VERSION 5.8 ;
BUSBITCHARS "[]" ;
DIVIDERCHAR "/" ;
UNITS
    DATABASE MICRONS 1000 ;
END UNITS

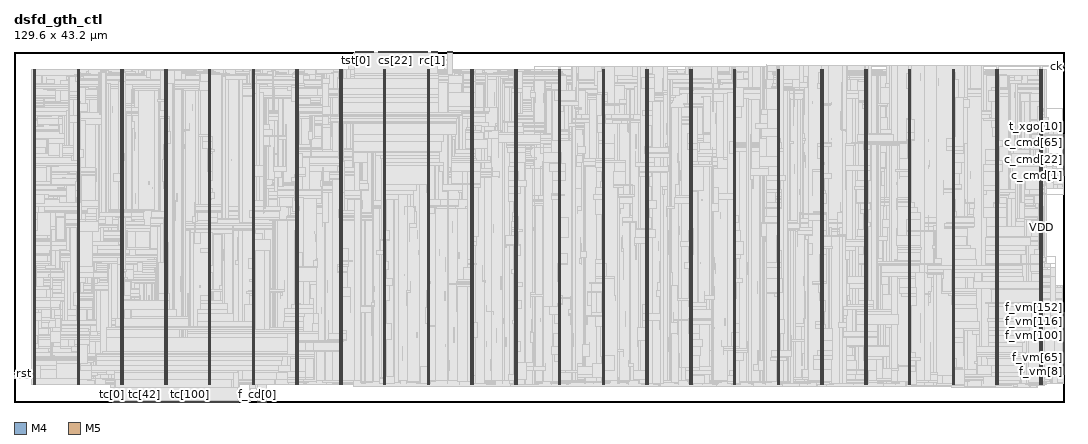
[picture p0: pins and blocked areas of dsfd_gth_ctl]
MACRO dsfd_gth_ctl
  FOREIGN dsfd_gth_ctl 0 0 ;
  CLASS BLOCK ;
  SIZE 129.6 BY 43.2 ;
  PIN c_cmd[0]
    DIRECTION INPUT ;
    USE SIGNAL ;
    PORT
      LAYER M4 ;
        RECT  129.516 27.936 129.6 27.96 ;
    END
  END c_cmd[0]
  PIN c_cmd[10]
    DIRECTION INPUT ;
    USE SIGNAL ;
    PORT
      LAYER M4 ;
        RECT  129.516 28.416 129.6 28.44 ;
    END
  END c_cmd[10]
  PIN c_cmd[11]
    DIRECTION INPUT ;
    USE SIGNAL ;
    PORT
      LAYER M4 ;
        RECT  129.516 28.464 129.6 28.488 ;
    END
  END c_cmd[11]
  PIN c_cmd[12]
    DIRECTION INPUT ;
    USE SIGNAL ;
    PORT
      LAYER M4 ;
        RECT  129.516 28.512 129.6 28.536 ;
    END
  END c_cmd[12]
  PIN c_cmd[13]
    DIRECTION INPUT ;
    USE SIGNAL ;
    PORT
      LAYER M4 ;
        RECT  129.516 28.56 129.6 28.584 ;
    END
  END c_cmd[13]
  PIN c_cmd[14]
    DIRECTION INPUT ;
    USE SIGNAL ;
    PORT
      LAYER M4 ;
        RECT  129.516 28.608 129.6 28.632 ;
    END
  END c_cmd[14]
  PIN c_cmd[15]
    DIRECTION INPUT ;
    USE SIGNAL ;
    PORT
      LAYER M4 ;
        RECT  129.516 28.656 129.6 28.68 ;
    END
  END c_cmd[15]
  PIN c_cmd[16]
    DIRECTION INPUT ;
    USE SIGNAL ;
    PORT
      LAYER M4 ;
        RECT  129.516 28.704 129.6 28.728 ;
    END
  END c_cmd[16]
  PIN c_cmd[17]
    DIRECTION INPUT ;
    USE SIGNAL ;
    PORT
      LAYER M4 ;
        RECT  129.516 28.752 129.6 28.776 ;
    END
  END c_cmd[17]
  PIN c_cmd[18]
    DIRECTION INPUT ;
    USE SIGNAL ;
    PORT
      LAYER M4 ;
        RECT  129.516 28.8 129.6 28.824 ;
    END
  END c_cmd[18]
  PIN c_cmd[19]
    DIRECTION INPUT ;
    USE SIGNAL ;
    PORT
      LAYER M4 ;
        RECT  129.516 28.848 129.6 28.872 ;
    END
  END c_cmd[19]
  PIN c_cmd[1]
    DIRECTION INPUT ;
    USE SIGNAL ;
    PORT
      LAYER M4 ;
        RECT  129.516 27.984 129.6 28.008 ;
    END
  END c_cmd[1]
  PIN c_cmd[20]
    DIRECTION INPUT ;
    USE SIGNAL ;
    PORT
      LAYER M4 ;
        RECT  129.516 28.896 129.6 28.92 ;
    END
  END c_cmd[20]
  PIN c_cmd[21]
    DIRECTION INPUT ;
    USE SIGNAL ;
    PORT
      LAYER M4 ;
        RECT  129.516 28.944 129.6 28.968 ;
    END
  END c_cmd[21]
  PIN c_cmd[22]
    DIRECTION INPUT ;
    USE SIGNAL ;
    PORT
      LAYER M4 ;
        RECT  129.516 28.992 129.6 29.016 ;
    END
  END c_cmd[22]
  PIN c_cmd[23]
    DIRECTION INPUT ;
    USE SIGNAL ;
    PORT
      LAYER M4 ;
        RECT  129.516 29.04 129.6 29.064 ;
    END
  END c_cmd[23]
  PIN c_cmd[24]
    DIRECTION INPUT ;
    USE SIGNAL ;
    PORT
      LAYER M4 ;
        RECT  129.516 29.088 129.6 29.112 ;
    END
  END c_cmd[24]
  PIN c_cmd[25]
    DIRECTION INPUT ;
    USE SIGNAL ;
    PORT
      LAYER M4 ;
        RECT  129.516 29.136 129.6 29.16 ;
    END
  END c_cmd[25]
  PIN c_cmd[26]
    DIRECTION INPUT ;
    USE SIGNAL ;
    PORT
      LAYER M4 ;
        RECT  129.516 29.184 129.6 29.208 ;
    END
  END c_cmd[26]
  PIN c_cmd[27]
    DIRECTION INPUT ;
    USE SIGNAL ;
    PORT
      LAYER M4 ;
        RECT  129.516 29.232 129.6 29.256 ;
    END
  END c_cmd[27]
  PIN c_cmd[28]
    DIRECTION INPUT ;
    USE SIGNAL ;
    PORT
      LAYER M4 ;
        RECT  129.516 29.28 129.6 29.304 ;
    END
  END c_cmd[28]
  PIN c_cmd[29]
    DIRECTION INPUT ;
    USE SIGNAL ;
    PORT
      LAYER M4 ;
        RECT  129.516 29.328 129.6 29.352 ;
    END
  END c_cmd[29]
  PIN c_cmd[2]
    DIRECTION INPUT ;
    USE SIGNAL ;
    PORT
      LAYER M4 ;
        RECT  129.516 28.032 129.6 28.056 ;
    END
  END c_cmd[2]
  PIN c_cmd[30]
    DIRECTION INPUT ;
    USE SIGNAL ;
    PORT
      LAYER M4 ;
        RECT  129.516 29.376 129.6 29.4 ;
    END
  END c_cmd[30]
  PIN c_cmd[31]
    DIRECTION INPUT ;
    USE SIGNAL ;
    PORT
      LAYER M4 ;
        RECT  129.516 29.424 129.6 29.448 ;
    END
  END c_cmd[31]
  PIN c_cmd[32]
    DIRECTION INPUT ;
    USE SIGNAL ;
    PORT
      LAYER M4 ;
        RECT  129.516 29.472 129.6 29.496 ;
    END
  END c_cmd[32]
  PIN c_cmd[33]
    DIRECTION INPUT ;
    USE SIGNAL ;
    PORT
      LAYER M4 ;
        RECT  129.516 29.52 129.6 29.544 ;
    END
  END c_cmd[33]
  PIN c_cmd[34]
    DIRECTION INPUT ;
    USE SIGNAL ;
    PORT
      LAYER M4 ;
        RECT  129.516 29.568 129.6 29.592 ;
    END
  END c_cmd[34]
  PIN c_cmd[35]
    DIRECTION INPUT ;
    USE SIGNAL ;
    PORT
      LAYER M4 ;
        RECT  129.516 29.616 129.6 29.64 ;
    END
  END c_cmd[35]
  PIN c_cmd[36]
    DIRECTION INPUT ;
    USE SIGNAL ;
    PORT
      LAYER M4 ;
        RECT  129.516 29.664 129.6 29.688 ;
    END
  END c_cmd[36]
  PIN c_cmd[37]
    DIRECTION INPUT ;
    USE SIGNAL ;
    PORT
      LAYER M4 ;
        RECT  129.516 29.712 129.6 29.736 ;
    END
  END c_cmd[37]
  PIN c_cmd[38]
    DIRECTION INPUT ;
    USE SIGNAL ;
    PORT
      LAYER M4 ;
        RECT  129.516 29.76 129.6 29.784 ;
    END
  END c_cmd[38]
  PIN c_cmd[39]
    DIRECTION INPUT ;
    USE SIGNAL ;
    PORT
      LAYER M4 ;
        RECT  129.516 29.808 129.6 29.832 ;
    END
  END c_cmd[39]
  PIN c_cmd[3]
    DIRECTION INPUT ;
    USE SIGNAL ;
    PORT
      LAYER M4 ;
        RECT  129.516 28.08 129.6 28.104 ;
    END
  END c_cmd[3]
  PIN c_cmd[40]
    DIRECTION INPUT ;
    USE SIGNAL ;
    PORT
      LAYER M4 ;
        RECT  129.516 29.856 129.6 29.88 ;
    END
  END c_cmd[40]
  PIN c_cmd[41]
    DIRECTION INPUT ;
    USE SIGNAL ;
    PORT
      LAYER M4 ;
        RECT  129.516 29.904 129.6 29.928 ;
    END
  END c_cmd[41]
  PIN c_cmd[42]
    DIRECTION INPUT ;
    USE SIGNAL ;
    PORT
      LAYER M4 ;
        RECT  129.516 29.952 129.6 29.976 ;
    END
  END c_cmd[42]
  PIN c_cmd[43]
    DIRECTION INPUT ;
    USE SIGNAL ;
    PORT
      LAYER M4 ;
        RECT  129.516 30 129.6 30.024 ;
    END
  END c_cmd[43]
  PIN c_cmd[44]
    DIRECTION INPUT ;
    USE SIGNAL ;
    PORT
      LAYER M4 ;
        RECT  129.516 30.048 129.6 30.072 ;
    END
  END c_cmd[44]
  PIN c_cmd[45]
    DIRECTION INPUT ;
    USE SIGNAL ;
    PORT
      LAYER M4 ;
        RECT  129.516 30.096 129.6 30.12 ;
    END
  END c_cmd[45]
  PIN c_cmd[46]
    DIRECTION INPUT ;
    USE SIGNAL ;
    PORT
      LAYER M4 ;
        RECT  129.516 30.144 129.6 30.168 ;
    END
  END c_cmd[46]
  PIN c_cmd[47]
    DIRECTION INPUT ;
    USE SIGNAL ;
    PORT
      LAYER M4 ;
        RECT  129.516 30.192 129.6 30.216 ;
    END
  END c_cmd[47]
  PIN c_cmd[48]
    DIRECTION INPUT ;
    USE SIGNAL ;
    PORT
      LAYER M4 ;
        RECT  129.516 30.24 129.6 30.264 ;
    END
  END c_cmd[48]
  PIN c_cmd[49]
    DIRECTION INPUT ;
    USE SIGNAL ;
    PORT
      LAYER M4 ;
        RECT  129.516 30.288 129.6 30.312 ;
    END
  END c_cmd[49]
  PIN c_cmd[4]
    DIRECTION INPUT ;
    USE SIGNAL ;
    PORT
      LAYER M4 ;
        RECT  129.516 28.128 129.6 28.152 ;
    END
  END c_cmd[4]
  PIN c_cmd[50]
    DIRECTION INPUT ;
    USE SIGNAL ;
    PORT
      LAYER M4 ;
        RECT  129.516 30.336 129.6 30.36 ;
    END
  END c_cmd[50]
  PIN c_cmd[51]
    DIRECTION INPUT ;
    USE SIGNAL ;
    PORT
      LAYER M4 ;
        RECT  129.516 30.384 129.6 30.408 ;
    END
  END c_cmd[51]
  PIN c_cmd[52]
    DIRECTION INPUT ;
    USE SIGNAL ;
    PORT
      LAYER M4 ;
        RECT  129.516 30.432 129.6 30.456 ;
    END
  END c_cmd[52]
  PIN c_cmd[53]
    DIRECTION INPUT ;
    USE SIGNAL ;
    PORT
      LAYER M4 ;
        RECT  129.516 30.48 129.6 30.504 ;
    END
  END c_cmd[53]
  PIN c_cmd[54]
    DIRECTION INPUT ;
    USE SIGNAL ;
    PORT
      LAYER M4 ;
        RECT  129.516 30.528 129.6 30.552 ;
    END
  END c_cmd[54]
  PIN c_cmd[55]
    DIRECTION INPUT ;
    USE SIGNAL ;
    PORT
      LAYER M4 ;
        RECT  129.516 30.576 129.6 30.6 ;
    END
  END c_cmd[55]
  PIN c_cmd[56]
    DIRECTION INPUT ;
    USE SIGNAL ;
    PORT
      LAYER M4 ;
        RECT  129.516 30.624 129.6 30.648 ;
    END
  END c_cmd[56]
  PIN c_cmd[57]
    DIRECTION INPUT ;
    USE SIGNAL ;
    PORT
      LAYER M4 ;
        RECT  129.516 30.672 129.6 30.696 ;
    END
  END c_cmd[57]
  PIN c_cmd[58]
    DIRECTION INPUT ;
    USE SIGNAL ;
    PORT
      LAYER M4 ;
        RECT  129.516 30.72 129.6 30.744 ;
    END
  END c_cmd[58]
  PIN c_cmd[59]
    DIRECTION INPUT ;
    USE SIGNAL ;
    PORT
      LAYER M4 ;
        RECT  129.516 30.768 129.6 30.792 ;
    END
  END c_cmd[59]
  PIN c_cmd[5]
    DIRECTION INPUT ;
    USE SIGNAL ;
    PORT
      LAYER M4 ;
        RECT  129.516 28.176 129.6 28.2 ;
    END
  END c_cmd[5]
  PIN c_cmd[60]
    DIRECTION INPUT ;
    USE SIGNAL ;
    PORT
      LAYER M4 ;
        RECT  129.516 30.816 129.6 30.84 ;
    END
  END c_cmd[60]
  PIN c_cmd[61]
    DIRECTION INPUT ;
    USE SIGNAL ;
    PORT
      LAYER M4 ;
        RECT  129.516 30.864 129.6 30.888 ;
    END
  END c_cmd[61]
  PIN c_cmd[62]
    DIRECTION INPUT ;
    USE SIGNAL ;
    PORT
      LAYER M4 ;
        RECT  129.516 30.912 129.6 30.936 ;
    END
  END c_cmd[62]
  PIN c_cmd[63]
    DIRECTION INPUT ;
    USE SIGNAL ;
    PORT
      LAYER M4 ;
        RECT  129.516 30.96 129.6 30.984 ;
    END
  END c_cmd[63]
  PIN c_cmd[64]
    DIRECTION INPUT ;
    USE SIGNAL ;
    PORT
      LAYER M4 ;
        RECT  129.516 31.008 129.6 31.032 ;
    END
  END c_cmd[64]
  PIN c_cmd[65]
    DIRECTION INPUT ;
    USE SIGNAL ;
    PORT
      LAYER M4 ;
        RECT  129.516 31.056 129.6 31.08 ;
    END
  END c_cmd[65]
  PIN c_cmd[66]
    DIRECTION INPUT ;
    USE SIGNAL ;
    PORT
      LAYER M4 ;
        RECT  129.516 31.104 129.6 31.128 ;
    END
  END c_cmd[66]
  PIN c_cmd[67]
    DIRECTION INPUT ;
    USE SIGNAL ;
    PORT
      LAYER M4 ;
        RECT  129.516 31.152 129.6 31.176 ;
    END
  END c_cmd[67]
  PIN c_cmd[68]
    DIRECTION INPUT ;
    USE SIGNAL ;
    PORT
      LAYER M4 ;
        RECT  129.516 31.2 129.6 31.224 ;
    END
  END c_cmd[68]
  PIN c_cmd[69]
    DIRECTION INPUT ;
    USE SIGNAL ;
    PORT
      LAYER M4 ;
        RECT  129.516 31.248 129.6 31.272 ;
    END
  END c_cmd[69]
  PIN c_cmd[6]
    DIRECTION INPUT ;
    USE SIGNAL ;
    PORT
      LAYER M4 ;
        RECT  129.516 28.224 129.6 28.248 ;
    END
  END c_cmd[6]
  PIN c_cmd[70]
    DIRECTION INPUT ;
    USE SIGNAL ;
    PORT
      LAYER M4 ;
        RECT  129.516 31.296 129.6 31.32 ;
    END
  END c_cmd[70]
  PIN c_cmd[71]
    DIRECTION INPUT ;
    USE SIGNAL ;
    PORT
      LAYER M4 ;
        RECT  129.516 31.344 129.6 31.368 ;
    END
  END c_cmd[71]
  PIN c_cmd[72]
    DIRECTION INPUT ;
    USE SIGNAL ;
    PORT
      LAYER M4 ;
        RECT  129.516 31.392 129.6 31.416 ;
    END
  END c_cmd[72]
  PIN c_cmd[73]
    DIRECTION INPUT ;
    USE SIGNAL ;
    PORT
      LAYER M4 ;
        RECT  129.516 31.44 129.6 31.464 ;
    END
  END c_cmd[73]
  PIN c_cmd[74]
    DIRECTION INPUT ;
    USE SIGNAL ;
    PORT
      LAYER M4 ;
        RECT  129.516 31.488 129.6 31.512 ;
    END
  END c_cmd[74]
  PIN c_cmd[75]
    DIRECTION INPUT ;
    USE SIGNAL ;
    PORT
      LAYER M4 ;
        RECT  129.516 31.536 129.6 31.56 ;
    END
  END c_cmd[75]
  PIN c_cmd[76]
    DIRECTION INPUT ;
    USE SIGNAL ;
    PORT
      LAYER M4 ;
        RECT  129.516 31.584 129.6 31.608 ;
    END
  END c_cmd[76]
  PIN c_cmd[77]
    DIRECTION INPUT ;
    USE SIGNAL ;
    PORT
      LAYER M4 ;
        RECT  129.516 31.632 129.6 31.656 ;
    END
  END c_cmd[77]
  PIN c_cmd[78]
    DIRECTION INPUT ;
    USE SIGNAL ;
    PORT
      LAYER M4 ;
        RECT  129.516 31.68 129.6 31.704 ;
    END
  END c_cmd[78]
  PIN c_cmd[79]
    DIRECTION INPUT ;
    USE SIGNAL ;
    PORT
      LAYER M4 ;
        RECT  129.516 31.728 129.6 31.752 ;
    END
  END c_cmd[79]
  PIN c_cmd[7]
    DIRECTION INPUT ;
    USE SIGNAL ;
    PORT
      LAYER M4 ;
        RECT  129.516 28.272 129.6 28.296 ;
    END
  END c_cmd[7]
  PIN c_cmd[80]
    DIRECTION INPUT ;
    USE SIGNAL ;
    PORT
      LAYER M4 ;
        RECT  129.516 31.776 129.6 31.8 ;
    END
  END c_cmd[80]
  PIN c_cmd[81]
    DIRECTION INPUT ;
    USE SIGNAL ;
    PORT
      LAYER M4 ;
        RECT  129.516 31.824 129.6 31.848 ;
    END
  END c_cmd[81]
  PIN c_cmd[82]
    DIRECTION INPUT ;
    USE SIGNAL ;
    PORT
      LAYER M4 ;
        RECT  129.516 31.872 129.6 31.896 ;
    END
  END c_cmd[82]
  PIN c_cmd[83]
    DIRECTION INPUT ;
    USE SIGNAL ;
    PORT
      LAYER M4 ;
        RECT  129.516 31.92 129.6 31.944 ;
    END
  END c_cmd[83]
  PIN c_cmd[84]
    DIRECTION INPUT ;
    USE SIGNAL ;
    PORT
      LAYER M4 ;
        RECT  129.516 31.968 129.6 31.992 ;
    END
  END c_cmd[84]
  PIN c_cmd[8]
    DIRECTION INPUT ;
    USE SIGNAL ;
    PORT
      LAYER M4 ;
        RECT  129.516 28.32 129.6 28.344 ;
    END
  END c_cmd[8]
  PIN c_cmd[9]
    DIRECTION INPUT ;
    USE SIGNAL ;
    PORT
      LAYER M4 ;
        RECT  129.516 28.368 129.6 28.392 ;
    END
  END c_cmd[9]
  PIN c_done[0]
    DIRECTION OUTPUT ;
    USE SIGNAL ;
    PORT
      LAYER M4 ;
        RECT  129.516 32.016 129.6 32.04 ;
    END
  END c_done[0]
  PIN c_done[1]
    DIRECTION OUTPUT ;
    USE SIGNAL ;
    PORT
      LAYER M4 ;
        RECT  129.516 32.064 129.6 32.088 ;
    END
  END c_done[1]
  PIN c_done[2]
    DIRECTION OUTPUT ;
    USE SIGNAL ;
    PORT
      LAYER M4 ;
        RECT  129.516 32.112 129.6 32.136 ;
    END
  END c_done[2]
  PIN c_done[3]
    DIRECTION OUTPUT ;
    USE SIGNAL ;
    PORT
      LAYER M4 ;
        RECT  129.516 32.16 129.6 32.184 ;
    END
  END c_done[3]
  PIN c_done[4]
    DIRECTION OUTPUT ;
    USE SIGNAL ;
    PORT
      LAYER M4 ;
        RECT  129.516 32.208 129.6 32.232 ;
    END
  END c_done[4]
  PIN c_done[5]
    DIRECTION OUTPUT ;
    USE SIGNAL ;
    PORT
      LAYER M4 ;
        RECT  129.516 32.256 129.6 32.28 ;
    END
  END c_done[5]
  PIN c_done[6]
    DIRECTION OUTPUT ;
    USE SIGNAL ;
    PORT
      LAYER M4 ;
        RECT  129.516 32.304 129.6 32.328 ;
    END
  END c_done[6]
  PIN c_done[7]
    DIRECTION OUTPUT ;
    USE SIGNAL ;
    PORT
      LAYER M4 ;
        RECT  129.516 32.352 129.6 32.376 ;
    END
  END c_done[7]
  PIN c_done[8]
    DIRECTION OUTPUT ;
    USE SIGNAL ;
    PORT
      LAYER M4 ;
        RECT  129.516 32.4 129.6 32.424 ;
    END
  END c_done[8]
  PIN c_st[0]
    DIRECTION OUTPUT ;
    USE SIGNAL ;
    PORT
      LAYER M4 ;
        RECT  129.516 32.448 129.6 32.472 ;
    END
  END c_st[0]
  PIN c_st[1]
    DIRECTION OUTPUT ;
    USE SIGNAL ;
    PORT
      LAYER M4 ;
        RECT  129.516 32.496 129.6 32.52 ;
    END
  END c_st[1]
  PIN ck
    DIRECTION INPUT ;
    USE SIGNAL ;
    PORT
      LAYER M4 ;
        RECT  129.516 41.376 129.6 41.4 ;
    END
  END ck
  PIN ckv
    DIRECTION INPUT ;
    USE SIGNAL ;
    PORT
      LAYER M4 ;
        RECT  129.516 41.568 129.6 41.592 ;
    END
  END ckv
  PIN cs[0]
    DIRECTION INPUT ;
    USE SIGNAL ;
    PORT
      LAYER M5 ;
        RECT  45.024 43.116 45.048 43.2 ;
    END
  END cs[0]
  PIN cs[10]
    DIRECTION INPUT ;
    USE SIGNAL ;
    PORT
      LAYER M5 ;
        RECT  45.984 43.116 46.008 43.2 ;
    END
  END cs[10]
  PIN cs[11]
    DIRECTION INPUT ;
    USE SIGNAL ;
    PORT
      LAYER M5 ;
        RECT  46.08 43.116 46.104 43.2 ;
    END
  END cs[11]
  PIN cs[12]
    DIRECTION INPUT ;
    USE SIGNAL ;
    PORT
      LAYER M5 ;
        RECT  46.176 43.116 46.2 43.2 ;
    END
  END cs[12]
  PIN cs[13]
    DIRECTION INPUT ;
    USE SIGNAL ;
    PORT
      LAYER M5 ;
        RECT  46.272 43.116 46.296 43.2 ;
    END
  END cs[13]
  PIN cs[14]
    DIRECTION INPUT ;
    USE SIGNAL ;
    PORT
      LAYER M5 ;
        RECT  46.368 43.116 46.392 43.2 ;
    END
  END cs[14]
  PIN cs[15]
    DIRECTION INPUT ;
    USE SIGNAL ;
    PORT
      LAYER M5 ;
        RECT  46.464 43.116 46.488 43.2 ;
    END
  END cs[15]
  PIN cs[16]
    DIRECTION INPUT ;
    USE SIGNAL ;
    PORT
      LAYER M5 ;
        RECT  46.56 43.116 46.584 43.2 ;
    END
  END cs[16]
  PIN cs[17]
    DIRECTION INPUT ;
    USE SIGNAL ;
    PORT
      LAYER M5 ;
        RECT  46.656 43.116 46.68 43.2 ;
    END
  END cs[17]
  PIN cs[18]
    DIRECTION INPUT ;
    USE SIGNAL ;
    PORT
      LAYER M5 ;
        RECT  46.752 43.116 46.776 43.2 ;
    END
  END cs[18]
  PIN cs[19]
    DIRECTION INPUT ;
    USE SIGNAL ;
    PORT
      LAYER M5 ;
        RECT  46.848 43.116 46.872 43.2 ;
    END
  END cs[19]
  PIN cs[1]
    DIRECTION INPUT ;
    USE SIGNAL ;
    PORT
      LAYER M5 ;
        RECT  45.12 43.116 45.144 43.2 ;
    END
  END cs[1]
  PIN cs[20]
    DIRECTION INPUT ;
    USE SIGNAL ;
    PORT
      LAYER M5 ;
        RECT  46.944 43.116 46.968 43.2 ;
    END
  END cs[20]
  PIN cs[21]
    DIRECTION INPUT ;
    USE SIGNAL ;
    PORT
      LAYER M5 ;
        RECT  47.04 43.116 47.064 43.2 ;
    END
  END cs[21]
  PIN cs[22]
    DIRECTION INPUT ;
    USE SIGNAL ;
    PORT
      LAYER M5 ;
        RECT  47.136 43.116 47.16 43.2 ;
    END
  END cs[22]
  PIN cs[23]
    DIRECTION INPUT ;
    USE SIGNAL ;
    PORT
      LAYER M5 ;
        RECT  47.232 43.116 47.256 43.2 ;
    END
  END cs[23]
  PIN cs[24]
    DIRECTION INPUT ;
    USE SIGNAL ;
    PORT
      LAYER M5 ;
        RECT  47.328 43.116 47.352 43.2 ;
    END
  END cs[24]
  PIN cs[25]
    DIRECTION INPUT ;
    USE SIGNAL ;
    PORT
      LAYER M5 ;
        RECT  47.424 43.116 47.448 43.2 ;
    END
  END cs[25]
  PIN cs[26]
    DIRECTION INPUT ;
    USE SIGNAL ;
    PORT
      LAYER M5 ;
        RECT  47.52 43.116 47.544 43.2 ;
    END
  END cs[26]
  PIN cs[27]
    DIRECTION INPUT ;
    USE SIGNAL ;
    PORT
      LAYER M5 ;
        RECT  47.616 43.116 47.64 43.2 ;
    END
  END cs[27]
  PIN cs[28]
    DIRECTION INPUT ;
    USE SIGNAL ;
    PORT
      LAYER M5 ;
        RECT  47.712 43.116 47.736 43.2 ;
    END
  END cs[28]
  PIN cs[29]
    DIRECTION INPUT ;
    USE SIGNAL ;
    PORT
      LAYER M5 ;
        RECT  47.808 43.116 47.832 43.2 ;
    END
  END cs[29]
  PIN cs[2]
    DIRECTION INPUT ;
    USE SIGNAL ;
    PORT
      LAYER M5 ;
        RECT  45.216 43.116 45.24 43.2 ;
    END
  END cs[2]
  PIN cs[30]
    DIRECTION INPUT ;
    USE SIGNAL ;
    PORT
      LAYER M5 ;
        RECT  47.904 43.116 47.928 43.2 ;
    END
  END cs[30]
  PIN cs[31]
    DIRECTION INPUT ;
    USE SIGNAL ;
    PORT
      LAYER M5 ;
        RECT  48 43.116 48.024 43.2 ;
    END
  END cs[31]
  PIN cs[32]
    DIRECTION INPUT ;
    USE SIGNAL ;
    PORT
      LAYER M5 ;
        RECT  48.096 43.116 48.12 43.2 ;
    END
  END cs[32]
  PIN cs[33]
    DIRECTION INPUT ;
    USE SIGNAL ;
    PORT
      LAYER M5 ;
        RECT  48.192 43.116 48.216 43.2 ;
    END
  END cs[33]
  PIN cs[34]
    DIRECTION INPUT ;
    USE SIGNAL ;
    PORT
      LAYER M5 ;
        RECT  48.288 43.116 48.312 43.2 ;
    END
  END cs[34]
  PIN cs[35]
    DIRECTION INPUT ;
    USE SIGNAL ;
    PORT
      LAYER M5 ;
        RECT  48.384 43.116 48.408 43.2 ;
    END
  END cs[35]
  PIN cs[36]
    DIRECTION INPUT ;
    USE SIGNAL ;
    PORT
      LAYER M5 ;
        RECT  48.48 43.116 48.504 43.2 ;
    END
  END cs[36]
  PIN cs[37]
    DIRECTION INPUT ;
    USE SIGNAL ;
    PORT
      LAYER M5 ;
        RECT  48.576 43.116 48.6 43.2 ;
    END
  END cs[37]
  PIN cs[38]
    DIRECTION INPUT ;
    USE SIGNAL ;
    PORT
      LAYER M5 ;
        RECT  48.672 43.116 48.696 43.2 ;
    END
  END cs[38]
  PIN cs[39]
    DIRECTION INPUT ;
    USE SIGNAL ;
    PORT
      LAYER M5 ;
        RECT  48.768 43.116 48.792 43.2 ;
    END
  END cs[39]
  PIN cs[3]
    DIRECTION INPUT ;
    USE SIGNAL ;
    PORT
      LAYER M5 ;
        RECT  45.312 43.116 45.336 43.2 ;
    END
  END cs[3]
  PIN cs[40]
    DIRECTION INPUT ;
    USE SIGNAL ;
    PORT
      LAYER M5 ;
        RECT  48.864 43.116 48.888 43.2 ;
    END
  END cs[40]
  PIN cs[41]
    DIRECTION INPUT ;
    USE SIGNAL ;
    PORT
      LAYER M5 ;
        RECT  48.96 43.116 48.984 43.2 ;
    END
  END cs[41]
  PIN cs[42]
    DIRECTION INPUT ;
    USE SIGNAL ;
    PORT
      LAYER M5 ;
        RECT  49.056 43.116 49.08 43.2 ;
    END
  END cs[42]
  PIN cs[43]
    DIRECTION INPUT ;
    USE SIGNAL ;
    PORT
      LAYER M5 ;
        RECT  49.152 43.116 49.176 43.2 ;
    END
  END cs[43]
  PIN cs[44]
    DIRECTION INPUT ;
    USE SIGNAL ;
    PORT
      LAYER M5 ;
        RECT  49.248 43.116 49.272 43.2 ;
    END
  END cs[44]
  PIN cs[45]
    DIRECTION INPUT ;
    USE SIGNAL ;
    PORT
      LAYER M5 ;
        RECT  49.344 43.116 49.368 43.2 ;
    END
  END cs[45]
  PIN cs[46]
    DIRECTION INPUT ;
    USE SIGNAL ;
    PORT
      LAYER M5 ;
        RECT  49.44 43.116 49.464 43.2 ;
    END
  END cs[46]
  PIN cs[47]
    DIRECTION INPUT ;
    USE SIGNAL ;
    PORT
      LAYER M5 ;
        RECT  49.536 43.116 49.56 43.2 ;
    END
  END cs[47]
  PIN cs[48]
    DIRECTION INPUT ;
    USE SIGNAL ;
    PORT
      LAYER M5 ;
        RECT  49.632 43.116 49.656 43.2 ;
    END
  END cs[48]
  PIN cs[49]
    DIRECTION INPUT ;
    USE SIGNAL ;
    PORT
      LAYER M5 ;
        RECT  49.728 43.116 49.752 43.2 ;
    END
  END cs[49]
  PIN cs[4]
    DIRECTION INPUT ;
    USE SIGNAL ;
    PORT
      LAYER M5 ;
        RECT  45.408 43.116 45.432 43.2 ;
    END
  END cs[4]
  PIN cs[50]
    DIRECTION INPUT ;
    USE SIGNAL ;
    PORT
      LAYER M5 ;
        RECT  49.824 43.116 49.848 43.2 ;
    END
  END cs[50]
  PIN cs[51]
    DIRECTION INPUT ;
    USE SIGNAL ;
    PORT
      LAYER M5 ;
        RECT  49.92 43.116 49.944 43.2 ;
    END
  END cs[51]
  PIN cs[52]
    DIRECTION INPUT ;
    USE SIGNAL ;
    PORT
      LAYER M5 ;
        RECT  50.016 43.116 50.04 43.2 ;
    END
  END cs[52]
  PIN cs[53]
    DIRECTION INPUT ;
    USE SIGNAL ;
    PORT
      LAYER M5 ;
        RECT  50.112 43.116 50.136 43.2 ;
    END
  END cs[53]
  PIN cs[54]
    DIRECTION INPUT ;
    USE SIGNAL ;
    PORT
      LAYER M5 ;
        RECT  50.208 43.116 50.232 43.2 ;
    END
  END cs[54]
  PIN cs[55]
    DIRECTION INPUT ;
    USE SIGNAL ;
    PORT
      LAYER M5 ;
        RECT  50.304 43.116 50.328 43.2 ;
    END
  END cs[55]
  PIN cs[56]
    DIRECTION INPUT ;
    USE SIGNAL ;
    PORT
      LAYER M5 ;
        RECT  50.4 43.116 50.424 43.2 ;
    END
  END cs[56]
  PIN cs[57]
    DIRECTION INPUT ;
    USE SIGNAL ;
    PORT
      LAYER M5 ;
        RECT  50.496 43.116 50.52 43.2 ;
    END
  END cs[57]
  PIN cs[58]
    DIRECTION INPUT ;
    USE SIGNAL ;
    PORT
      LAYER M5 ;
        RECT  50.592 43.116 50.616 43.2 ;
    END
  END cs[58]
  PIN cs[59]
    DIRECTION INPUT ;
    USE SIGNAL ;
    PORT
      LAYER M5 ;
        RECT  50.688 43.116 50.712 43.2 ;
    END
  END cs[59]
  PIN cs[5]
    DIRECTION INPUT ;
    USE SIGNAL ;
    PORT
      LAYER M5 ;
        RECT  45.504 43.116 45.528 43.2 ;
    END
  END cs[5]
  PIN cs[60]
    DIRECTION INPUT ;
    USE SIGNAL ;
    PORT
      LAYER M5 ;
        RECT  50.784 43.116 50.808 43.2 ;
    END
  END cs[60]
  PIN cs[61]
    DIRECTION INPUT ;
    USE SIGNAL ;
    PORT
      LAYER M5 ;
        RECT  50.88 43.116 50.904 43.2 ;
    END
  END cs[61]
  PIN cs[62]
    DIRECTION INPUT ;
    USE SIGNAL ;
    PORT
      LAYER M5 ;
        RECT  50.976 43.116 51 43.2 ;
    END
  END cs[62]
  PIN cs[63]
    DIRECTION INPUT ;
    USE SIGNAL ;
    PORT
      LAYER M5 ;
        RECT  51.072 43.116 51.096 43.2 ;
    END
  END cs[63]
  PIN cs[6]
    DIRECTION INPUT ;
    USE SIGNAL ;
    PORT
      LAYER M5 ;
        RECT  45.6 43.116 45.624 43.2 ;
    END
  END cs[6]
  PIN cs[7]
    DIRECTION INPUT ;
    USE SIGNAL ;
    PORT
      LAYER M5 ;
        RECT  45.696 43.116 45.72 43.2 ;
    END
  END cs[7]
  PIN cs[8]
    DIRECTION INPUT ;
    USE SIGNAL ;
    PORT
      LAYER M5 ;
        RECT  45.792 43.116 45.816 43.2 ;
    END
  END cs[8]
  PIN cs[9]
    DIRECTION INPUT ;
    USE SIGNAL ;
    PORT
      LAYER M5 ;
        RECT  45.888 43.116 45.912 43.2 ;
    END
  END cs[9]
  PIN f_cd[0]
    DIRECTION INPUT ;
    USE SIGNAL ;
    PORT
      LAYER M5 ;
        RECT  30.048 0 30.072 0.084 ;
    END
  END f_cd[0]
  PIN f_cd[10]
    DIRECTION INPUT ;
    USE SIGNAL ;
    PORT
      LAYER M5 ;
        RECT  31.008 0 31.032 0.084 ;
    END
  END f_cd[10]
  PIN f_cd[11]
    DIRECTION INPUT ;
    USE SIGNAL ;
    PORT
      LAYER M5 ;
        RECT  31.104 0 31.128 0.084 ;
    END
  END f_cd[11]
  PIN f_cd[1]
    DIRECTION INPUT ;
    USE SIGNAL ;
    PORT
      LAYER M5 ;
        RECT  30.144 0 30.168 0.084 ;
    END
  END f_cd[1]
  PIN f_cd[2]
    DIRECTION INPUT ;
    USE SIGNAL ;
    PORT
      LAYER M5 ;
        RECT  30.24 0 30.264 0.084 ;
    END
  END f_cd[2]
  PIN f_cd[3]
    DIRECTION INPUT ;
    USE SIGNAL ;
    PORT
      LAYER M5 ;
        RECT  30.336 0 30.36 0.084 ;
    END
  END f_cd[3]
  PIN f_cd[4]
    DIRECTION INPUT ;
    USE SIGNAL ;
    PORT
      LAYER M5 ;
        RECT  30.432 0 30.456 0.084 ;
    END
  END f_cd[4]
  PIN f_cd[5]
    DIRECTION INPUT ;
    USE SIGNAL ;
    PORT
      LAYER M5 ;
        RECT  30.528 0 30.552 0.084 ;
    END
  END f_cd[5]
  PIN f_cd[6]
    DIRECTION INPUT ;
    USE SIGNAL ;
    PORT
      LAYER M5 ;
        RECT  30.624 0 30.648 0.084 ;
    END
  END f_cd[6]
  PIN f_cd[7]
    DIRECTION INPUT ;
    USE SIGNAL ;
    PORT
      LAYER M5 ;
        RECT  30.72 0 30.744 0.084 ;
    END
  END f_cd[7]
  PIN f_cd[8]
    DIRECTION INPUT ;
    USE SIGNAL ;
    PORT
      LAYER M5 ;
        RECT  30.816 0 30.84 0.084 ;
    END
  END f_cd[8]
  PIN f_cd[9]
    DIRECTION INPUT ;
    USE SIGNAL ;
    PORT
      LAYER M5 ;
        RECT  30.912 0 30.936 0.084 ;
    END
  END f_cd[9]
  PIN f_vm[0]
    DIRECTION INPUT ;
    USE SIGNAL ;
    PORT
      LAYER M4 ;
        RECT  129.516 3.36 129.6 3.384 ;
    END
  END f_vm[0]
  PIN f_vm[100]
    DIRECTION INPUT ;
    USE SIGNAL ;
    PORT
      LAYER M4 ;
        RECT  129.516 8.16 129.6 8.184 ;
    END
  END f_vm[100]
  PIN f_vm[101]
    DIRECTION INPUT ;
    USE SIGNAL ;
    PORT
      LAYER M4 ;
        RECT  129.516 8.208 129.6 8.232 ;
    END
  END f_vm[101]
  PIN f_vm[102]
    DIRECTION INPUT ;
    USE SIGNAL ;
    PORT
      LAYER M4 ;
        RECT  129.516 8.256 129.6 8.28 ;
    END
  END f_vm[102]
  PIN f_vm[103]
    DIRECTION INPUT ;
    USE SIGNAL ;
    PORT
      LAYER M4 ;
        RECT  129.516 8.304 129.6 8.328 ;
    END
  END f_vm[103]
  PIN f_vm[104]
    DIRECTION INPUT ;
    USE SIGNAL ;
    PORT
      LAYER M4 ;
        RECT  129.516 8.352 129.6 8.376 ;
    END
  END f_vm[104]
  PIN f_vm[105]
    DIRECTION INPUT ;
    USE SIGNAL ;
    PORT
      LAYER M4 ;
        RECT  129.516 8.4 129.6 8.424 ;
    END
  END f_vm[105]
  PIN f_vm[106]
    DIRECTION INPUT ;
    USE SIGNAL ;
    PORT
      LAYER M4 ;
        RECT  129.516 8.448 129.6 8.472 ;
    END
  END f_vm[106]
  PIN f_vm[107]
    DIRECTION INPUT ;
    USE SIGNAL ;
    PORT
      LAYER M4 ;
        RECT  129.516 8.496 129.6 8.52 ;
    END
  END f_vm[107]
  PIN f_vm[108]
    DIRECTION INPUT ;
    USE SIGNAL ;
    PORT
      LAYER M4 ;
        RECT  129.516 8.544 129.6 8.568 ;
    END
  END f_vm[108]
  PIN f_vm[109]
    DIRECTION INPUT ;
    USE SIGNAL ;
    PORT
      LAYER M4 ;
        RECT  129.516 8.592 129.6 8.616 ;
    END
  END f_vm[109]
  PIN f_vm[10]
    DIRECTION INPUT ;
    USE SIGNAL ;
    PORT
      LAYER M4 ;
        RECT  129.516 3.84 129.6 3.864 ;
    END
  END f_vm[10]
  PIN f_vm[110]
    DIRECTION INPUT ;
    USE SIGNAL ;
    PORT
      LAYER M4 ;
        RECT  129.516 8.64 129.6 8.664 ;
    END
  END f_vm[110]
  PIN f_vm[111]
    DIRECTION INPUT ;
    USE SIGNAL ;
    PORT
      LAYER M4 ;
        RECT  129.516 8.688 129.6 8.712 ;
    END
  END f_vm[111]
  PIN f_vm[112]
    DIRECTION INPUT ;
    USE SIGNAL ;
    PORT
      LAYER M4 ;
        RECT  129.516 8.736 129.6 8.76 ;
    END
  END f_vm[112]
  PIN f_vm[113]
    DIRECTION INPUT ;
    USE SIGNAL ;
    PORT
      LAYER M4 ;
        RECT  129.516 8.784 129.6 8.808 ;
    END
  END f_vm[113]
  PIN f_vm[114]
    DIRECTION INPUT ;
    USE SIGNAL ;
    PORT
      LAYER M4 ;
        RECT  129.516 8.832 129.6 8.856 ;
    END
  END f_vm[114]
  PIN f_vm[115]
    DIRECTION INPUT ;
    USE SIGNAL ;
    PORT
      LAYER M4 ;
        RECT  129.516 8.88 129.6 8.904 ;
    END
  END f_vm[115]
  PIN f_vm[116]
    DIRECTION INPUT ;
    USE SIGNAL ;
    PORT
      LAYER M4 ;
        RECT  129.516 8.928 129.6 8.952 ;
    END
  END f_vm[116]
  PIN f_vm[117]
    DIRECTION INPUT ;
    USE SIGNAL ;
    PORT
      LAYER M4 ;
        RECT  129.516 8.976 129.6 9 ;
    END
  END f_vm[117]
  PIN f_vm[118]
    DIRECTION INPUT ;
    USE SIGNAL ;
    PORT
      LAYER M4 ;
        RECT  129.516 9.024 129.6 9.048 ;
    END
  END f_vm[118]
  PIN f_vm[119]
    DIRECTION INPUT ;
    USE SIGNAL ;
    PORT
      LAYER M4 ;
        RECT  129.516 9.072 129.6 9.096 ;
    END
  END f_vm[119]
  PIN f_vm[11]
    DIRECTION INPUT ;
    USE SIGNAL ;
    PORT
      LAYER M4 ;
        RECT  129.516 3.888 129.6 3.912 ;
    END
  END f_vm[11]
  PIN f_vm[120]
    DIRECTION INPUT ;
    USE SIGNAL ;
    PORT
      LAYER M4 ;
        RECT  129.516 9.12 129.6 9.144 ;
    END
  END f_vm[120]
  PIN f_vm[121]
    DIRECTION INPUT ;
    USE SIGNAL ;
    PORT
      LAYER M4 ;
        RECT  129.516 9.168 129.6 9.192 ;
    END
  END f_vm[121]
  PIN f_vm[122]
    DIRECTION INPUT ;
    USE SIGNAL ;
    PORT
      LAYER M4 ;
        RECT  129.516 9.216 129.6 9.24 ;
    END
  END f_vm[122]
  PIN f_vm[123]
    DIRECTION INPUT ;
    USE SIGNAL ;
    PORT
      LAYER M4 ;
        RECT  129.516 9.264 129.6 9.288 ;
    END
  END f_vm[123]
  PIN f_vm[124]
    DIRECTION INPUT ;
    USE SIGNAL ;
    PORT
      LAYER M4 ;
        RECT  129.516 9.312 129.6 9.336 ;
    END
  END f_vm[124]
  PIN f_vm[125]
    DIRECTION INPUT ;
    USE SIGNAL ;
    PORT
      LAYER M4 ;
        RECT  129.516 9.36 129.6 9.384 ;
    END
  END f_vm[125]
  PIN f_vm[126]
    DIRECTION INPUT ;
    USE SIGNAL ;
    PORT
      LAYER M4 ;
        RECT  129.516 9.408 129.6 9.432 ;
    END
  END f_vm[126]
  PIN f_vm[127]
    DIRECTION INPUT ;
    USE SIGNAL ;
    PORT
      LAYER M4 ;
        RECT  129.516 9.456 129.6 9.48 ;
    END
  END f_vm[127]
  PIN f_vm[128]
    DIRECTION INPUT ;
    USE SIGNAL ;
    PORT
      LAYER M4 ;
        RECT  129.516 9.504 129.6 9.528 ;
    END
  END f_vm[128]
  PIN f_vm[129]
    DIRECTION INPUT ;
    USE SIGNAL ;
    PORT
      LAYER M4 ;
        RECT  129.516 9.552 129.6 9.576 ;
    END
  END f_vm[129]
  PIN f_vm[12]
    DIRECTION INPUT ;
    USE SIGNAL ;
    PORT
      LAYER M4 ;
        RECT  129.516 3.936 129.6 3.96 ;
    END
  END f_vm[12]
  PIN f_vm[130]
    DIRECTION INPUT ;
    USE SIGNAL ;
    PORT
      LAYER M4 ;
        RECT  129.516 9.6 129.6 9.624 ;
    END
  END f_vm[130]
  PIN f_vm[131]
    DIRECTION INPUT ;
    USE SIGNAL ;
    PORT
      LAYER M4 ;
        RECT  129.516 9.648 129.6 9.672 ;
    END
  END f_vm[131]
  PIN f_vm[132]
    DIRECTION INPUT ;
    USE SIGNAL ;
    PORT
      LAYER M4 ;
        RECT  129.516 9.696 129.6 9.72 ;
    END
  END f_vm[132]
  PIN f_vm[133]
    DIRECTION INPUT ;
    USE SIGNAL ;
    PORT
      LAYER M4 ;
        RECT  129.516 9.744 129.6 9.768 ;
    END
  END f_vm[133]
  PIN f_vm[134]
    DIRECTION INPUT ;
    USE SIGNAL ;
    PORT
      LAYER M4 ;
        RECT  129.516 9.792 129.6 9.816 ;
    END
  END f_vm[134]
  PIN f_vm[135]
    DIRECTION INPUT ;
    USE SIGNAL ;
    PORT
      LAYER M4 ;
        RECT  129.516 9.84 129.6 9.864 ;
    END
  END f_vm[135]
  PIN f_vm[136]
    DIRECTION INPUT ;
    USE SIGNAL ;
    PORT
      LAYER M4 ;
        RECT  129.516 9.888 129.6 9.912 ;
    END
  END f_vm[136]
  PIN f_vm[137]
    DIRECTION INPUT ;
    USE SIGNAL ;
    PORT
      LAYER M4 ;
        RECT  129.516 9.936 129.6 9.96 ;
    END
  END f_vm[137]
  PIN f_vm[138]
    DIRECTION INPUT ;
    USE SIGNAL ;
    PORT
      LAYER M4 ;
        RECT  129.516 9.984 129.6 10.008 ;
    END
  END f_vm[138]
  PIN f_vm[139]
    DIRECTION INPUT ;
    USE SIGNAL ;
    PORT
      LAYER M4 ;
        RECT  129.516 10.032 129.6 10.056 ;
    END
  END f_vm[139]
  PIN f_vm[13]
    DIRECTION INPUT ;
    USE SIGNAL ;
    PORT
      LAYER M4 ;
        RECT  129.516 3.984 129.6 4.008 ;
    END
  END f_vm[13]
  PIN f_vm[140]
    DIRECTION INPUT ;
    USE SIGNAL ;
    PORT
      LAYER M4 ;
        RECT  129.516 10.08 129.6 10.104 ;
    END
  END f_vm[140]
  PIN f_vm[141]
    DIRECTION INPUT ;
    USE SIGNAL ;
    PORT
      LAYER M4 ;
        RECT  129.516 10.128 129.6 10.152 ;
    END
  END f_vm[141]
  PIN f_vm[142]
    DIRECTION INPUT ;
    USE SIGNAL ;
    PORT
      LAYER M4 ;
        RECT  129.516 10.176 129.6 10.2 ;
    END
  END f_vm[142]
  PIN f_vm[143]
    DIRECTION INPUT ;
    USE SIGNAL ;
    PORT
      LAYER M4 ;
        RECT  129.516 10.224 129.6 10.248 ;
    END
  END f_vm[143]
  PIN f_vm[144]
    DIRECTION INPUT ;
    USE SIGNAL ;
    PORT
      LAYER M4 ;
        RECT  129.516 10.272 129.6 10.296 ;
    END
  END f_vm[144]
  PIN f_vm[145]
    DIRECTION INPUT ;
    USE SIGNAL ;
    PORT
      LAYER M4 ;
        RECT  129.516 10.32 129.6 10.344 ;
    END
  END f_vm[145]
  PIN f_vm[146]
    DIRECTION INPUT ;
    USE SIGNAL ;
    PORT
      LAYER M4 ;
        RECT  129.516 10.368 129.6 10.392 ;
    END
  END f_vm[146]
  PIN f_vm[147]
    DIRECTION INPUT ;
    USE SIGNAL ;
    PORT
      LAYER M4 ;
        RECT  129.516 10.416 129.6 10.44 ;
    END
  END f_vm[147]
  PIN f_vm[148]
    DIRECTION INPUT ;
    USE SIGNAL ;
    PORT
      LAYER M4 ;
        RECT  129.516 10.464 129.6 10.488 ;
    END
  END f_vm[148]
  PIN f_vm[149]
    DIRECTION INPUT ;
    USE SIGNAL ;
    PORT
      LAYER M4 ;
        RECT  129.516 10.512 129.6 10.536 ;
    END
  END f_vm[149]
  PIN f_vm[14]
    DIRECTION INPUT ;
    USE SIGNAL ;
    PORT
      LAYER M4 ;
        RECT  129.516 4.032 129.6 4.056 ;
    END
  END f_vm[14]
  PIN f_vm[150]
    DIRECTION INPUT ;
    USE SIGNAL ;
    PORT
      LAYER M4 ;
        RECT  129.516 10.56 129.6 10.584 ;
    END
  END f_vm[150]
  PIN f_vm[151]
    DIRECTION INPUT ;
    USE SIGNAL ;
    PORT
      LAYER M4 ;
        RECT  129.516 10.608 129.6 10.632 ;
    END
  END f_vm[151]
  PIN f_vm[152]
    DIRECTION INPUT ;
    USE SIGNAL ;
    PORT
      LAYER M4 ;
        RECT  129.516 10.656 129.6 10.68 ;
    END
  END f_vm[152]
  PIN f_vm[153]
    DIRECTION INPUT ;
    USE SIGNAL ;
    PORT
      LAYER M4 ;
        RECT  129.516 10.704 129.6 10.728 ;
    END
  END f_vm[153]
  PIN f_vm[154]
    DIRECTION INPUT ;
    USE SIGNAL ;
    PORT
      LAYER M4 ;
        RECT  129.516 10.752 129.6 10.776 ;
    END
  END f_vm[154]
  PIN f_vm[155]
    DIRECTION INPUT ;
    USE SIGNAL ;
    PORT
      LAYER M4 ;
        RECT  129.516 10.8 129.6 10.824 ;
    END
  END f_vm[155]
  PIN f_vm[156]
    DIRECTION INPUT ;
    USE SIGNAL ;
    PORT
      LAYER M4 ;
        RECT  129.516 10.848 129.6 10.872 ;
    END
  END f_vm[156]
  PIN f_vm[157]
    DIRECTION INPUT ;
    USE SIGNAL ;
    PORT
      LAYER M4 ;
        RECT  129.516 10.896 129.6 10.92 ;
    END
  END f_vm[157]
  PIN f_vm[158]
    DIRECTION INPUT ;
    USE SIGNAL ;
    PORT
      LAYER M4 ;
        RECT  129.516 10.944 129.6 10.968 ;
    END
  END f_vm[158]
  PIN f_vm[159]
    DIRECTION INPUT ;
    USE SIGNAL ;
    PORT
      LAYER M4 ;
        RECT  129.516 10.992 129.6 11.016 ;
    END
  END f_vm[159]
  PIN f_vm[15]
    DIRECTION INPUT ;
    USE SIGNAL ;
    PORT
      LAYER M4 ;
        RECT  129.516 4.08 129.6 4.104 ;
    END
  END f_vm[15]
  PIN f_vm[16]
    DIRECTION INPUT ;
    USE SIGNAL ;
    PORT
      LAYER M4 ;
        RECT  129.516 4.128 129.6 4.152 ;
    END
  END f_vm[16]
  PIN f_vm[17]
    DIRECTION INPUT ;
    USE SIGNAL ;
    PORT
      LAYER M4 ;
        RECT  129.516 4.176 129.6 4.2 ;
    END
  END f_vm[17]
  PIN f_vm[18]
    DIRECTION INPUT ;
    USE SIGNAL ;
    PORT
      LAYER M4 ;
        RECT  129.516 4.224 129.6 4.248 ;
    END
  END f_vm[18]
  PIN f_vm[19]
    DIRECTION INPUT ;
    USE SIGNAL ;
    PORT
      LAYER M4 ;
        RECT  129.516 4.272 129.6 4.296 ;
    END
  END f_vm[19]
  PIN f_vm[1]
    DIRECTION INPUT ;
    USE SIGNAL ;
    PORT
      LAYER M4 ;
        RECT  129.516 3.408 129.6 3.432 ;
    END
  END f_vm[1]
  PIN f_vm[20]
    DIRECTION INPUT ;
    USE SIGNAL ;
    PORT
      LAYER M4 ;
        RECT  129.516 4.32 129.6 4.344 ;
    END
  END f_vm[20]
  PIN f_vm[21]
    DIRECTION INPUT ;
    USE SIGNAL ;
    PORT
      LAYER M4 ;
        RECT  129.516 4.368 129.6 4.392 ;
    END
  END f_vm[21]
  PIN f_vm[22]
    DIRECTION INPUT ;
    USE SIGNAL ;
    PORT
      LAYER M4 ;
        RECT  129.516 4.416 129.6 4.44 ;
    END
  END f_vm[22]
  PIN f_vm[23]
    DIRECTION INPUT ;
    USE SIGNAL ;
    PORT
      LAYER M4 ;
        RECT  129.516 4.464 129.6 4.488 ;
    END
  END f_vm[23]
  PIN f_vm[24]
    DIRECTION INPUT ;
    USE SIGNAL ;
    PORT
      LAYER M4 ;
        RECT  129.516 4.512 129.6 4.536 ;
    END
  END f_vm[24]
  PIN f_vm[25]
    DIRECTION INPUT ;
    USE SIGNAL ;
    PORT
      LAYER M4 ;
        RECT  129.516 4.56 129.6 4.584 ;
    END
  END f_vm[25]
  PIN f_vm[26]
    DIRECTION INPUT ;
    USE SIGNAL ;
    PORT
      LAYER M4 ;
        RECT  129.516 4.608 129.6 4.632 ;
    END
  END f_vm[26]
  PIN f_vm[27]
    DIRECTION INPUT ;
    USE SIGNAL ;
    PORT
      LAYER M4 ;
        RECT  129.516 4.656 129.6 4.68 ;
    END
  END f_vm[27]
  PIN f_vm[28]
    DIRECTION INPUT ;
    USE SIGNAL ;
    PORT
      LAYER M4 ;
        RECT  129.516 4.704 129.6 4.728 ;
    END
  END f_vm[28]
  PIN f_vm[29]
    DIRECTION INPUT ;
    USE SIGNAL ;
    PORT
      LAYER M4 ;
        RECT  129.516 4.752 129.6 4.776 ;
    END
  END f_vm[29]
  PIN f_vm[2]
    DIRECTION INPUT ;
    USE SIGNAL ;
    PORT
      LAYER M4 ;
        RECT  129.516 3.456 129.6 3.48 ;
    END
  END f_vm[2]
  PIN f_vm[30]
    DIRECTION INPUT ;
    USE SIGNAL ;
    PORT
      LAYER M4 ;
        RECT  129.516 4.8 129.6 4.824 ;
    END
  END f_vm[30]
  PIN f_vm[31]
    DIRECTION INPUT ;
    USE SIGNAL ;
    PORT
      LAYER M4 ;
        RECT  129.516 4.848 129.6 4.872 ;
    END
  END f_vm[31]
  PIN f_vm[32]
    DIRECTION INPUT ;
    USE SIGNAL ;
    PORT
      LAYER M4 ;
        RECT  129.516 4.896 129.6 4.92 ;
    END
  END f_vm[32]
  PIN f_vm[33]
    DIRECTION INPUT ;
    USE SIGNAL ;
    PORT
      LAYER M4 ;
        RECT  129.516 4.944 129.6 4.968 ;
    END
  END f_vm[33]
  PIN f_vm[34]
    DIRECTION INPUT ;
    USE SIGNAL ;
    PORT
      LAYER M4 ;
        RECT  129.516 4.992 129.6 5.016 ;
    END
  END f_vm[34]
  PIN f_vm[35]
    DIRECTION INPUT ;
    USE SIGNAL ;
    PORT
      LAYER M4 ;
        RECT  129.516 5.04 129.6 5.064 ;
    END
  END f_vm[35]
  PIN f_vm[36]
    DIRECTION INPUT ;
    USE SIGNAL ;
    PORT
      LAYER M4 ;
        RECT  129.516 5.088 129.6 5.112 ;
    END
  END f_vm[36]
  PIN f_vm[37]
    DIRECTION INPUT ;
    USE SIGNAL ;
    PORT
      LAYER M4 ;
        RECT  129.516 5.136 129.6 5.16 ;
    END
  END f_vm[37]
  PIN f_vm[38]
    DIRECTION INPUT ;
    USE SIGNAL ;
    PORT
      LAYER M4 ;
        RECT  129.516 5.184 129.6 5.208 ;
    END
  END f_vm[38]
  PIN f_vm[39]
    DIRECTION INPUT ;
    USE SIGNAL ;
    PORT
      LAYER M4 ;
        RECT  129.516 5.232 129.6 5.256 ;
    END
  END f_vm[39]
  PIN f_vm[3]
    DIRECTION INPUT ;
    USE SIGNAL ;
    PORT
      LAYER M4 ;
        RECT  129.516 3.504 129.6 3.528 ;
    END
  END f_vm[3]
  PIN f_vm[40]
    DIRECTION INPUT ;
    USE SIGNAL ;
    PORT
      LAYER M4 ;
        RECT  129.516 5.28 129.6 5.304 ;
    END
  END f_vm[40]
  PIN f_vm[41]
    DIRECTION INPUT ;
    USE SIGNAL ;
    PORT
      LAYER M4 ;
        RECT  129.516 5.328 129.6 5.352 ;
    END
  END f_vm[41]
  PIN f_vm[42]
    DIRECTION INPUT ;
    USE SIGNAL ;
    PORT
      LAYER M4 ;
        RECT  129.516 5.376 129.6 5.4 ;
    END
  END f_vm[42]
  PIN f_vm[43]
    DIRECTION INPUT ;
    USE SIGNAL ;
    PORT
      LAYER M4 ;
        RECT  129.516 5.424 129.6 5.448 ;
    END
  END f_vm[43]
  PIN f_vm[44]
    DIRECTION INPUT ;
    USE SIGNAL ;
    PORT
      LAYER M4 ;
        RECT  129.516 5.472 129.6 5.496 ;
    END
  END f_vm[44]
  PIN f_vm[45]
    DIRECTION INPUT ;
    USE SIGNAL ;
    PORT
      LAYER M4 ;
        RECT  129.516 5.52 129.6 5.544 ;
    END
  END f_vm[45]
  PIN f_vm[46]
    DIRECTION INPUT ;
    USE SIGNAL ;
    PORT
      LAYER M4 ;
        RECT  129.516 5.568 129.6 5.592 ;
    END
  END f_vm[46]
  PIN f_vm[47]
    DIRECTION INPUT ;
    USE SIGNAL ;
    PORT
      LAYER M4 ;
        RECT  129.516 5.616 129.6 5.64 ;
    END
  END f_vm[47]
  PIN f_vm[48]
    DIRECTION INPUT ;
    USE SIGNAL ;
    PORT
      LAYER M4 ;
        RECT  129.516 5.664 129.6 5.688 ;
    END
  END f_vm[48]
  PIN f_vm[49]
    DIRECTION INPUT ;
    USE SIGNAL ;
    PORT
      LAYER M4 ;
        RECT  129.516 5.712 129.6 5.736 ;
    END
  END f_vm[49]
  PIN f_vm[4]
    DIRECTION INPUT ;
    USE SIGNAL ;
    PORT
      LAYER M4 ;
        RECT  129.516 3.552 129.6 3.576 ;
    END
  END f_vm[4]
  PIN f_vm[50]
    DIRECTION INPUT ;
    USE SIGNAL ;
    PORT
      LAYER M4 ;
        RECT  129.516 5.76 129.6 5.784 ;
    END
  END f_vm[50]
  PIN f_vm[51]
    DIRECTION INPUT ;
    USE SIGNAL ;
    PORT
      LAYER M4 ;
        RECT  129.516 5.808 129.6 5.832 ;
    END
  END f_vm[51]
  PIN f_vm[52]
    DIRECTION INPUT ;
    USE SIGNAL ;
    PORT
      LAYER M4 ;
        RECT  129.516 5.856 129.6 5.88 ;
    END
  END f_vm[52]
  PIN f_vm[53]
    DIRECTION INPUT ;
    USE SIGNAL ;
    PORT
      LAYER M4 ;
        RECT  129.516 5.904 129.6 5.928 ;
    END
  END f_vm[53]
  PIN f_vm[54]
    DIRECTION INPUT ;
    USE SIGNAL ;
    PORT
      LAYER M4 ;
        RECT  129.516 5.952 129.6 5.976 ;
    END
  END f_vm[54]
  PIN f_vm[55]
    DIRECTION INPUT ;
    USE SIGNAL ;
    PORT
      LAYER M4 ;
        RECT  129.516 6 129.6 6.024 ;
    END
  END f_vm[55]
  PIN f_vm[56]
    DIRECTION INPUT ;
    USE SIGNAL ;
    PORT
      LAYER M4 ;
        RECT  129.516 6.048 129.6 6.072 ;
    END
  END f_vm[56]
  PIN f_vm[57]
    DIRECTION INPUT ;
    USE SIGNAL ;
    PORT
      LAYER M4 ;
        RECT  129.516 6.096 129.6 6.12 ;
    END
  END f_vm[57]
  PIN f_vm[58]
    DIRECTION INPUT ;
    USE SIGNAL ;
    PORT
      LAYER M4 ;
        RECT  129.516 6.144 129.6 6.168 ;
    END
  END f_vm[58]
  PIN f_vm[59]
    DIRECTION INPUT ;
    USE SIGNAL ;
    PORT
      LAYER M4 ;
        RECT  129.516 6.192 129.6 6.216 ;
    END
  END f_vm[59]
  PIN f_vm[5]
    DIRECTION INPUT ;
    USE SIGNAL ;
    PORT
      LAYER M4 ;
        RECT  129.516 3.6 129.6 3.624 ;
    END
  END f_vm[5]
  PIN f_vm[60]
    DIRECTION INPUT ;
    USE SIGNAL ;
    PORT
      LAYER M4 ;
        RECT  129.516 6.24 129.6 6.264 ;
    END
  END f_vm[60]
  PIN f_vm[61]
    DIRECTION INPUT ;
    USE SIGNAL ;
    PORT
      LAYER M4 ;
        RECT  129.516 6.288 129.6 6.312 ;
    END
  END f_vm[61]
  PIN f_vm[62]
    DIRECTION INPUT ;
    USE SIGNAL ;
    PORT
      LAYER M4 ;
        RECT  129.516 6.336 129.6 6.36 ;
    END
  END f_vm[62]
  PIN f_vm[63]
    DIRECTION INPUT ;
    USE SIGNAL ;
    PORT
      LAYER M4 ;
        RECT  129.516 6.384 129.6 6.408 ;
    END
  END f_vm[63]
  PIN f_vm[64]
    DIRECTION INPUT ;
    USE SIGNAL ;
    PORT
      LAYER M4 ;
        RECT  129.516 6.432 129.6 6.456 ;
    END
  END f_vm[64]
  PIN f_vm[65]
    DIRECTION INPUT ;
    USE SIGNAL ;
    PORT
      LAYER M4 ;
        RECT  129.516 6.48 129.6 6.504 ;
    END
  END f_vm[65]
  PIN f_vm[66]
    DIRECTION INPUT ;
    USE SIGNAL ;
    PORT
      LAYER M4 ;
        RECT  129.516 6.528 129.6 6.552 ;
    END
  END f_vm[66]
  PIN f_vm[67]
    DIRECTION INPUT ;
    USE SIGNAL ;
    PORT
      LAYER M4 ;
        RECT  129.516 6.576 129.6 6.6 ;
    END
  END f_vm[67]
  PIN f_vm[68]
    DIRECTION INPUT ;
    USE SIGNAL ;
    PORT
      LAYER M4 ;
        RECT  129.516 6.624 129.6 6.648 ;
    END
  END f_vm[68]
  PIN f_vm[69]
    DIRECTION INPUT ;
    USE SIGNAL ;
    PORT
      LAYER M4 ;
        RECT  129.516 6.672 129.6 6.696 ;
    END
  END f_vm[69]
  PIN f_vm[6]
    DIRECTION INPUT ;
    USE SIGNAL ;
    PORT
      LAYER M4 ;
        RECT  129.516 3.648 129.6 3.672 ;
    END
  END f_vm[6]
  PIN f_vm[70]
    DIRECTION INPUT ;
    USE SIGNAL ;
    PORT
      LAYER M4 ;
        RECT  129.516 6.72 129.6 6.744 ;
    END
  END f_vm[70]
  PIN f_vm[71]
    DIRECTION INPUT ;
    USE SIGNAL ;
    PORT
      LAYER M4 ;
        RECT  129.516 6.768 129.6 6.792 ;
    END
  END f_vm[71]
  PIN f_vm[72]
    DIRECTION INPUT ;
    USE SIGNAL ;
    PORT
      LAYER M4 ;
        RECT  129.516 6.816 129.6 6.84 ;
    END
  END f_vm[72]
  PIN f_vm[73]
    DIRECTION INPUT ;
    USE SIGNAL ;
    PORT
      LAYER M4 ;
        RECT  129.516 6.864 129.6 6.888 ;
    END
  END f_vm[73]
  PIN f_vm[74]
    DIRECTION INPUT ;
    USE SIGNAL ;
    PORT
      LAYER M4 ;
        RECT  129.516 6.912 129.6 6.936 ;
    END
  END f_vm[74]
  PIN f_vm[75]
    DIRECTION INPUT ;
    USE SIGNAL ;
    PORT
      LAYER M4 ;
        RECT  129.516 6.96 129.6 6.984 ;
    END
  END f_vm[75]
  PIN f_vm[76]
    DIRECTION INPUT ;
    USE SIGNAL ;
    PORT
      LAYER M4 ;
        RECT  129.516 7.008 129.6 7.032 ;
    END
  END f_vm[76]
  PIN f_vm[77]
    DIRECTION INPUT ;
    USE SIGNAL ;
    PORT
      LAYER M4 ;
        RECT  129.516 7.056 129.6 7.08 ;
    END
  END f_vm[77]
  PIN f_vm[78]
    DIRECTION INPUT ;
    USE SIGNAL ;
    PORT
      LAYER M4 ;
        RECT  129.516 7.104 129.6 7.128 ;
    END
  END f_vm[78]
  PIN f_vm[79]
    DIRECTION INPUT ;
    USE SIGNAL ;
    PORT
      LAYER M4 ;
        RECT  129.516 7.152 129.6 7.176 ;
    END
  END f_vm[79]
  PIN f_vm[7]
    DIRECTION INPUT ;
    USE SIGNAL ;
    PORT
      LAYER M4 ;
        RECT  129.516 3.696 129.6 3.72 ;
    END
  END f_vm[7]
  PIN f_vm[80]
    DIRECTION INPUT ;
    USE SIGNAL ;
    PORT
      LAYER M4 ;
        RECT  129.516 7.2 129.6 7.224 ;
    END
  END f_vm[80]
  PIN f_vm[81]
    DIRECTION INPUT ;
    USE SIGNAL ;
    PORT
      LAYER M4 ;
        RECT  129.516 7.248 129.6 7.272 ;
    END
  END f_vm[81]
  PIN f_vm[82]
    DIRECTION INPUT ;
    USE SIGNAL ;
    PORT
      LAYER M4 ;
        RECT  129.516 7.296 129.6 7.32 ;
    END
  END f_vm[82]
  PIN f_vm[83]
    DIRECTION INPUT ;
    USE SIGNAL ;
    PORT
      LAYER M4 ;
        RECT  129.516 7.344 129.6 7.368 ;
    END
  END f_vm[83]
  PIN f_vm[84]
    DIRECTION INPUT ;
    USE SIGNAL ;
    PORT
      LAYER M4 ;
        RECT  129.516 7.392 129.6 7.416 ;
    END
  END f_vm[84]
  PIN f_vm[85]
    DIRECTION INPUT ;
    USE SIGNAL ;
    PORT
      LAYER M4 ;
        RECT  129.516 7.44 129.6 7.464 ;
    END
  END f_vm[85]
  PIN f_vm[86]
    DIRECTION INPUT ;
    USE SIGNAL ;
    PORT
      LAYER M4 ;
        RECT  129.516 7.488 129.6 7.512 ;
    END
  END f_vm[86]
  PIN f_vm[87]
    DIRECTION INPUT ;
    USE SIGNAL ;
    PORT
      LAYER M4 ;
        RECT  129.516 7.536 129.6 7.56 ;
    END
  END f_vm[87]
  PIN f_vm[88]
    DIRECTION INPUT ;
    USE SIGNAL ;
    PORT
      LAYER M4 ;
        RECT  129.516 7.584 129.6 7.608 ;
    END
  END f_vm[88]
  PIN f_vm[89]
    DIRECTION INPUT ;
    USE SIGNAL ;
    PORT
      LAYER M4 ;
        RECT  129.516 7.632 129.6 7.656 ;
    END
  END f_vm[89]
  PIN f_vm[8]
    DIRECTION INPUT ;
    USE SIGNAL ;
    PORT
      LAYER M4 ;
        RECT  129.516 3.744 129.6 3.768 ;
    END
  END f_vm[8]
  PIN f_vm[90]
    DIRECTION INPUT ;
    USE SIGNAL ;
    PORT
      LAYER M4 ;
        RECT  129.516 7.68 129.6 7.704 ;
    END
  END f_vm[90]
  PIN f_vm[91]
    DIRECTION INPUT ;
    USE SIGNAL ;
    PORT
      LAYER M4 ;
        RECT  129.516 7.728 129.6 7.752 ;
    END
  END f_vm[91]
  PIN f_vm[92]
    DIRECTION INPUT ;
    USE SIGNAL ;
    PORT
      LAYER M4 ;
        RECT  129.516 7.776 129.6 7.8 ;
    END
  END f_vm[92]
  PIN f_vm[93]
    DIRECTION INPUT ;
    USE SIGNAL ;
    PORT
      LAYER M4 ;
        RECT  129.516 7.824 129.6 7.848 ;
    END
  END f_vm[93]
  PIN f_vm[94]
    DIRECTION INPUT ;
    USE SIGNAL ;
    PORT
      LAYER M4 ;
        RECT  129.516 7.872 129.6 7.896 ;
    END
  END f_vm[94]
  PIN f_vm[95]
    DIRECTION INPUT ;
    USE SIGNAL ;
    PORT
      LAYER M4 ;
        RECT  129.516 7.92 129.6 7.944 ;
    END
  END f_vm[95]
  PIN f_vm[96]
    DIRECTION INPUT ;
    USE SIGNAL ;
    PORT
      LAYER M4 ;
        RECT  129.516 7.968 129.6 7.992 ;
    END
  END f_vm[96]
  PIN f_vm[97]
    DIRECTION INPUT ;
    USE SIGNAL ;
    PORT
      LAYER M4 ;
        RECT  129.516 8.016 129.6 8.04 ;
    END
  END f_vm[97]
  PIN f_vm[98]
    DIRECTION INPUT ;
    USE SIGNAL ;
    PORT
      LAYER M4 ;
        RECT  129.516 8.064 129.6 8.088 ;
    END
  END f_vm[98]
  PIN f_vm[99]
    DIRECTION INPUT ;
    USE SIGNAL ;
    PORT
      LAYER M4 ;
        RECT  129.516 8.112 129.6 8.136 ;
    END
  END f_vm[99]
  PIN f_vm[9]
    DIRECTION INPUT ;
    USE SIGNAL ;
    PORT
      LAYER M4 ;
        RECT  129.516 3.792 129.6 3.816 ;
    END
  END f_vm[9]
  PIN rc[0]
    DIRECTION OUTPUT ;
    USE SIGNAL ;
    PORT
      LAYER M5 ;
        RECT  51.552 43.116 51.576 43.2 ;
    END
  END rc[0]
  PIN rc[1]
    DIRECTION OUTPUT ;
    USE SIGNAL ;
    PORT
      LAYER M5 ;
        RECT  51.648 43.116 51.672 43.2 ;
    END
  END rc[1]
  PIN rc[2]
    DIRECTION OUTPUT ;
    USE SIGNAL ;
    PORT
      LAYER M5 ;
        RECT  51.744 43.116 51.768 43.2 ;
    END
  END rc[2]
  PIN rc[3]
    DIRECTION OUTPUT ;
    USE SIGNAL ;
    PORT
      LAYER M5 ;
        RECT  51.84 43.116 51.864 43.2 ;
    END
  END rc[3]
  PIN rc[4]
    DIRECTION OUTPUT ;
    USE SIGNAL ;
    PORT
      LAYER M5 ;
        RECT  51.936 43.116 51.96 43.2 ;
    END
  END rc[4]
  PIN rc[5]
    DIRECTION OUTPUT ;
    USE SIGNAL ;
    PORT
      LAYER M5 ;
        RECT  52.032 43.116 52.056 43.2 ;
    END
  END rc[5]
  PIN rc[6]
    DIRECTION OUTPUT ;
    USE SIGNAL ;
    PORT
      LAYER M5 ;
        RECT  52.128 43.116 52.152 43.2 ;
    END
  END rc[6]
  PIN rc[7]
    DIRECTION OUTPUT ;
    USE SIGNAL ;
    PORT
      LAYER M5 ;
        RECT  52.224 43.116 52.248 43.2 ;
    END
  END rc[7]
  PIN roots_ready[0]
    DIRECTION INPUT ;
    USE SIGNAL ;
    PORT
      LAYER M5 ;
        RECT  53.472 43.116 53.496 43.2 ;
    END
  END roots_ready[0]
  PIN roots_ready[1]
    DIRECTION INPUT ;
    USE SIGNAL ;
    PORT
      LAYER M5 ;
        RECT  53.568 43.116 53.592 43.2 ;
    END
  END roots_ready[1]
  PIN roots_ready[2]
    DIRECTION INPUT ;
    USE SIGNAL ;
    PORT
      LAYER M5 ;
        RECT  53.664 43.116 53.688 43.2 ;
    END
  END roots_ready[2]
  PIN roots_ready[3]
    DIRECTION INPUT ;
    USE SIGNAL ;
    PORT
      LAYER M5 ;
        RECT  53.76 43.116 53.784 43.2 ;
    END
  END roots_ready[3]
  PIN roots_ready[4]
    DIRECTION INPUT ;
    USE SIGNAL ;
    PORT
      LAYER M5 ;
        RECT  53.856 43.116 53.88 43.2 ;
    END
  END roots_ready[4]
  PIN roots_ready[5]
    DIRECTION INPUT ;
    USE SIGNAL ;
    PORT
      LAYER M5 ;
        RECT  53.952 43.116 53.976 43.2 ;
    END
  END roots_ready[5]
  PIN roots_ready[6]
    DIRECTION INPUT ;
    USE SIGNAL ;
    PORT
      LAYER M5 ;
        RECT  54.048 43.116 54.072 43.2 ;
    END
  END roots_ready[6]
  PIN roots_ready[7]
    DIRECTION INPUT ;
    USE SIGNAL ;
    PORT
      LAYER M5 ;
        RECT  54.144 43.116 54.168 43.2 ;
    END
  END roots_ready[7]
  PIN rst
    DIRECTION INPUT ;
    USE SIGNAL ;
    PORT
      LAYER M4 ;
        RECT  0 3.456 0.084 3.48 ;
    END
  END rst
  PIN rsv
    DIRECTION INPUT ;
    USE SIGNAL ;
    PORT
      LAYER M4 ;
        RECT  0 3.648 0.084 3.672 ;
    END
  END rsv
  PIN t_xgo[0]
    DIRECTION OUTPUT ;
    USE SIGNAL ;
    PORT
      LAYER M4 ;
        RECT  129.516 32.544 129.6 32.568 ;
    END
  END t_xgo[0]
  PIN t_xgo[10]
    DIRECTION OUTPUT ;
    USE SIGNAL ;
    PORT
      LAYER M4 ;
        RECT  129.516 33.024 129.6 33.048 ;
    END
  END t_xgo[10]
  PIN t_xgo[1]
    DIRECTION OUTPUT ;
    USE SIGNAL ;
    PORT
      LAYER M4 ;
        RECT  129.516 32.592 129.6 32.616 ;
    END
  END t_xgo[1]
  PIN t_xgo[2]
    DIRECTION OUTPUT ;
    USE SIGNAL ;
    PORT
      LAYER M4 ;
        RECT  129.516 32.64 129.6 32.664 ;
    END
  END t_xgo[2]
  PIN t_xgo[3]
    DIRECTION OUTPUT ;
    USE SIGNAL ;
    PORT
      LAYER M4 ;
        RECT  129.516 32.688 129.6 32.712 ;
    END
  END t_xgo[3]
  PIN t_xgo[4]
    DIRECTION OUTPUT ;
    USE SIGNAL ;
    PORT
      LAYER M4 ;
        RECT  129.516 32.736 129.6 32.76 ;
    END
  END t_xgo[4]
  PIN t_xgo[5]
    DIRECTION OUTPUT ;
    USE SIGNAL ;
    PORT
      LAYER M4 ;
        RECT  129.516 32.784 129.6 32.808 ;
    END
  END t_xgo[5]
  PIN t_xgo[6]
    DIRECTION OUTPUT ;
    USE SIGNAL ;
    PORT
      LAYER M4 ;
        RECT  129.516 32.832 129.6 32.856 ;
    END
  END t_xgo[6]
  PIN t_xgo[7]
    DIRECTION OUTPUT ;
    USE SIGNAL ;
    PORT
      LAYER M4 ;
        RECT  129.516 32.88 129.6 32.904 ;
    END
  END t_xgo[7]
  PIN t_xgo[8]
    DIRECTION OUTPUT ;
    USE SIGNAL ;
    PORT
      LAYER M4 ;
        RECT  129.516 32.928 129.6 32.952 ;
    END
  END t_xgo[8]
  PIN t_xgo[9]
    DIRECTION OUTPUT ;
    USE SIGNAL ;
    PORT
      LAYER M4 ;
        RECT  129.516 32.976 129.6 33 ;
    END
  END t_xgo[9]
  PIN tc[0]
    DIRECTION OUTPUT ;
    USE SIGNAL ;
    PORT
      LAYER M5 ;
        RECT  12.096 0 12.12 0.084 ;
    END
  END tc[0]
  PIN tc[100]
    DIRECTION OUTPUT ;
    USE SIGNAL ;
    PORT
      LAYER M5 ;
        RECT  21.696 0 21.72 0.084 ;
    END
  END tc[100]
  PIN tc[101]
    DIRECTION OUTPUT ;
    USE SIGNAL ;
    PORT
      LAYER M5 ;
        RECT  21.792 0 21.816 0.084 ;
    END
  END tc[101]
  PIN tc[102]
    DIRECTION OUTPUT ;
    USE SIGNAL ;
    PORT
      LAYER M5 ;
        RECT  21.888 0 21.912 0.084 ;
    END
  END tc[102]
  PIN tc[103]
    DIRECTION OUTPUT ;
    USE SIGNAL ;
    PORT
      LAYER M5 ;
        RECT  21.984 0 22.008 0.084 ;
    END
  END tc[103]
  PIN tc[104]
    DIRECTION OUTPUT ;
    USE SIGNAL ;
    PORT
      LAYER M5 ;
        RECT  22.08 0 22.104 0.084 ;
    END
  END tc[104]
  PIN tc[105]
    DIRECTION OUTPUT ;
    USE SIGNAL ;
    PORT
      LAYER M5 ;
        RECT  22.176 0 22.2 0.084 ;
    END
  END tc[105]
  PIN tc[106]
    DIRECTION OUTPUT ;
    USE SIGNAL ;
    PORT
      LAYER M5 ;
        RECT  22.272 0 22.296 0.084 ;
    END
  END tc[106]
  PIN tc[107]
    DIRECTION OUTPUT ;
    USE SIGNAL ;
    PORT
      LAYER M5 ;
        RECT  22.368 0 22.392 0.084 ;
    END
  END tc[107]
  PIN tc[108]
    DIRECTION OUTPUT ;
    USE SIGNAL ;
    PORT
      LAYER M5 ;
        RECT  22.464 0 22.488 0.084 ;
    END
  END tc[108]
  PIN tc[109]
    DIRECTION OUTPUT ;
    USE SIGNAL ;
    PORT
      LAYER M5 ;
        RECT  22.56 0 22.584 0.084 ;
    END
  END tc[109]
  PIN tc[10]
    DIRECTION OUTPUT ;
    USE SIGNAL ;
    PORT
      LAYER M5 ;
        RECT  13.056 0 13.08 0.084 ;
    END
  END tc[10]
  PIN tc[110]
    DIRECTION OUTPUT ;
    USE SIGNAL ;
    PORT
      LAYER M5 ;
        RECT  22.656 0 22.68 0.084 ;
    END
  END tc[110]
  PIN tc[111]
    DIRECTION OUTPUT ;
    USE SIGNAL ;
    PORT
      LAYER M5 ;
        RECT  22.752 0 22.776 0.084 ;
    END
  END tc[111]
  PIN tc[112]
    DIRECTION OUTPUT ;
    USE SIGNAL ;
    PORT
      LAYER M5 ;
        RECT  22.848 0 22.872 0.084 ;
    END
  END tc[112]
  PIN tc[113]
    DIRECTION OUTPUT ;
    USE SIGNAL ;
    PORT
      LAYER M5 ;
        RECT  22.944 0 22.968 0.084 ;
    END
  END tc[113]
  PIN tc[114]
    DIRECTION OUTPUT ;
    USE SIGNAL ;
    PORT
      LAYER M5 ;
        RECT  23.04 0 23.064 0.084 ;
    END
  END tc[114]
  PIN tc[115]
    DIRECTION OUTPUT ;
    USE SIGNAL ;
    PORT
      LAYER M5 ;
        RECT  23.136 0 23.16 0.084 ;
    END
  END tc[115]
  PIN tc[116]
    DIRECTION OUTPUT ;
    USE SIGNAL ;
    PORT
      LAYER M5 ;
        RECT  23.232 0 23.256 0.084 ;
    END
  END tc[116]
  PIN tc[117]
    DIRECTION OUTPUT ;
    USE SIGNAL ;
    PORT
      LAYER M5 ;
        RECT  23.328 0 23.352 0.084 ;
    END
  END tc[117]
  PIN tc[118]
    DIRECTION OUTPUT ;
    USE SIGNAL ;
    PORT
      LAYER M5 ;
        RECT  23.424 0 23.448 0.084 ;
    END
  END tc[118]
  PIN tc[119]
    DIRECTION OUTPUT ;
    USE SIGNAL ;
    PORT
      LAYER M5 ;
        RECT  23.52 0 23.544 0.084 ;
    END
  END tc[119]
  PIN tc[11]
    DIRECTION OUTPUT ;
    USE SIGNAL ;
    PORT
      LAYER M5 ;
        RECT  13.152 0 13.176 0.084 ;
    END
  END tc[11]
  PIN tc[120]
    DIRECTION OUTPUT ;
    USE SIGNAL ;
    PORT
      LAYER M5 ;
        RECT  23.616 0 23.64 0.084 ;
    END
  END tc[120]
  PIN tc[121]
    DIRECTION OUTPUT ;
    USE SIGNAL ;
    PORT
      LAYER M5 ;
        RECT  23.712 0 23.736 0.084 ;
    END
  END tc[121]
  PIN tc[122]
    DIRECTION OUTPUT ;
    USE SIGNAL ;
    PORT
      LAYER M5 ;
        RECT  23.808 0 23.832 0.084 ;
    END
  END tc[122]
  PIN tc[123]
    DIRECTION OUTPUT ;
    USE SIGNAL ;
    PORT
      LAYER M5 ;
        RECT  23.904 0 23.928 0.084 ;
    END
  END tc[123]
  PIN tc[124]
    DIRECTION OUTPUT ;
    USE SIGNAL ;
    PORT
      LAYER M5 ;
        RECT  24 0 24.024 0.084 ;
    END
  END tc[124]
  PIN tc[125]
    DIRECTION OUTPUT ;
    USE SIGNAL ;
    PORT
      LAYER M5 ;
        RECT  24.096 0 24.12 0.084 ;
    END
  END tc[125]
  PIN tc[126]
    DIRECTION OUTPUT ;
    USE SIGNAL ;
    PORT
      LAYER M5 ;
        RECT  24.192 0 24.216 0.084 ;
    END
  END tc[126]
  PIN tc[127]
    DIRECTION OUTPUT ;
    USE SIGNAL ;
    PORT
      LAYER M5 ;
        RECT  24.288 0 24.312 0.084 ;
    END
  END tc[127]
  PIN tc[128]
    DIRECTION OUTPUT ;
    USE SIGNAL ;
    PORT
      LAYER M5 ;
        RECT  24.384 0 24.408 0.084 ;
    END
  END tc[128]
  PIN tc[129]
    DIRECTION OUTPUT ;
    USE SIGNAL ;
    PORT
      LAYER M5 ;
        RECT  24.48 0 24.504 0.084 ;
    END
  END tc[129]
  PIN tc[12]
    DIRECTION OUTPUT ;
    USE SIGNAL ;
    PORT
      LAYER M5 ;
        RECT  13.248 0 13.272 0.084 ;
    END
  END tc[12]
  PIN tc[130]
    DIRECTION OUTPUT ;
    USE SIGNAL ;
    PORT
      LAYER M5 ;
        RECT  24.576 0 24.6 0.084 ;
    END
  END tc[130]
  PIN tc[131]
    DIRECTION OUTPUT ;
    USE SIGNAL ;
    PORT
      LAYER M5 ;
        RECT  24.672 0 24.696 0.084 ;
    END
  END tc[131]
  PIN tc[132]
    DIRECTION OUTPUT ;
    USE SIGNAL ;
    PORT
      LAYER M5 ;
        RECT  24.768 0 24.792 0.084 ;
    END
  END tc[132]
  PIN tc[133]
    DIRECTION OUTPUT ;
    USE SIGNAL ;
    PORT
      LAYER M5 ;
        RECT  24.864 0 24.888 0.084 ;
    END
  END tc[133]
  PIN tc[134]
    DIRECTION OUTPUT ;
    USE SIGNAL ;
    PORT
      LAYER M5 ;
        RECT  24.96 0 24.984 0.084 ;
    END
  END tc[134]
  PIN tc[135]
    DIRECTION OUTPUT ;
    USE SIGNAL ;
    PORT
      LAYER M5 ;
        RECT  25.056 0 25.08 0.084 ;
    END
  END tc[135]
  PIN tc[136]
    DIRECTION OUTPUT ;
    USE SIGNAL ;
    PORT
      LAYER M5 ;
        RECT  25.152 0 25.176 0.084 ;
    END
  END tc[136]
  PIN tc[137]
    DIRECTION OUTPUT ;
    USE SIGNAL ;
    PORT
      LAYER M5 ;
        RECT  25.248 0 25.272 0.084 ;
    END
  END tc[137]
  PIN tc[138]
    DIRECTION OUTPUT ;
    USE SIGNAL ;
    PORT
      LAYER M5 ;
        RECT  25.344 0 25.368 0.084 ;
    END
  END tc[138]
  PIN tc[139]
    DIRECTION OUTPUT ;
    USE SIGNAL ;
    PORT
      LAYER M5 ;
        RECT  25.44 0 25.464 0.084 ;
    END
  END tc[139]
  PIN tc[13]
    DIRECTION OUTPUT ;
    USE SIGNAL ;
    PORT
      LAYER M5 ;
        RECT  13.344 0 13.368 0.084 ;
    END
  END tc[13]
  PIN tc[140]
    DIRECTION OUTPUT ;
    USE SIGNAL ;
    PORT
      LAYER M5 ;
        RECT  25.536 0 25.56 0.084 ;
    END
  END tc[140]
  PIN tc[141]
    DIRECTION OUTPUT ;
    USE SIGNAL ;
    PORT
      LAYER M5 ;
        RECT  25.632 0 25.656 0.084 ;
    END
  END tc[141]
  PIN tc[142]
    DIRECTION OUTPUT ;
    USE SIGNAL ;
    PORT
      LAYER M5 ;
        RECT  25.728 0 25.752 0.084 ;
    END
  END tc[142]
  PIN tc[143]
    DIRECTION OUTPUT ;
    USE SIGNAL ;
    PORT
      LAYER M5 ;
        RECT  25.824 0 25.848 0.084 ;
    END
  END tc[143]
  PIN tc[144]
    DIRECTION OUTPUT ;
    USE SIGNAL ;
    PORT
      LAYER M5 ;
        RECT  25.92 0 25.944 0.084 ;
    END
  END tc[144]
  PIN tc[145]
    DIRECTION OUTPUT ;
    USE SIGNAL ;
    PORT
      LAYER M5 ;
        RECT  26.016 0 26.04 0.084 ;
    END
  END tc[145]
  PIN tc[146]
    DIRECTION OUTPUT ;
    USE SIGNAL ;
    PORT
      LAYER M5 ;
        RECT  26.112 0 26.136 0.084 ;
    END
  END tc[146]
  PIN tc[147]
    DIRECTION OUTPUT ;
    USE SIGNAL ;
    PORT
      LAYER M5 ;
        RECT  26.208 0 26.232 0.084 ;
    END
  END tc[147]
  PIN tc[148]
    DIRECTION OUTPUT ;
    USE SIGNAL ;
    PORT
      LAYER M5 ;
        RECT  26.304 0 26.328 0.084 ;
    END
  END tc[148]
  PIN tc[149]
    DIRECTION OUTPUT ;
    USE SIGNAL ;
    PORT
      LAYER M5 ;
        RECT  26.4 0 26.424 0.084 ;
    END
  END tc[149]
  PIN tc[14]
    DIRECTION OUTPUT ;
    USE SIGNAL ;
    PORT
      LAYER M5 ;
        RECT  13.44 0 13.464 0.084 ;
    END
  END tc[14]
  PIN tc[150]
    DIRECTION OUTPUT ;
    USE SIGNAL ;
    PORT
      LAYER M5 ;
        RECT  26.496 0 26.52 0.084 ;
    END
  END tc[150]
  PIN tc[151]
    DIRECTION OUTPUT ;
    USE SIGNAL ;
    PORT
      LAYER M5 ;
        RECT  26.592 0 26.616 0.084 ;
    END
  END tc[151]
  PIN tc[152]
    DIRECTION OUTPUT ;
    USE SIGNAL ;
    PORT
      LAYER M5 ;
        RECT  26.688 0 26.712 0.084 ;
    END
  END tc[152]
  PIN tc[153]
    DIRECTION OUTPUT ;
    USE SIGNAL ;
    PORT
      LAYER M5 ;
        RECT  26.784 0 26.808 0.084 ;
    END
  END tc[153]
  PIN tc[154]
    DIRECTION OUTPUT ;
    USE SIGNAL ;
    PORT
      LAYER M5 ;
        RECT  26.88 0 26.904 0.084 ;
    END
  END tc[154]
  PIN tc[155]
    DIRECTION OUTPUT ;
    USE SIGNAL ;
    PORT
      LAYER M5 ;
        RECT  26.976 0 27 0.084 ;
    END
  END tc[155]
  PIN tc[156]
    DIRECTION OUTPUT ;
    USE SIGNAL ;
    PORT
      LAYER M5 ;
        RECT  27.072 0 27.096 0.084 ;
    END
  END tc[156]
  PIN tc[157]
    DIRECTION OUTPUT ;
    USE SIGNAL ;
    PORT
      LAYER M5 ;
        RECT  27.168 0 27.192 0.084 ;
    END
  END tc[157]
  PIN tc[158]
    DIRECTION OUTPUT ;
    USE SIGNAL ;
    PORT
      LAYER M5 ;
        RECT  27.264 0 27.288 0.084 ;
    END
  END tc[158]
  PIN tc[159]
    DIRECTION OUTPUT ;
    USE SIGNAL ;
    PORT
      LAYER M5 ;
        RECT  27.36 0 27.384 0.084 ;
    END
  END tc[159]
  PIN tc[15]
    DIRECTION OUTPUT ;
    USE SIGNAL ;
    PORT
      LAYER M5 ;
        RECT  13.536 0 13.56 0.084 ;
    END
  END tc[15]
  PIN tc[160]
    DIRECTION OUTPUT ;
    USE SIGNAL ;
    PORT
      LAYER M5 ;
        RECT  27.456 0 27.48 0.084 ;
    END
  END tc[160]
  PIN tc[161]
    DIRECTION OUTPUT ;
    USE SIGNAL ;
    PORT
      LAYER M5 ;
        RECT  27.552 0 27.576 0.084 ;
    END
  END tc[161]
  PIN tc[162]
    DIRECTION OUTPUT ;
    USE SIGNAL ;
    PORT
      LAYER M5 ;
        RECT  27.648 0 27.672 0.084 ;
    END
  END tc[162]
  PIN tc[16]
    DIRECTION OUTPUT ;
    USE SIGNAL ;
    PORT
      LAYER M5 ;
        RECT  13.632 0 13.656 0.084 ;
    END
  END tc[16]
  PIN tc[17]
    DIRECTION OUTPUT ;
    USE SIGNAL ;
    PORT
      LAYER M5 ;
        RECT  13.728 0 13.752 0.084 ;
    END
  END tc[17]
  PIN tc[18]
    DIRECTION OUTPUT ;
    USE SIGNAL ;
    PORT
      LAYER M5 ;
        RECT  13.824 0 13.848 0.084 ;
    END
  END tc[18]
  PIN tc[19]
    DIRECTION OUTPUT ;
    USE SIGNAL ;
    PORT
      LAYER M5 ;
        RECT  13.92 0 13.944 0.084 ;
    END
  END tc[19]
  PIN tc[1]
    DIRECTION OUTPUT ;
    USE SIGNAL ;
    PORT
      LAYER M5 ;
        RECT  12.192 0 12.216 0.084 ;
    END
  END tc[1]
  PIN tc[20]
    DIRECTION OUTPUT ;
    USE SIGNAL ;
    PORT
      LAYER M5 ;
        RECT  14.016 0 14.04 0.084 ;
    END
  END tc[20]
  PIN tc[21]
    DIRECTION OUTPUT ;
    USE SIGNAL ;
    PORT
      LAYER M5 ;
        RECT  14.112 0 14.136 0.084 ;
    END
  END tc[21]
  PIN tc[22]
    DIRECTION OUTPUT ;
    USE SIGNAL ;
    PORT
      LAYER M5 ;
        RECT  14.208 0 14.232 0.084 ;
    END
  END tc[22]
  PIN tc[23]
    DIRECTION OUTPUT ;
    USE SIGNAL ;
    PORT
      LAYER M5 ;
        RECT  14.304 0 14.328 0.084 ;
    END
  END tc[23]
  PIN tc[24]
    DIRECTION OUTPUT ;
    USE SIGNAL ;
    PORT
      LAYER M5 ;
        RECT  14.4 0 14.424 0.084 ;
    END
  END tc[24]
  PIN tc[25]
    DIRECTION OUTPUT ;
    USE SIGNAL ;
    PORT
      LAYER M5 ;
        RECT  14.496 0 14.52 0.084 ;
    END
  END tc[25]
  PIN tc[26]
    DIRECTION OUTPUT ;
    USE SIGNAL ;
    PORT
      LAYER M5 ;
        RECT  14.592 0 14.616 0.084 ;
    END
  END tc[26]
  PIN tc[27]
    DIRECTION OUTPUT ;
    USE SIGNAL ;
    PORT
      LAYER M5 ;
        RECT  14.688 0 14.712 0.084 ;
    END
  END tc[27]
  PIN tc[28]
    DIRECTION OUTPUT ;
    USE SIGNAL ;
    PORT
      LAYER M5 ;
        RECT  14.784 0 14.808 0.084 ;
    END
  END tc[28]
  PIN tc[29]
    DIRECTION OUTPUT ;
    USE SIGNAL ;
    PORT
      LAYER M5 ;
        RECT  14.88 0 14.904 0.084 ;
    END
  END tc[29]
  PIN tc[2]
    DIRECTION OUTPUT ;
    USE SIGNAL ;
    PORT
      LAYER M5 ;
        RECT  12.288 0 12.312 0.084 ;
    END
  END tc[2]
  PIN tc[30]
    DIRECTION OUTPUT ;
    USE SIGNAL ;
    PORT
      LAYER M5 ;
        RECT  14.976 0 15 0.084 ;
    END
  END tc[30]
  PIN tc[31]
    DIRECTION OUTPUT ;
    USE SIGNAL ;
    PORT
      LAYER M5 ;
        RECT  15.072 0 15.096 0.084 ;
    END
  END tc[31]
  PIN tc[32]
    DIRECTION OUTPUT ;
    USE SIGNAL ;
    PORT
      LAYER M5 ;
        RECT  15.168 0 15.192 0.084 ;
    END
  END tc[32]
  PIN tc[33]
    DIRECTION OUTPUT ;
    USE SIGNAL ;
    PORT
      LAYER M5 ;
        RECT  15.264 0 15.288 0.084 ;
    END
  END tc[33]
  PIN tc[34]
    DIRECTION OUTPUT ;
    USE SIGNAL ;
    PORT
      LAYER M5 ;
        RECT  15.36 0 15.384 0.084 ;
    END
  END tc[34]
  PIN tc[35]
    DIRECTION OUTPUT ;
    USE SIGNAL ;
    PORT
      LAYER M5 ;
        RECT  15.456 0 15.48 0.084 ;
    END
  END tc[35]
  PIN tc[36]
    DIRECTION OUTPUT ;
    USE SIGNAL ;
    PORT
      LAYER M5 ;
        RECT  15.552 0 15.576 0.084 ;
    END
  END tc[36]
  PIN tc[37]
    DIRECTION OUTPUT ;
    USE SIGNAL ;
    PORT
      LAYER M5 ;
        RECT  15.648 0 15.672 0.084 ;
    END
  END tc[37]
  PIN tc[38]
    DIRECTION OUTPUT ;
    USE SIGNAL ;
    PORT
      LAYER M5 ;
        RECT  15.744 0 15.768 0.084 ;
    END
  END tc[38]
  PIN tc[39]
    DIRECTION OUTPUT ;
    USE SIGNAL ;
    PORT
      LAYER M5 ;
        RECT  15.84 0 15.864 0.084 ;
    END
  END tc[39]
  PIN tc[3]
    DIRECTION OUTPUT ;
    USE SIGNAL ;
    PORT
      LAYER M5 ;
        RECT  12.384 0 12.408 0.084 ;
    END
  END tc[3]
  PIN tc[40]
    DIRECTION OUTPUT ;
    USE SIGNAL ;
    PORT
      LAYER M5 ;
        RECT  15.936 0 15.96 0.084 ;
    END
  END tc[40]
  PIN tc[41]
    DIRECTION OUTPUT ;
    USE SIGNAL ;
    PORT
      LAYER M5 ;
        RECT  16.032 0 16.056 0.084 ;
    END
  END tc[41]
  PIN tc[42]
    DIRECTION OUTPUT ;
    USE SIGNAL ;
    PORT
      LAYER M5 ;
        RECT  16.128 0 16.152 0.084 ;
    END
  END tc[42]
  PIN tc[43]
    DIRECTION OUTPUT ;
    USE SIGNAL ;
    PORT
      LAYER M5 ;
        RECT  16.224 0 16.248 0.084 ;
    END
  END tc[43]
  PIN tc[44]
    DIRECTION OUTPUT ;
    USE SIGNAL ;
    PORT
      LAYER M5 ;
        RECT  16.32 0 16.344 0.084 ;
    END
  END tc[44]
  PIN tc[45]
    DIRECTION OUTPUT ;
    USE SIGNAL ;
    PORT
      LAYER M5 ;
        RECT  16.416 0 16.44 0.084 ;
    END
  END tc[45]
  PIN tc[46]
    DIRECTION OUTPUT ;
    USE SIGNAL ;
    PORT
      LAYER M5 ;
        RECT  16.512 0 16.536 0.084 ;
    END
  END tc[46]
  PIN tc[47]
    DIRECTION OUTPUT ;
    USE SIGNAL ;
    PORT
      LAYER M5 ;
        RECT  16.608 0 16.632 0.084 ;
    END
  END tc[47]
  PIN tc[48]
    DIRECTION OUTPUT ;
    USE SIGNAL ;
    PORT
      LAYER M5 ;
        RECT  16.704 0 16.728 0.084 ;
    END
  END tc[48]
  PIN tc[49]
    DIRECTION OUTPUT ;
    USE SIGNAL ;
    PORT
      LAYER M5 ;
        RECT  16.8 0 16.824 0.084 ;
    END
  END tc[49]
  PIN tc[4]
    DIRECTION OUTPUT ;
    USE SIGNAL ;
    PORT
      LAYER M5 ;
        RECT  12.48 0 12.504 0.084 ;
    END
  END tc[4]
  PIN tc[50]
    DIRECTION OUTPUT ;
    USE SIGNAL ;
    PORT
      LAYER M5 ;
        RECT  16.896 0 16.92 0.084 ;
    END
  END tc[50]
  PIN tc[51]
    DIRECTION OUTPUT ;
    USE SIGNAL ;
    PORT
      LAYER M5 ;
        RECT  16.992 0 17.016 0.084 ;
    END
  END tc[51]
  PIN tc[52]
    DIRECTION OUTPUT ;
    USE SIGNAL ;
    PORT
      LAYER M5 ;
        RECT  17.088 0 17.112 0.084 ;
    END
  END tc[52]
  PIN tc[53]
    DIRECTION OUTPUT ;
    USE SIGNAL ;
    PORT
      LAYER M5 ;
        RECT  17.184 0 17.208 0.084 ;
    END
  END tc[53]
  PIN tc[54]
    DIRECTION OUTPUT ;
    USE SIGNAL ;
    PORT
      LAYER M5 ;
        RECT  17.28 0 17.304 0.084 ;
    END
  END tc[54]
  PIN tc[55]
    DIRECTION OUTPUT ;
    USE SIGNAL ;
    PORT
      LAYER M5 ;
        RECT  17.376 0 17.4 0.084 ;
    END
  END tc[55]
  PIN tc[56]
    DIRECTION OUTPUT ;
    USE SIGNAL ;
    PORT
      LAYER M5 ;
        RECT  17.472 0 17.496 0.084 ;
    END
  END tc[56]
  PIN tc[57]
    DIRECTION OUTPUT ;
    USE SIGNAL ;
    PORT
      LAYER M5 ;
        RECT  17.568 0 17.592 0.084 ;
    END
  END tc[57]
  PIN tc[58]
    DIRECTION OUTPUT ;
    USE SIGNAL ;
    PORT
      LAYER M5 ;
        RECT  17.664 0 17.688 0.084 ;
    END
  END tc[58]
  PIN tc[59]
    DIRECTION OUTPUT ;
    USE SIGNAL ;
    PORT
      LAYER M5 ;
        RECT  17.76 0 17.784 0.084 ;
    END
  END tc[59]
  PIN tc[5]
    DIRECTION OUTPUT ;
    USE SIGNAL ;
    PORT
      LAYER M5 ;
        RECT  12.576 0 12.6 0.084 ;
    END
  END tc[5]
  PIN tc[60]
    DIRECTION OUTPUT ;
    USE SIGNAL ;
    PORT
      LAYER M5 ;
        RECT  17.856 0 17.88 0.084 ;
    END
  END tc[60]
  PIN tc[61]
    DIRECTION OUTPUT ;
    USE SIGNAL ;
    PORT
      LAYER M5 ;
        RECT  17.952 0 17.976 0.084 ;
    END
  END tc[61]
  PIN tc[62]
    DIRECTION OUTPUT ;
    USE SIGNAL ;
    PORT
      LAYER M5 ;
        RECT  18.048 0 18.072 0.084 ;
    END
  END tc[62]
  PIN tc[63]
    DIRECTION OUTPUT ;
    USE SIGNAL ;
    PORT
      LAYER M5 ;
        RECT  18.144 0 18.168 0.084 ;
    END
  END tc[63]
  PIN tc[64]
    DIRECTION OUTPUT ;
    USE SIGNAL ;
    PORT
      LAYER M5 ;
        RECT  18.24 0 18.264 0.084 ;
    END
  END tc[64]
  PIN tc[65]
    DIRECTION OUTPUT ;
    USE SIGNAL ;
    PORT
      LAYER M5 ;
        RECT  18.336 0 18.36 0.084 ;
    END
  END tc[65]
  PIN tc[66]
    DIRECTION OUTPUT ;
    USE SIGNAL ;
    PORT
      LAYER M5 ;
        RECT  18.432 0 18.456 0.084 ;
    END
  END tc[66]
  PIN tc[67]
    DIRECTION OUTPUT ;
    USE SIGNAL ;
    PORT
      LAYER M5 ;
        RECT  18.528 0 18.552 0.084 ;
    END
  END tc[67]
  PIN tc[68]
    DIRECTION OUTPUT ;
    USE SIGNAL ;
    PORT
      LAYER M5 ;
        RECT  18.624 0 18.648 0.084 ;
    END
  END tc[68]
  PIN tc[69]
    DIRECTION OUTPUT ;
    USE SIGNAL ;
    PORT
      LAYER M5 ;
        RECT  18.72 0 18.744 0.084 ;
    END
  END tc[69]
  PIN tc[6]
    DIRECTION OUTPUT ;
    USE SIGNAL ;
    PORT
      LAYER M5 ;
        RECT  12.672 0 12.696 0.084 ;
    END
  END tc[6]
  PIN tc[70]
    DIRECTION OUTPUT ;
    USE SIGNAL ;
    PORT
      LAYER M5 ;
        RECT  18.816 0 18.84 0.084 ;
    END
  END tc[70]
  PIN tc[71]
    DIRECTION OUTPUT ;
    USE SIGNAL ;
    PORT
      LAYER M5 ;
        RECT  18.912 0 18.936 0.084 ;
    END
  END tc[71]
  PIN tc[72]
    DIRECTION OUTPUT ;
    USE SIGNAL ;
    PORT
      LAYER M5 ;
        RECT  19.008 0 19.032 0.084 ;
    END
  END tc[72]
  PIN tc[73]
    DIRECTION OUTPUT ;
    USE SIGNAL ;
    PORT
      LAYER M5 ;
        RECT  19.104 0 19.128 0.084 ;
    END
  END tc[73]
  PIN tc[74]
    DIRECTION OUTPUT ;
    USE SIGNAL ;
    PORT
      LAYER M5 ;
        RECT  19.2 0 19.224 0.084 ;
    END
  END tc[74]
  PIN tc[75]
    DIRECTION OUTPUT ;
    USE SIGNAL ;
    PORT
      LAYER M5 ;
        RECT  19.296 0 19.32 0.084 ;
    END
  END tc[75]
  PIN tc[76]
    DIRECTION OUTPUT ;
    USE SIGNAL ;
    PORT
      LAYER M5 ;
        RECT  19.392 0 19.416 0.084 ;
    END
  END tc[76]
  PIN tc[77]
    DIRECTION OUTPUT ;
    USE SIGNAL ;
    PORT
      LAYER M5 ;
        RECT  19.488 0 19.512 0.084 ;
    END
  END tc[77]
  PIN tc[78]
    DIRECTION OUTPUT ;
    USE SIGNAL ;
    PORT
      LAYER M5 ;
        RECT  19.584 0 19.608 0.084 ;
    END
  END tc[78]
  PIN tc[79]
    DIRECTION OUTPUT ;
    USE SIGNAL ;
    PORT
      LAYER M5 ;
        RECT  19.68 0 19.704 0.084 ;
    END
  END tc[79]
  PIN tc[7]
    DIRECTION OUTPUT ;
    USE SIGNAL ;
    PORT
      LAYER M5 ;
        RECT  12.768 0 12.792 0.084 ;
    END
  END tc[7]
  PIN tc[80]
    DIRECTION OUTPUT ;
    USE SIGNAL ;
    PORT
      LAYER M5 ;
        RECT  19.776 0 19.8 0.084 ;
    END
  END tc[80]
  PIN tc[81]
    DIRECTION OUTPUT ;
    USE SIGNAL ;
    PORT
      LAYER M5 ;
        RECT  19.872 0 19.896 0.084 ;
    END
  END tc[81]
  PIN tc[82]
    DIRECTION OUTPUT ;
    USE SIGNAL ;
    PORT
      LAYER M5 ;
        RECT  19.968 0 19.992 0.084 ;
    END
  END tc[82]
  PIN tc[83]
    DIRECTION OUTPUT ;
    USE SIGNAL ;
    PORT
      LAYER M5 ;
        RECT  20.064 0 20.088 0.084 ;
    END
  END tc[83]
  PIN tc[84]
    DIRECTION OUTPUT ;
    USE SIGNAL ;
    PORT
      LAYER M5 ;
        RECT  20.16 0 20.184 0.084 ;
    END
  END tc[84]
  PIN tc[85]
    DIRECTION OUTPUT ;
    USE SIGNAL ;
    PORT
      LAYER M5 ;
        RECT  20.256 0 20.28 0.084 ;
    END
  END tc[85]
  PIN tc[86]
    DIRECTION OUTPUT ;
    USE SIGNAL ;
    PORT
      LAYER M5 ;
        RECT  20.352 0 20.376 0.084 ;
    END
  END tc[86]
  PIN tc[87]
    DIRECTION OUTPUT ;
    USE SIGNAL ;
    PORT
      LAYER M5 ;
        RECT  20.448 0 20.472 0.084 ;
    END
  END tc[87]
  PIN tc[88]
    DIRECTION OUTPUT ;
    USE SIGNAL ;
    PORT
      LAYER M5 ;
        RECT  20.544 0 20.568 0.084 ;
    END
  END tc[88]
  PIN tc[89]
    DIRECTION OUTPUT ;
    USE SIGNAL ;
    PORT
      LAYER M5 ;
        RECT  20.64 0 20.664 0.084 ;
    END
  END tc[89]
  PIN tc[8]
    DIRECTION OUTPUT ;
    USE SIGNAL ;
    PORT
      LAYER M5 ;
        RECT  12.864 0 12.888 0.084 ;
    END
  END tc[8]
  PIN tc[90]
    DIRECTION OUTPUT ;
    USE SIGNAL ;
    PORT
      LAYER M5 ;
        RECT  20.736 0 20.76 0.084 ;
    END
  END tc[90]
  PIN tc[91]
    DIRECTION OUTPUT ;
    USE SIGNAL ;
    PORT
      LAYER M5 ;
        RECT  20.832 0 20.856 0.084 ;
    END
  END tc[91]
  PIN tc[92]
    DIRECTION OUTPUT ;
    USE SIGNAL ;
    PORT
      LAYER M5 ;
        RECT  20.928 0 20.952 0.084 ;
    END
  END tc[92]
  PIN tc[93]
    DIRECTION OUTPUT ;
    USE SIGNAL ;
    PORT
      LAYER M5 ;
        RECT  21.024 0 21.048 0.084 ;
    END
  END tc[93]
  PIN tc[94]
    DIRECTION OUTPUT ;
    USE SIGNAL ;
    PORT
      LAYER M5 ;
        RECT  21.12 0 21.144 0.084 ;
    END
  END tc[94]
  PIN tc[95]
    DIRECTION OUTPUT ;
    USE SIGNAL ;
    PORT
      LAYER M5 ;
        RECT  21.216 0 21.24 0.084 ;
    END
  END tc[95]
  PIN tc[96]
    DIRECTION OUTPUT ;
    USE SIGNAL ;
    PORT
      LAYER M5 ;
        RECT  21.312 0 21.336 0.084 ;
    END
  END tc[96]
  PIN tc[97]
    DIRECTION OUTPUT ;
    USE SIGNAL ;
    PORT
      LAYER M5 ;
        RECT  21.408 0 21.432 0.084 ;
    END
  END tc[97]
  PIN tc[98]
    DIRECTION OUTPUT ;
    USE SIGNAL ;
    PORT
      LAYER M5 ;
        RECT  21.504 0 21.528 0.084 ;
    END
  END tc[98]
  PIN tc[99]
    DIRECTION OUTPUT ;
    USE SIGNAL ;
    PORT
      LAYER M5 ;
        RECT  21.6 0 21.624 0.084 ;
    END
  END tc[99]
  PIN tc[9]
    DIRECTION OUTPUT ;
    USE SIGNAL ;
    PORT
      LAYER M5 ;
        RECT  12.96 0 12.984 0.084 ;
    END
  END tc[9]
  PIN tst[0]
    DIRECTION INPUT ;
    USE SIGNAL ;
    PORT
      LAYER M5 ;
        RECT  42.144 43.116 42.168 43.2 ;
    END
  END tst[0]
  PIN tst[10]
    DIRECTION INPUT ;
    USE SIGNAL ;
    PORT
      LAYER M5 ;
        RECT  43.104 43.116 43.128 43.2 ;
    END
  END tst[10]
  PIN tst[11]
    DIRECTION INPUT ;
    USE SIGNAL ;
    PORT
      LAYER M5 ;
        RECT  43.2 43.116 43.224 43.2 ;
    END
  END tst[11]
  PIN tst[12]
    DIRECTION INPUT ;
    USE SIGNAL ;
    PORT
      LAYER M5 ;
        RECT  43.296 43.116 43.32 43.2 ;
    END
  END tst[12]
  PIN tst[13]
    DIRECTION INPUT ;
    USE SIGNAL ;
    PORT
      LAYER M5 ;
        RECT  43.392 43.116 43.416 43.2 ;
    END
  END tst[13]
  PIN tst[14]
    DIRECTION INPUT ;
    USE SIGNAL ;
    PORT
      LAYER M5 ;
        RECT  43.488 43.116 43.512 43.2 ;
    END
  END tst[14]
  PIN tst[15]
    DIRECTION INPUT ;
    USE SIGNAL ;
    PORT
      LAYER M5 ;
        RECT  43.584 43.116 43.608 43.2 ;
    END
  END tst[15]
  PIN tst[16]
    DIRECTION INPUT ;
    USE SIGNAL ;
    PORT
      LAYER M5 ;
        RECT  43.68 43.116 43.704 43.2 ;
    END
  END tst[16]
  PIN tst[17]
    DIRECTION INPUT ;
    USE SIGNAL ;
    PORT
      LAYER M5 ;
        RECT  43.776 43.116 43.8 43.2 ;
    END
  END tst[17]
  PIN tst[18]
    DIRECTION INPUT ;
    USE SIGNAL ;
    PORT
      LAYER M5 ;
        RECT  43.872 43.116 43.896 43.2 ;
    END
  END tst[18]
  PIN tst[19]
    DIRECTION INPUT ;
    USE SIGNAL ;
    PORT
      LAYER M5 ;
        RECT  43.968 43.116 43.992 43.2 ;
    END
  END tst[19]
  PIN tst[1]
    DIRECTION INPUT ;
    USE SIGNAL ;
    PORT
      LAYER M5 ;
        RECT  42.24 43.116 42.264 43.2 ;
    END
  END tst[1]
  PIN tst[20]
    DIRECTION INPUT ;
    USE SIGNAL ;
    PORT
      LAYER M5 ;
        RECT  44.064 43.116 44.088 43.2 ;
    END
  END tst[20]
  PIN tst[21]
    DIRECTION INPUT ;
    USE SIGNAL ;
    PORT
      LAYER M5 ;
        RECT  44.16 43.116 44.184 43.2 ;
    END
  END tst[21]
  PIN tst[22]
    DIRECTION INPUT ;
    USE SIGNAL ;
    PORT
      LAYER M5 ;
        RECT  44.256 43.116 44.28 43.2 ;
    END
  END tst[22]
  PIN tst[23]
    DIRECTION INPUT ;
    USE SIGNAL ;
    PORT
      LAYER M5 ;
        RECT  44.352 43.116 44.376 43.2 ;
    END
  END tst[23]
  PIN tst[2]
    DIRECTION INPUT ;
    USE SIGNAL ;
    PORT
      LAYER M5 ;
        RECT  42.336 43.116 42.36 43.2 ;
    END
  END tst[2]
  PIN tst[3]
    DIRECTION INPUT ;
    USE SIGNAL ;
    PORT
      LAYER M5 ;
        RECT  42.432 43.116 42.456 43.2 ;
    END
  END tst[3]
  PIN tst[4]
    DIRECTION INPUT ;
    USE SIGNAL ;
    PORT
      LAYER M5 ;
        RECT  42.528 43.116 42.552 43.2 ;
    END
  END tst[4]
  PIN tst[5]
    DIRECTION INPUT ;
    USE SIGNAL ;
    PORT
      LAYER M5 ;
        RECT  42.624 43.116 42.648 43.2 ;
    END
  END tst[5]
  PIN tst[6]
    DIRECTION INPUT ;
    USE SIGNAL ;
    PORT
      LAYER M5 ;
        RECT  42.72 43.116 42.744 43.2 ;
    END
  END tst[6]
  PIN tst[7]
    DIRECTION INPUT ;
    USE SIGNAL ;
    PORT
      LAYER M5 ;
        RECT  42.816 43.116 42.84 43.2 ;
    END
  END tst[7]
  PIN tst[8]
    DIRECTION INPUT ;
    USE SIGNAL ;
    PORT
      LAYER M5 ;
        RECT  42.912 43.116 42.936 43.2 ;
    END
  END tst[8]
  PIN tst[9]
    DIRECTION INPUT ;
    USE SIGNAL ;
    PORT
      LAYER M5 ;
        RECT  43.008 43.116 43.032 43.2 ;
    END
  END tst[9]
  PIN VDD
    DIRECTION INOUT ;
    USE POWER ;
    PORT
      LAYER M5 ;
        RECT  126.792 2.151 126.912 41.049 ;
        RECT  121.392 2.151 121.512 41.049 ;
        RECT  115.992 2.151 116.112 41.049 ;
        RECT  110.592 2.151 110.712 41.049 ;
        RECT  105.192 2.151 105.312 41.049 ;
        RECT  99.792 2.151 99.912 41.049 ;
        RECT  94.392 2.151 94.512 41.049 ;
        RECT  88.992 2.151 89.112 41.049 ;
        RECT  83.592 2.151 83.712 41.049 ;
        RECT  78.192 2.151 78.312 41.049 ;
        RECT  72.792 2.151 72.912 41.049 ;
        RECT  67.392 2.151 67.512 41.049 ;
        RECT  61.992 2.151 62.112 41.049 ;
        RECT  56.592 2.151 56.712 41.049 ;
        RECT  51.192 2.151 51.312 41.049 ;
        RECT  45.792 2.151 45.912 41.049 ;
        RECT  40.392 2.151 40.512 41.049 ;
        RECT  34.992 2.151 35.112 41.049 ;
        RECT  29.592 2.151 29.712 41.049 ;
        RECT  24.192 2.151 24.312 41.049 ;
        RECT  18.792 2.151 18.912 41.049 ;
        RECT  13.392 2.151 13.512 41.049 ;
        RECT  7.992 2.151 8.112 41.049 ;
        RECT  2.592 2.151 2.712 41.049 ;
    END
  END VDD
  PIN VSS
    DIRECTION INOUT ;
    USE GROUND ;
    PORT
      LAYER M5 ;
        RECT  126.6 2.137 126.72 41.063 ;
        RECT  121.2 2.137 121.32 41.063 ;
        RECT  115.8 2.137 115.92 41.063 ;
        RECT  110.4 2.137 110.52 41.063 ;
        RECT  105 2.137 105.12 41.063 ;
        RECT  99.6 2.137 99.72 41.063 ;
        RECT  94.2 2.137 94.32 41.063 ;
        RECT  88.8 2.137 88.92 41.063 ;
        RECT  83.4 2.137 83.52 41.063 ;
        RECT  78 2.137 78.12 41.063 ;
        RECT  72.6 2.137 72.72 41.063 ;
        RECT  67.2 2.137 67.32 41.063 ;
        RECT  61.8 2.137 61.92 41.063 ;
        RECT  56.4 2.137 56.52 41.063 ;
        RECT  51 2.137 51.12 41.063 ;
        RECT  45.6 2.137 45.72 41.063 ;
        RECT  40.2 2.137 40.32 41.063 ;
        RECT  34.8 2.137 34.92 41.063 ;
        RECT  29.4 2.137 29.52 41.063 ;
        RECT  24 2.137 24.12 41.063 ;
        RECT  18.6 2.137 18.72 41.063 ;
        RECT  13.2 2.137 13.32 41.063 ;
        RECT  7.8 2.137 7.92 41.063 ;
        RECT  2.4 2.137 2.52 41.063 ;
    END
  END VSS
  # OT_OBS_CLOSED layer=M5 d_um=1.536 added=756
  OBS
    LAYER RVTN ;
     RECT  2.16 2.16 127.44 2.295 ;
     RECT  2.16 2.565 127.44 2.835 ;
     RECT  2.16 3.105 127.44 3.375 ;
     RECT  2.16 3.645 127.44 3.915 ;
     RECT  2.16 4.185 127.44 4.455 ;
     RECT  2.16 4.725 127.44 4.995 ;
     RECT  2.16 5.265 127.44 5.535 ;
     RECT  2.16 5.805 127.44 6.075 ;
     RECT  2.16 6.345 127.44 6.615 ;
     RECT  2.16 6.885 127.44 7.155 ;
     RECT  2.16 7.425 127.44 7.695 ;
     RECT  2.16 7.965 127.44 8.235 ;
     RECT  2.16 8.505 127.44 8.775 ;
     RECT  2.16 9.045 127.44 9.315 ;
     RECT  2.16 9.585 127.44 9.855 ;
     RECT  2.16 10.125 127.44 10.395 ;
     RECT  2.16 10.665 127.44 10.935 ;
     RECT  2.16 11.205 127.44 11.475 ;
     RECT  2.16 11.745 127.44 12.015 ;
     RECT  2.16 12.285 127.44 12.555 ;
     RECT  2.16 12.825 127.44 13.095 ;
     RECT  2.16 13.365 127.44 13.635 ;
     RECT  2.16 13.905 127.44 14.175 ;
     RECT  2.16 14.445 127.44 14.715 ;
     RECT  2.16 14.985 127.44 15.255 ;
     RECT  2.16 15.525 127.44 15.795 ;
     RECT  2.16 16.065 127.44 16.335 ;
     RECT  2.16 16.605 127.44 16.875 ;
     RECT  2.16 17.145 127.44 17.415 ;
     RECT  2.16 17.685 127.44 17.955 ;
     RECT  2.16 18.225 127.44 18.495 ;
     RECT  2.16 18.765 127.44 19.035 ;
     RECT  2.16 19.305 127.44 19.575 ;
     RECT  2.16 19.845 127.44 20.115 ;
     RECT  2.16 20.385 127.44 20.655 ;
     RECT  2.16 20.925 127.44 21.195 ;
     RECT  2.16 21.465 127.44 21.735 ;
     RECT  2.16 22.005 127.44 22.275 ;
     RECT  2.16 22.545 127.44 22.815 ;
     RECT  2.16 23.085 127.44 23.355 ;
     RECT  2.16 23.625 127.44 23.895 ;
     RECT  2.16 24.165 127.44 24.435 ;
     RECT  2.16 24.705 127.44 24.975 ;
     RECT  2.16 25.245 127.44 25.515 ;
     RECT  2.16 25.785 127.44 26.055 ;
     RECT  2.16 26.325 127.44 26.595 ;
     RECT  2.16 26.865 127.44 27.135 ;
     RECT  2.16 27.405 127.44 27.675 ;
     RECT  2.16 27.945 127.44 28.215 ;
     RECT  2.16 28.485 127.44 28.755 ;
     RECT  2.16 29.025 127.44 29.295 ;
     RECT  2.16 29.565 127.44 29.835 ;
     RECT  2.16 30.105 127.44 30.375 ;
     RECT  2.16 30.645 127.44 30.915 ;
     RECT  2.16 31.185 127.44 31.455 ;
     RECT  2.16 31.725 127.44 31.995 ;
     RECT  2.16 32.265 127.44 32.535 ;
     RECT  2.16 32.805 127.44 33.075 ;
     RECT  2.16 33.345 127.44 33.615 ;
     RECT  2.16 33.885 127.44 34.155 ;
     RECT  2.16 34.425 127.44 34.695 ;
     RECT  2.16 34.965 127.44 35.235 ;
     RECT  2.16 35.505 127.44 35.775 ;
     RECT  2.16 36.045 127.44 36.315 ;
     RECT  2.16 36.585 127.44 36.855 ;
     RECT  2.16 37.125 127.44 37.395 ;
     RECT  2.16 37.665 127.44 37.935 ;
     RECT  2.16 38.205 127.44 38.475 ;
     RECT  2.16 38.745 127.44 39.015 ;
     RECT  2.16 39.285 127.44 39.555 ;
     RECT  2.16 39.825 127.44 40.095 ;
     RECT  2.16 40.365 127.44 40.635 ;
     RECT  2.16 40.905 127.44 41.04 ;
    LAYER RVTP ;
     RECT  2.16 2.295 127.44 2.565 ;
     RECT  2.16 2.835 127.44 3.105 ;
     RECT  2.16 3.375 127.44 3.645 ;
     RECT  2.16 3.915 127.44 4.185 ;
     RECT  2.16 4.455 127.44 4.725 ;
     RECT  2.16 4.995 127.44 5.265 ;
     RECT  2.16 5.535 127.44 5.805 ;
     RECT  2.16 6.075 127.44 6.345 ;
     RECT  2.16 6.615 127.44 6.885 ;
     RECT  2.16 7.155 127.44 7.425 ;
     RECT  2.16 7.695 127.44 7.965 ;
     RECT  2.16 8.235 127.44 8.505 ;
     RECT  2.16 8.775 127.44 9.045 ;
     RECT  2.16 9.315 127.44 9.585 ;
     RECT  2.16 9.855 127.44 10.125 ;
     RECT  2.16 10.395 127.44 10.665 ;
     RECT  2.16 10.935 127.44 11.205 ;
     RECT  2.16 11.475 127.44 11.745 ;
     RECT  2.16 12.015 127.44 12.285 ;
     RECT  2.16 12.555 127.44 12.825 ;
     RECT  2.16 13.095 127.44 13.365 ;
     RECT  2.16 13.635 127.44 13.905 ;
     RECT  2.16 14.175 127.44 14.445 ;
     RECT  2.16 14.715 127.44 14.985 ;
     RECT  2.16 15.255 127.44 15.525 ;
     RECT  2.16 15.795 127.44 16.065 ;
     RECT  2.16 16.335 127.44 16.605 ;
     RECT  2.16 16.875 127.44 17.145 ;
     RECT  2.16 17.415 127.44 17.685 ;
     RECT  2.16 17.955 127.44 18.225 ;
     RECT  2.16 18.495 127.44 18.765 ;
     RECT  2.16 19.035 127.44 19.305 ;
     RECT  2.16 19.575 127.44 19.845 ;
     RECT  2.16 20.115 127.44 20.385 ;
     RECT  2.16 20.655 127.44 20.925 ;
     RECT  2.16 21.195 127.44 21.465 ;
     RECT  2.16 21.735 127.44 22.005 ;
     RECT  2.16 22.275 127.44 22.545 ;
     RECT  2.16 22.815 127.44 23.085 ;
     RECT  2.16 23.355 127.44 23.625 ;
     RECT  2.16 23.895 127.44 24.165 ;
     RECT  2.16 24.435 127.44 24.705 ;
     RECT  2.16 24.975 127.44 25.245 ;
     RECT  2.16 25.515 127.44 25.785 ;
     RECT  2.16 26.055 127.44 26.325 ;
     RECT  2.16 26.595 127.44 26.865 ;
     RECT  2.16 27.135 127.44 27.405 ;
     RECT  2.16 27.675 127.44 27.945 ;
     RECT  2.16 28.215 127.44 28.485 ;
     RECT  2.16 28.755 127.44 29.025 ;
     RECT  2.16 29.295 127.44 29.565 ;
     RECT  2.16 29.835 127.44 30.105 ;
     RECT  2.16 30.375 127.44 30.645 ;
     RECT  2.16 30.915 127.44 31.185 ;
     RECT  2.16 31.455 127.44 31.725 ;
     RECT  2.16 31.995 127.44 32.265 ;
     RECT  2.16 32.535 127.44 32.805 ;
     RECT  2.16 33.075 127.44 33.345 ;
     RECT  2.16 33.615 127.44 33.885 ;
     RECT  2.16 34.155 127.44 34.425 ;
     RECT  2.16 34.695 127.44 34.965 ;
     RECT  2.16 35.235 127.44 35.505 ;
     RECT  2.16 35.775 127.44 36.045 ;
     RECT  2.16 36.315 127.44 36.585 ;
     RECT  2.16 36.855 127.44 37.125 ;
     RECT  2.16 37.395 127.44 37.665 ;
     RECT  2.16 37.935 127.44 38.205 ;
     RECT  2.16 38.475 127.44 38.745 ;
     RECT  2.16 39.015 127.44 39.285 ;
     RECT  2.16 39.555 127.44 39.825 ;
     RECT  2.16 40.095 127.44 40.365 ;
     RECT  2.16 40.635 127.44 40.905 ;
    LAYER M1 ;
     RECT  2.16 2.151 127.44 41.049 ;
    LAYER M2 ;
     RECT  2.16 2.151 13.639 41.049 ;
     RECT  13.855 1.152 14.287 1.17 ;
     RECT  14.287 1.152 14.459 1.242 ;
     RECT  14.459 1.152 15.143 1.17 ;
     RECT  13.639 2.106 15.323 41.049 ;
     RECT  16.195 1.152 16.439 1.17 ;
     RECT  16.627 1.188 16.907 1.206 ;
     RECT  22.423 1.152 22.523 1.17 ;
     RECT  23.755 1.152 23.855 1.17 ;
     RECT  15.323 2.151 24.439 41.049 ;
     RECT  24.439 1.764 24.575 41.049 ;
     RECT  24.575 2.034 25.871 41.049 ;
     RECT  25.871 2.106 26.159 41.049 ;
     RECT  26.159 2.151 29.767 41.049 ;
     RECT  29.767 2.106 30.659 41.049 ;
     RECT  30.659 2.151 33.835 41.049 ;
     RECT  33.835 2.106 41.935 41.049 ;
     RECT  41.935 1.962 112.639 41.049 ;
     RECT  112.639 1.881 115.699 41.049 ;
     RECT  115.699 1.836 126.275 41.049 ;
     RECT  126.275 1.998 126.779 41.049 ;
     RECT  126.779 2.034 127.247 41.049 ;
     RECT  127.247 2.151 127.44 41.049 ;
     RECT  127.44 2.268 127.499 15.444 ;
     RECT  127.44 16.308 127.535 17.064 ;
     RECT  127.44 35.136 127.643 35.154 ;
     RECT  127.44 30.114 127.715 34.074 ;
     RECT  127.499 2.268 127.895 15.246 ;
     RECT  127.535 16.308 127.967 16.398 ;
     RECT  127.895 2.268 128.075 14.778 ;
     RECT  128.075 2.268 128.147 14.742 ;
     RECT  127.44 28.188 128.255 29.016 ;
     RECT  127.715 30.114 128.255 30.708 ;
     RECT  127.44 26.37 128.327 27.126 ;
     RECT  127.715 31.734 128.327 34.074 ;
     RECT  127.967 16.308 128.471 16.326 ;
     RECT  127.44 17.928 128.543 17.946 ;
     RECT  128.255 28.728 128.723 29.016 ;
     RECT  128.147 2.268 128.759 14.436 ;
     RECT  128.327 26.37 128.831 26.856 ;
     RECT  128.723 28.728 128.831 28.854 ;
     RECT  128.327 31.896 128.831 34.074 ;
     RECT  128.759 2.268 128.867 5.094 ;
     RECT  128.759 5.85 129.191 14.436 ;
     RECT  129.191 13.068 129.227 14.436 ;
     RECT  129.191 5.85 129.299 11.97 ;
     RECT  129.299 5.85 129.335 11.574 ;
     RECT  128.831 33.516 129.335 34.074 ;
     RECT  128.867 2.268 129.371 5.058 ;
     RECT  129.335 5.85 129.371 7.218 ;
     RECT  129.335 8.244 129.371 11.304 ;
     RECT  128.831 28.836 129.371 28.854 ;
     RECT  128.831 31.896 129.371 32.76 ;
     RECT  129.371 2.268 129.407 3.402 ;
     RECT  129.371 5.85 129.407 6.759 ;
     RECT  129.227 13.68 129.407 14.436 ;
     RECT  129.335 33.516 129.407 33.534 ;
     RECT  129.371 4.356 129.443 5.058 ;
     RECT  129.407 6.39 129.443 6.759 ;
     RECT  129.371 8.244 129.443 10.926 ;
     RECT  129.407 14.418 129.443 14.436 ;
     RECT  128.255 30.654 129.443 30.708 ;
     RECT  129.371 32.04 129.443 32.76 ;
     RECT  127.44 36.216 129.443 36.234 ;
     RECT  129.407 2.268 129.515 2.862 ;
     RECT  129.443 8.856 129.515 9.108 ;
     RECT  129.443 9.981 129.515 9.999 ;
     RECT  128.831 26.37 129.515 26.82 ;
     RECT  129.443 30.69 129.515 30.708 ;
     RECT  129.443 32.04 129.515 32.058 ;
     RECT  129.515 8.946 129.551 8.964 ;
     RECT  129.443 10.908 129.551 10.926 ;
     RECT  129.515 2.268 129.587 2.286 ;
     RECT  129.443 4.356 129.587 4.374 ;
     RECT  127.44 25.56 129.587 25.578 ;
     RECT  129.307 28.026 129.587 28.044 ;
    LAYER M3 ;
     RECT  11.952 0.091 12.654 0.139 ;
     RECT  13.716 0.091 13.734 0.139 ;
     RECT  14.472 0.091 14.814 0.139 ;
     RECT  15.768 0.091 16.434 0.139 ;
     RECT  19.62 0.091 19.638 0.235 ;
     RECT  27.252 0.091 27.27 0.235 ;
     RECT  19.44 0.235 19.638 0.283 ;
     RECT  11.952 0.139 12.87 0.523 ;
     RECT  13.716 0.139 16.434 0.523 ;
     RECT  20.736 0.235 20.754 0.523 ;
     RECT  23.652 0.091 23.67 0.523 ;
     RECT  24.444 0.091 24.462 0.523 ;
     RECT  25.488 0.091 25.506 0.571 ;
     RECT  29.988 0.523 30.546 0.571 ;
     RECT  22.5 0.523 22.518 0.619 ;
     RECT  23.652 0.523 24.462 0.619 ;
     RECT  11.952 0.523 16.434 1.099 ;
     RECT  17.856 0.091 18.414 1.099 ;
     RECT  19.44 0.283 19.71 1.099 ;
     RECT  11.952 1.099 16.902 1.147 ;
     RECT  17.856 1.099 19.71 1.147 ;
     RECT  20.736 0.523 20.898 1.147 ;
     RECT  22.5 0.619 24.462 1.147 ;
     RECT  25.488 0.571 25.542 1.147 ;
     RECT  11.952 1.147 16.974 1.675 ;
     RECT  26.496 1.147 26.514 1.675 ;
     RECT  11.952 1.675 17.118 1.723 ;
     RECT  17.856 1.147 20.898 1.723 ;
     RECT  22.428 1.147 25.542 1.723 ;
     RECT  26.28 1.675 26.514 1.723 ;
     RECT  27.252 0.235 27.594 1.723 ;
     RECT  29.124 0.091 29.142 1.723 ;
     RECT  29.988 0.571 30.618 1.723 ;
     RECT  123.876 1.876 123.894 1.921 ;
     RECT  119.016 1.921 119.034 1.957 ;
     RECT  125.388 1.957 125.406 1.993 ;
     RECT  126.252 1.831 126.27 1.993 ;
     RECT  121.176 1.963 121.194 2.011 ;
     RECT  121.032 2.011 121.194 2.029 ;
     RECT  125.388 1.993 126.774 2.029 ;
     RECT  111.42 2.029 111.438 2.059 ;
     RECT  121.032 2.029 121.77 2.065 ;
     RECT  91.224 1.993 91.242 2.101 ;
     RECT  117.396 1.957 117.414 2.101 ;
     RECT  121.032 2.065 122.274 2.101 ;
     RECT  123.336 1.921 123.894 2.101 ;
     RECT  61.308 2.029 61.326 2.143 ;
     RECT  89.388 2.101 89.406 2.143 ;
     RECT  94.896 2.065 94.914 2.143 ;
     RECT  99.108 2.065 99.126 2.143 ;
     RECT  100.224 2.065 100.242 2.143 ;
     RECT  110.088 2.029 110.106 2.143 ;
     RECT  110.844 2.059 111.438 2.143 ;
     RECT  115.704 1.831 115.722 2.143 ;
     RECT  11.952 1.723 27.81 2.191 ;
     RECT  29.124 1.723 30.942 2.191 ;
     RECT  40.215 2.143 40.305 2.191 ;
     RECT  61.308 2.143 61.905 2.191 ;
     RECT  78.015 2.143 78.105 2.191 ;
     RECT  79.488 2.065 79.758 2.191 ;
     RECT  83.415 2.143 83.505 2.191 ;
     RECT  86.652 1.993 86.67 2.191 ;
     RECT  88.815 2.143 89.406 2.191 ;
     RECT  91.152 2.101 91.242 2.191 ;
     RECT  99.108 2.143 100.242 2.191 ;
     RECT  121.032 2.101 122.526 2.191 ;
     RECT  123.264 2.101 123.894 2.191 ;
     RECT  125.208 2.029 127.242 2.191 ;
     RECT  29.124 2.191 31.986 2.203 ;
     RECT  64.692 2.191 64.71 2.203 ;
     RECT  11.34 2.191 27.81 2.227 ;
     RECT  29.124 2.203 32.058 2.227 ;
     RECT  61.308 2.191 62.334 2.227 ;
     RECT  64.224 2.203 64.71 2.227 ;
     RECT  66.348 2.191 66.366 2.227 ;
     RECT  67.215 2.143 67.305 2.227 ;
     RECT  68.148 2.191 68.454 2.227 ;
     RECT  75.852 2.191 75.87 2.227 ;
     RECT  77.472 2.191 78.105 2.227 ;
     RECT  78.984 2.191 79.758 2.227 ;
     RECT  83.415 2.191 83.826 2.227 ;
     RECT  97.884 2.191 97.902 2.227 ;
     RECT  105.015 2.143 105.105 2.227 ;
     RECT  107.28 2.065 107.298 2.227 ;
     RECT  108.792 2.101 108.81 2.227 ;
     RECT  110.088 2.143 111.438 2.227 ;
     RECT  112.644 1.876 112.662 2.227 ;
     RECT  115.704 2.143 115.905 2.227 ;
     RECT  118.98 1.957 119.034 2.227 ;
     RECT  120.06 2.191 120.078 2.227 ;
     RECT  11.34 2.227 32.058 2.251 ;
     RECT  45.615 2.143 45.705 2.251 ;
     RECT  77.472 2.227 79.758 2.251 ;
     RECT  86.184 2.191 86.814 2.251 ;
     RECT  88.596 2.191 89.694 2.251 ;
     RECT  92.7 2.191 92.718 2.251 ;
     RECT  40.104 2.191 40.305 2.263 ;
     RECT  50.04 2.227 50.058 2.263 ;
     RECT  51.015 2.143 51.105 2.263 ;
     RECT  66.204 2.227 66.366 2.263 ;
     RECT  67.215 2.227 68.454 2.263 ;
     RECT  72.615 2.143 72.705 2.263 ;
     RECT  81.972 2.191 81.99 2.263 ;
     RECT  83.415 2.227 84.078 2.263 ;
     RECT  84.996 2.191 85.014 2.263 ;
     RECT  90.972 2.191 91.242 2.263 ;
     RECT  94.215 2.143 94.914 2.263 ;
     RECT  95.832 2.227 95.85 2.263 ;
     RECT  97.884 2.227 98.01 2.263 ;
     RECT  103.608 2.191 103.626 2.263 ;
     RECT  105.015 2.227 105.354 2.263 ;
     RECT  114.12 1.993 114.138 2.263 ;
     RECT  121.032 2.191 123.894 2.263 ;
     RECT  124.884 2.191 127.242 2.263 ;
     RECT  56.415 2.143 56.505 2.293 ;
     RECT  39.924 2.263 40.305 2.299 ;
     RECT  49.716 2.263 51.105 2.299 ;
     RECT  58.284 2.191 59.454 2.299 ;
     RECT  64.224 2.227 65.214 2.299 ;
     RECT  77.184 2.251 79.758 2.299 ;
     RECT  94.215 2.263 95.094 2.299 ;
     RECT  95.832 2.263 96.138 2.299 ;
     RECT  96.948 2.065 96.966 2.299 ;
     RECT  97.884 2.263 98.334 2.299 ;
     RECT  102.24 2.263 102.258 2.299 ;
     RECT  103.284 2.263 105.498 2.299 ;
     RECT  106.596 2.227 108.81 2.299 ;
     RECT  118.98 2.227 120.078 2.299 ;
     RECT  121.032 2.263 127.242 2.299 ;
     RECT  9.9 2.191 9.918 2.335 ;
     RECT  35.712 2.263 35.73 2.335 ;
     RECT  39.888 2.299 40.305 2.335 ;
     RECT  41.94 1.957 41.958 2.335 ;
     RECT  43.236 2.227 43.254 2.335 ;
     RECT  49.716 2.299 51.174 2.335 ;
     RECT  55.008 2.191 55.026 2.335 ;
     RECT  56.415 2.293 57.006 2.335 ;
     RECT  71.532 2.263 71.55 2.335 ;
     RECT  81.504 2.263 81.99 2.335 ;
     RECT  83.415 2.263 85.014 2.335 ;
     RECT  85.824 2.251 86.814 2.335 ;
     RECT  115.704 2.227 116.262 2.335 ;
     RECT  118.98 2.299 127.242 2.335 ;
     RECT  45.54 2.251 45.705 2.347 ;
     RECT  46.944 2.251 46.962 2.347 ;
     RECT  47.7 2.227 47.718 2.347 ;
     RECT  81.504 2.335 82.026 2.347 ;
     RECT  110.088 2.227 112.662 2.347 ;
     RECT  113.904 2.263 114.138 2.347 ;
     RECT  114.984 2.335 116.262 2.347 ;
     RECT  117.216 2.101 117.414 2.347 ;
     RECT  11.34 2.251 32.31 2.371 ;
     RECT  33.84 2.101 33.858 2.371 ;
     RECT  34.815 2.143 34.905 2.371 ;
     RECT  35.712 2.335 36.09 2.371 ;
     RECT  38.592 2.191 38.61 2.371 ;
     RECT  39.348 2.335 41.958 2.371 ;
     RECT  42.876 2.335 43.254 2.371 ;
     RECT  46.944 2.347 47.718 2.371 ;
     RECT  48.456 2.227 48.474 2.371 ;
     RECT  56.415 2.335 57.114 2.371 ;
     RECT  58.104 2.299 59.454 2.371 ;
     RECT  70.452 2.227 70.47 2.371 ;
     RECT  71.496 2.335 71.55 2.371 ;
     RECT  72.576 2.263 73.458 2.371 ;
     RECT  74.7 2.251 74.718 2.371 ;
     RECT  75.564 2.227 75.87 2.371 ;
     RECT  81.108 2.347 82.026 2.371 ;
     RECT  90.648 2.263 91.242 2.371 ;
     RECT  92.412 2.251 92.718 2.371 ;
     RECT  102.24 2.299 105.498 2.371 ;
     RECT  106.596 2.299 109.242 2.371 ;
     RECT  110.088 2.347 114.138 2.371 ;
     RECT  114.984 2.347 117.414 2.371 ;
     RECT  118.98 2.335 127.314 2.371 ;
     RECT  129.564 2.263 129.582 2.371 ;
     RECT  110.088 2.371 117.486 2.381 ;
     RECT  2.415 2.143 2.505 2.413 ;
     RECT  7.815 2.143 7.905 2.413 ;
     RECT  45.54 2.347 45.774 2.413 ;
     RECT  46.512 2.371 47.718 2.413 ;
     RECT  42.804 2.371 44.046 2.461 ;
     RECT  48.456 2.371 48.87 2.461 ;
     RECT  49.716 2.335 51.426 2.461 ;
     RECT  61.164 2.227 62.334 2.461 ;
     RECT  64.224 2.299 65.25 2.461 ;
     RECT  66.204 2.263 68.706 2.461 ;
     RECT  69.48 2.371 69.498 2.461 ;
     RECT  70.452 2.371 70.578 2.461 ;
     RECT  71.352 2.371 71.802 2.461 ;
     RECT  72.576 2.371 73.602 2.461 ;
     RECT  77.184 2.299 80.118 2.461 ;
     RECT  81.036 2.371 82.026 2.461 ;
     RECT  83.268 2.335 85.014 2.461 ;
     RECT  85.824 2.335 86.922 2.461 ;
     RECT  88.092 2.251 89.694 2.461 ;
     RECT  90.432 2.371 93.474 2.461 ;
     RECT  94.215 2.299 98.334 2.461 ;
     RECT  99.108 2.191 101.142 2.461 ;
     RECT  114.12 2.381 117.486 2.461 ;
     RECT  118.296 2.371 127.314 2.461 ;
     RECT  88.092 2.461 93.474 2.491 ;
     RECT  94.215 2.461 101.358 2.491 ;
     RECT  45.54 2.413 47.718 2.497 ;
     RECT  48.456 2.461 51.426 2.497 ;
     RECT  54.972 2.335 55.026 2.497 ;
     RECT  74.7 2.371 75.87 2.497 ;
     RECT  63.828 2.461 65.25 2.533 ;
     RECT  83.268 2.461 87.354 2.533 ;
     RECT  88.092 2.491 101.358 2.533 ;
     RECT  114.12 2.461 127.314 2.533 ;
     RECT  42.804 2.461 44.262 2.539 ;
     RECT  54.792 2.497 55.026 2.539 ;
     RECT  48.456 2.497 51.678 2.569 ;
     RECT  61.164 2.461 62.55 2.569 ;
     RECT  66.204 2.461 73.602 2.569 ;
     RECT  83.16 2.533 101.358 2.569 ;
     RECT  56.415 2.371 59.454 2.582 ;
     RECT  63.828 2.533 65.322 2.587 ;
     RECT  66.168 2.569 73.602 2.587 ;
     RECT  37.296 2.371 37.314 2.605 ;
     RECT  38.052 2.371 41.958 2.605 ;
     RECT  42.768 2.539 44.262 2.605 ;
     RECT  54.72 2.539 55.026 2.605 ;
     RECT  60.3 2.299 60.318 2.605 ;
     RECT  61.164 2.569 62.91 2.605 ;
     RECT  77.184 2.461 82.026 2.605 ;
     RECT  45.468 2.497 47.718 2.633 ;
     RECT  9.036 2.605 9.054 2.641 ;
     RECT  9.9 2.335 10.098 2.641 ;
     RECT  11.304 2.371 32.31 2.641 ;
     RECT  37.296 2.605 41.958 2.641 ;
     RECT  42.768 2.605 44.298 2.641 ;
     RECT  53.46 2.335 53.478 2.641 ;
     RECT  54.72 2.605 55.062 2.641 ;
     RECT  55.98 2.582 59.454 2.641 ;
     RECT  60.3 2.605 62.91 2.641 ;
     RECT  76.716 2.605 82.026 2.641 ;
     RECT  83.16 2.569 101.43 2.641 ;
     RECT  102.24 2.371 109.278 2.641 ;
     RECT  110.088 2.381 113.274 2.641 ;
     RECT  33.696 2.371 36.306 2.767 ;
     RECT  63.828 2.587 73.602 2.767 ;
     RECT  114.12 2.533 127.818 2.767 ;
     RECT  11.268 2.641 32.31 2.779 ;
     RECT  74.664 2.497 75.978 2.779 ;
     RECT  76.716 2.641 109.278 2.779 ;
     RECT  11.268 2.779 32.454 2.803 ;
     RECT  33.516 2.767 36.306 2.803 ;
     RECT  54.72 2.641 62.91 2.803 ;
     RECT  63.648 2.767 73.602 2.803 ;
     RECT  54.72 2.803 73.602 2.839 ;
     RECT  74.664 2.779 109.278 2.839 ;
     RECT  45.468 2.633 47.682 2.875 ;
     RECT  48.456 2.569 52.002 2.875 ;
     RECT  7.815 2.413 8.097 2.911 ;
     RECT  10.908 2.803 32.454 2.911 ;
     RECT  33.264 2.803 36.306 2.911 ;
     RECT  52.956 2.641 53.766 2.911 ;
     RECT  48.456 2.875 52.146 3.001 ;
     RECT  52.956 2.911 53.91 3.001 ;
     RECT  54.72 2.839 109.278 3.001 ;
     RECT  48.456 3.001 109.278 3.067 ;
     RECT  110.052 2.641 113.274 3.067 ;
     RECT  10.908 2.911 36.306 3.073 ;
     RECT  7.776 2.911 8.097 3.109 ;
     RECT  114.12 2.767 127.89 3.109 ;
     RECT  128.844 2.371 129.582 3.109 ;
     RECT  10.872 3.073 36.306 3.115 ;
     RECT  7.776 3.109 8.154 3.145 ;
     RECT  9.036 2.641 10.098 3.145 ;
     RECT  10.872 3.115 36.522 3.145 ;
     RECT  6.948 3.145 6.966 3.271 ;
     RECT  7.776 3.145 8.226 3.271 ;
     RECT  6.948 3.271 8.226 3.307 ;
     RECT  9.036 3.145 36.522 3.307 ;
     RECT  6.948 3.307 36.522 3.335 ;
     RECT  48.456 3.067 113.274 3.355 ;
     RECT  114.12 3.109 129.582 3.355 ;
     RECT  5.904 3.379 5.922 3.403 ;
     RECT  6.948 3.335 35.097 3.403 ;
     RECT  2.415 2.413 2.697 3.445 ;
     RECT  5.904 3.403 35.097 3.451 ;
     RECT  45.108 2.875 47.682 3.451 ;
     RECT  48.456 3.355 129.582 3.451 ;
     RECT  37.296 2.641 44.298 3.479 ;
     RECT  39.564 3.479 44.298 3.547 ;
     RECT  45.108 3.451 129.582 3.547 ;
     RECT  0.108 2.875 0.126 3.677 ;
     RECT  4.392 3.595 4.41 3.685 ;
     RECT  5.148 3.451 35.097 3.685 ;
     RECT  4.392 3.685 35.097 3.713 ;
     RECT  2.415 3.445 2.79 3.721 ;
     RECT  39.564 3.547 129.582 3.749 ;
     RECT  45.108 3.749 129.582 3.875 ;
     RECT  35.82 3.335 36.522 3.883 ;
     RECT  37.296 3.479 38.79 3.883 ;
     RECT  52.956 3.875 129.582 3.965 ;
     RECT  2.415 3.721 3.654 3.979 ;
     RECT  4.392 3.713 32.49 3.979 ;
     RECT  39.564 3.749 44.262 4.253 ;
     RECT  33.264 3.713 35.097 4.261 ;
     RECT  35.82 3.883 38.79 4.261 ;
     RECT  39.564 4.253 44.154 4.261 ;
     RECT  33.264 4.261 38.79 4.351 ;
     RECT  39.528 4.261 44.154 4.351 ;
     RECT  53.172 3.965 129.582 4.379 ;
     RECT  45.108 3.875 52.218 4.451 ;
     RECT  2.415 3.979 32.49 4.495 ;
     RECT  33.264 4.351 44.154 4.495 ;
     RECT  45.396 4.451 52.218 4.801 ;
     RECT  45.396 4.801 52.398 5.071 ;
     RECT  53.172 4.379 129.438 5.071 ;
     RECT  2.415 4.495 44.154 5.161 ;
     RECT  2.415 5.161 44.514 5.233 ;
     RECT  2.415 5.233 44.55 5.305 ;
     RECT  2.415 5.305 44.658 5.341 ;
     RECT  45.396 5.071 129.438 5.341 ;
     RECT  2.415 5.341 129.438 5.495 ;
     RECT  2.415 5.495 55.674 5.603 ;
     RECT  56.415 5.495 129.438 6.029 ;
     RECT  2.415 5.603 44.73 6.071 ;
     RECT  44.712 6.071 44.73 6.107 ;
     RECT  45.615 5.603 55.674 6.241 ;
     RECT  56.415 6.029 109.17 6.241 ;
     RECT  45.615 6.241 109.17 6.349 ;
     RECT  45.036 6.349 109.17 6.781 ;
     RECT  110.016 6.029 129.438 6.781 ;
     RECT  2.415 6.071 43.974 6.851 ;
     RECT  7.488 6.851 43.974 6.859 ;
     RECT  45.036 6.781 129.438 6.859 ;
     RECT  7.488 6.859 129.438 7.079 ;
     RECT  44.676 7.079 129.438 7.349 ;
     RECT  2.415 6.851 6.678 7.735 ;
     RECT  7.488 7.079 43.866 7.735 ;
     RECT  50.616 7.349 129.438 7.961 ;
     RECT  2.415 7.735 43.866 7.969 ;
     RECT  44.676 7.349 49.878 7.969 ;
     RECT  2.415 7.969 49.878 8.195 ;
     RECT  2.415 8.195 9.486 8.333 ;
     RECT  50.616 7.961 107.91 8.465 ;
     RECT  50.616 8.465 101.43 8.477 ;
     RECT  10.296 8.195 49.878 8.509 ;
     RECT  50.616 8.477 101.286 8.509 ;
     RECT  10.296 8.509 101.286 8.699 ;
     RECT  108.864 7.961 129.438 8.779 ;
     RECT  108.864 8.779 129.51 8.941 ;
     RECT  36.468 8.699 101.286 8.969 ;
     RECT  5.004 8.333 9.486 9.005 ;
     RECT  36.72 8.969 101.286 9.005 ;
     RECT  102.204 8.465 107.91 9.163 ;
     RECT  108.864 8.941 129.546 9.163 ;
     RECT  102.204 9.163 129.546 9.319 ;
     RECT  36.792 9.005 101.286 9.355 ;
     RECT  102.06 9.319 129.546 9.355 ;
     RECT  5.112 9.005 9.486 9.481 ;
     RECT  10.296 8.699 35.622 9.481 ;
     RECT  5.112 9.481 35.622 9.625 ;
     RECT  2.415 8.333 4.266 9.751 ;
     RECT  36.792 9.355 129.546 9.869 ;
     RECT  5.112 9.625 35.946 10.027 ;
     RECT  36.792 9.869 98.442 10.027 ;
     RECT  2.415 9.751 4.374 10.057 ;
     RECT  5.112 10.027 98.442 10.057 ;
     RECT  99.216 9.869 129.546 10.633 ;
     RECT  2.415 10.057 98.442 10.637 ;
     RECT  64.188 10.637 98.442 10.651 ;
     RECT  99.18 10.633 129.546 10.651 ;
     RECT  64.188 10.651 129.546 10.931 ;
     RECT  2.415 10.637 63.45 11.371 ;
     RECT  64.188 10.931 129.438 11.371 ;
     RECT  2.415 11.371 129.438 11.669 ;
     RECT  2.415 11.669 52.11 12.557 ;
     RECT  7.596 12.557 52.11 12.631 ;
     RECT  52.884 11.669 129.438 12.631 ;
     RECT  7.596 12.631 129.438 12.785 ;
     RECT  2.415 12.557 6.642 12.941 ;
     RECT  7.596 12.785 63.558 13.019 ;
     RECT  7.596 13.019 63.522 13.432 ;
     RECT  4.752 12.941 6.642 13.435 ;
     RECT  7.452 13.432 63.522 13.435 ;
     RECT  64.296 12.785 129.438 13.559 ;
     RECT  4.752 13.435 63.522 13.909 ;
     RECT  2.415 12.941 4.014 13.945 ;
     RECT  4.752 13.909 63.666 13.945 ;
     RECT  64.62 13.559 129.438 14.135 ;
     RECT  64.62 14.135 128.61 14.243 ;
     RECT  2.415 13.945 63.666 14.341 ;
     RECT  64.62 14.243 128.538 14.341 ;
     RECT  129.42 14.135 129.438 14.441 ;
     RECT  2.415 14.341 128.538 14.711 ;
     RECT  2.415 14.711 64.458 14.957 ;
     RECT  2.415 14.957 37.782 15.179 ;
     RECT  2.415 15.179 14.022 15.323 ;
     RECT  14.76 15.179 37.782 15.359 ;
     RECT  65.232 14.711 128.538 15.565 ;
     RECT  38.592 14.957 64.458 15.601 ;
     RECT  65.196 15.565 128.538 15.601 ;
     RECT  14.76 15.359 37.746 15.677 ;
     RECT  2.415 15.323 13.806 15.979 ;
     RECT  2.412 15.979 13.806 16.025 ;
     RECT  14.76 15.677 37.71 16.105 ;
     RECT  2.415 16.025 13.806 16.141 ;
     RECT  2.415 16.141 13.842 16.339 ;
     RECT  14.724 16.105 37.71 16.339 ;
     RECT  38.592 15.601 128.538 16.403 ;
     RECT  2.415 16.339 37.71 16.573 ;
     RECT  38.592 16.403 127.53 16.573 ;
     RECT  2.415 16.573 127.53 16.807 ;
     RECT  2.412 16.807 127.53 16.877 ;
     RECT  2.415 16.877 127.53 17.069 ;
     RECT  2.415 17.069 127.422 17.339 ;
     RECT  2.415 17.339 127.314 17.375 ;
     RECT  4.824 17.375 127.314 17.879 ;
     RECT  128.52 16.403 128.538 17.951 ;
     RECT  4.824 17.879 127.134 18.023 ;
     RECT  15.048 18.023 127.134 18.149 ;
     RECT  2.415 17.375 4.086 18.193 ;
     RECT  4.824 18.023 14.274 18.193 ;
     RECT  15.048 18.149 127.098 18.221 ;
     RECT  2.415 18.193 14.274 18.293 ;
     RECT  10.332 18.293 14.274 18.841 ;
     RECT  15.048 18.221 127.026 18.841 ;
     RECT  2.415 18.293 9.594 19.345 ;
     RECT  10.332 18.841 127.026 19.345 ;
     RECT  2.415 19.345 127.026 19.769 ;
     RECT  2.415 19.769 115.002 19.913 ;
     RECT  115.815 19.769 127.026 19.921 ;
     RECT  2.415 19.913 42.822 20.039 ;
     RECT  18.396 20.039 42.822 20.075 ;
     RECT  18.396 20.075 42.786 20.093 ;
     RECT  2.415 20.039 17.478 20.147 ;
     RECT  4.896 20.147 17.478 20.579 ;
     RECT  43.596 19.913 89.766 20.579 ;
     RECT  115.815 19.921 127.062 20.581 ;
     RECT  43.596 20.579 60.102 20.717 ;
     RECT  18.396 20.093 42.75 20.821 ;
     RECT  43.596 20.717 59.706 20.821 ;
     RECT  60.984 20.579 89.766 20.821 ;
     RECT  90.612 19.913 115.002 20.821 ;
     RECT  115.74 20.581 127.062 20.821 ;
     RECT  60.984 20.821 127.062 20.929 ;
     RECT  2.415 20.147 4.122 21.091 ;
     RECT  4.896 20.579 17.406 21.091 ;
     RECT  18.396 20.821 59.706 21.235 ;
     RECT  18.18 21.235 59.706 21.299 ;
     RECT  60.984 20.929 127.098 21.299 ;
     RECT  90.864 21.299 127.098 21.389 ;
     RECT  2.415 21.091 17.406 21.469 ;
     RECT  18.18 21.299 45.897 21.469 ;
     RECT  46.656 21.299 59.706 21.505 ;
     RECT  46.656 21.505 59.85 21.631 ;
     RECT  60.984 21.299 90.126 21.631 ;
     RECT  2.415 21.469 45.897 21.767 ;
     RECT  2.415 21.767 16.146 21.775 ;
     RECT  2.412 21.775 16.146 21.929 ;
     RECT  16.884 21.767 45.897 22.001 ;
     RECT  2.412 21.929 11.286 22.073 ;
     RECT  16.884 22.001 19.818 22.073 ;
     RECT  46.656 21.631 90.126 22.081 ;
     RECT  90.864 21.389 127.062 22.081 ;
     RECT  46.656 22.081 127.062 22.205 ;
     RECT  2.415 22.073 11.286 22.469 ;
     RECT  12.096 21.929 16.146 22.469 ;
     RECT  20.556 22.001 45.897 22.549 ;
     RECT  46.656 22.205 89.838 22.549 ;
     RECT  20.556 22.549 89.838 22.577 ;
     RECT  2.415 22.469 3.87 22.613 ;
     RECT  16.884 22.073 19.746 22.621 ;
     RECT  90.612 22.205 127.062 22.739 ;
     RECT  33.624 22.577 89.838 22.781 ;
     RECT  16.812 22.621 19.746 22.811 ;
     RECT  95.364 22.739 127.026 22.811 ;
     RECT  16.992 22.811 19.746 22.819 ;
     RECT  20.556 22.577 32.742 22.819 ;
     RECT  4.608 22.469 11.286 22.891 ;
     RECT  12.096 22.469 16.002 22.891 ;
     RECT  33.624 22.781 54.81 22.919 ;
     RECT  95.436 22.811 127.026 22.919 ;
     RECT  55.584 22.781 89.838 22.981 ;
     RECT  90.612 22.739 94.554 22.981 ;
     RECT  55.584 22.981 94.554 23.009 ;
     RECT  55.584 23.009 58.482 23.045 ;
     RECT  33.804 22.919 54.81 23.081 ;
     RECT  2.415 22.613 3.834 23.279 ;
     RECT  34.164 23.081 54.63 23.315 ;
     RECT  46.764 23.315 54.63 23.357 ;
     RECT  3.744 23.279 3.834 23.371 ;
     RECT  4.608 22.891 16.002 23.371 ;
     RECT  59.22 23.009 94.554 23.423 ;
     RECT  3.744 23.371 16.002 23.521 ;
     RECT  16.992 22.819 32.742 23.557 ;
     RECT  3.744 23.521 16.146 23.629 ;
     RECT  16.992 23.557 32.814 23.629 ;
     RECT  61.128 23.423 94.554 23.665 ;
     RECT  61.128 23.665 94.842 23.819 ;
     RECT  55.62 23.045 58.482 23.827 ;
     RECT  59.22 23.423 60.282 23.827 ;
     RECT  55.44 23.827 60.282 23.885 ;
     RECT  95.652 22.919 127.026 23.891 ;
     RECT  34.164 23.315 45.954 23.971 ;
     RECT  61.128 23.819 90.81 23.981 ;
     RECT  33.624 23.971 45.954 24.061 ;
     RECT  112.68 23.891 127.026 24.089 ;
     RECT  3.744 23.629 32.886 24.091 ;
     RECT  33.624 24.061 46.026 24.091 ;
     RECT  2.415 23.279 2.97 24.097 ;
     RECT  3.744 24.091 46.026 24.097 ;
     RECT  46.764 23.357 51.297 24.097 ;
     RECT  52.164 23.357 54.522 24.097 ;
     RECT  55.764 23.885 60.282 24.125 ;
     RECT  123.804 24.089 127.026 24.125 ;
     RECT  46.764 24.097 54.522 24.133 ;
     RECT  2.415 24.097 46.026 24.161 ;
     RECT  34.308 24.161 46.026 24.169 ;
     RECT  46.764 24.133 54.702 24.169 ;
     RECT  61.128 23.981 63.486 24.205 ;
     RECT  123.804 24.125 126.954 24.233 ;
     RECT  34.308 24.169 54.81 24.269 ;
     RECT  64.26 23.981 90.81 24.461 ;
     RECT  112.68 24.089 123.03 24.509 ;
     RECT  112.68 24.509 122.958 24.539 ;
     RECT  123.912 24.233 126.954 24.539 ;
     RECT  91.728 23.819 94.497 24.619 ;
     RECT  95.652 23.891 111.798 24.637 ;
     RECT  91.728 24.619 94.662 24.673 ;
     RECT  95.4 24.637 111.798 24.673 ;
     RECT  60.516 24.205 63.486 24.709 ;
     RECT  64.26 24.461 85.734 24.709 ;
     RECT  86.616 24.461 90.81 24.709 ;
     RECT  55.944 24.125 59.454 24.737 ;
     RECT  55.944 24.737 57.654 24.773 ;
     RECT  91.728 24.673 111.798 24.781 ;
     RECT  58.536 24.737 59.454 24.871 ;
     RECT  60.516 24.709 85.734 24.899 ;
     RECT  60.516 24.899 73.026 24.935 ;
     RECT  73.764 24.899 85.734 24.935 ;
     RECT  60.516 24.935 63.954 24.971 ;
     RECT  2.415 24.161 33.534 24.979 ;
     RECT  34.308 24.269 52.614 24.979 ;
     RECT  86.616 24.709 90.846 25.003 ;
     RECT  91.656 24.781 111.834 25.003 ;
     RECT  2.415 24.979 52.614 25.015 ;
     RECT  53.532 24.269 54.81 25.015 ;
     RECT  55.944 24.773 57.51 25.015 ;
     RECT  86.616 25.003 111.834 25.037 ;
     RECT  86.616 25.037 89.262 25.043 ;
     RECT  90.036 25.037 111.834 25.051 ;
     RECT  123.912 24.539 126.897 25.051 ;
     RECT  60.516 24.971 63.882 25.079 ;
     RECT  2.415 25.015 52.758 25.099 ;
     RECT  53.532 25.015 57.51 25.099 ;
     RECT  60.516 25.079 63.846 25.177 ;
     RECT  86.616 25.043 89.154 25.213 ;
     RECT  58.536 24.871 59.526 25.321 ;
     RECT  60.372 25.177 63.846 25.321 ;
     RECT  123.804 25.051 126.897 25.321 ;
     RECT  90.036 25.051 111.942 25.435 ;
     RECT  112.68 24.539 122.706 25.435 ;
     RECT  2.415 25.099 57.51 25.439 ;
     RECT  123.624 25.321 126.897 25.447 ;
     RECT  74.556 24.935 85.734 25.483 ;
     RECT  86.58 25.213 89.154 25.483 ;
     RECT  58.536 25.321 63.846 25.511 ;
     RECT  90.036 25.435 122.706 25.555 ;
     RECT  123.624 25.447 126.99 25.591 ;
     RECT  53.928 25.439 57.51 25.681 ;
     RECT  58.536 25.511 63.378 25.681 ;
     RECT  64.692 24.935 73.026 25.681 ;
     RECT  73.764 24.935 73.782 25.681 ;
     RECT  123.624 25.591 127.314 25.709 ;
     RECT  64.692 25.681 73.782 25.715 ;
     RECT  64.98 25.715 73.782 25.753 ;
     RECT  74.556 25.483 89.154 25.753 ;
     RECT  64.98 25.753 89.154 25.789 ;
     RECT  64.98 25.789 89.19 25.819 ;
     RECT  64.98 25.819 89.298 25.861 ;
     RECT  90.036 25.555 122.886 25.861 ;
     RECT  123.624 25.709 127.134 25.861 ;
     RECT  53.928 25.681 63.378 25.889 ;
     RECT  2.415 25.439 53.154 26.131 ;
     RECT  2.376 26.131 53.154 26.203 ;
     RECT  53.928 25.889 63.198 26.203 ;
     RECT  64.98 25.861 127.134 26.237 ;
     RECT  129.564 25.555 129.582 26.365 ;
     RECT  81.504 26.237 127.134 26.393 ;
     RECT  81.504 26.393 84.654 26.429 ;
     RECT  81.54 26.429 84.654 26.519 ;
     RECT  64.98 26.237 80.658 26.563 ;
     RECT  85.464 26.393 127.134 26.591 ;
     RECT  129.492 26.365 129.582 26.599 ;
     RECT  64.44 26.563 80.658 26.635 ;
     RECT  85.536 26.591 127.134 26.671 ;
     RECT  2.376 26.203 63.198 26.683 ;
     RECT  2.376 26.683 63.306 26.699 ;
     RECT  2.376 26.699 30.978 26.789 ;
     RECT  129.42 26.599 129.582 26.797 ;
     RECT  64.296 26.635 80.658 26.813 ;
     RECT  31.788 26.699 63.306 26.825 ;
     RECT  129.384 26.797 129.582 26.833 ;
     RECT  128.808 26.833 129.582 26.905 ;
     RECT  31.86 26.825 63.306 26.941 ;
     RECT  31.86 26.941 63.45 27.059 ;
     RECT  64.404 26.813 80.658 27.211 ;
     RECT  81.576 26.519 84.654 27.211 ;
     RECT  31.86 27.059 63.27 27.365 ;
     RECT  64.404 27.211 80.766 27.365 ;
     RECT  81.576 27.211 84.69 27.373 ;
     RECT  85.536 26.671 127.314 27.373 ;
     RECT  64.836 27.365 80.766 27.445 ;
     RECT  81.576 27.373 127.314 27.445 ;
     RECT  64.836 27.445 127.314 27.509 ;
     RECT  2.415 26.789 30.978 27.643 ;
     RECT  31.86 27.365 40.95 27.643 ;
     RECT  41.832 27.365 63.27 27.841 ;
     RECT  64.836 27.509 127.134 27.869 ;
     RECT  64.98 27.869 127.134 27.941 ;
     RECT  65.124 27.941 127.134 27.977 ;
     RECT  128.268 26.905 129.582 28.049 ;
     RECT  2.415 27.643 40.95 28.111 ;
     RECT  41.832 27.841 63.774 28.111 ;
     RECT  128.268 28.049 129.438 28.171 ;
     RECT  128.232 28.171 129.438 28.219 ;
     RECT  2.415 28.111 63.774 28.291 ;
     RECT  68.436 27.977 127.134 28.291 ;
     RECT  2.415 28.291 63.882 28.409 ;
     RECT  68.436 28.291 127.314 28.445 ;
     RECT  128.16 28.219 129.438 28.445 ;
     RECT  128.16 28.445 129.366 28.481 ;
     RECT  88.416 28.445 127.314 28.553 ;
     RECT  65.124 27.977 67.554 28.687 ;
     RECT  65.088 28.687 67.554 28.699 ;
     RECT  68.436 28.445 87.57 28.699 ;
     RECT  64.98 28.699 87.57 28.733 ;
     RECT  87.552 28.733 87.57 28.781 ;
     RECT  128.232 28.481 129.366 28.859 ;
     RECT  128.232 28.859 128.718 29.021 ;
     RECT  88.416 28.553 127.242 29.069 ;
     RECT  64.98 28.733 86.814 29.093 ;
     RECT  54.792 28.409 63.774 29.191 ;
     RECT  65.196 29.093 86.814 29.219 ;
     RECT  2.415 28.409 53.874 29.227 ;
     RECT  54.792 29.191 64.062 29.227 ;
     RECT  2.415 29.227 64.062 29.489 ;
     RECT  88.416 29.069 98.586 29.533 ;
     RECT  99.432 29.069 127.242 29.569 ;
     RECT  88.38 29.533 98.586 29.605 ;
     RECT  54.72 29.489 64.062 29.645 ;
     RECT  65.196 29.219 86.778 29.645 ;
     RECT  99.432 29.569 127.314 29.759 ;
     RECT  58.14 29.645 64.062 29.795 ;
     RECT  99.432 29.759 127.242 29.795 ;
     RECT  88.128 29.605 98.586 29.875 ;
     RECT  58.248 29.795 64.062 29.911 ;
     RECT  2.415 29.489 53.802 30.137 ;
     RECT  128.232 29.021 128.25 30.137 ;
     RECT  58.248 29.911 64.494 30.173 ;
     RECT  87.516 29.875 98.586 30.181 ;
     RECT  54.72 29.645 56.934 30.235 ;
     RECT  31.86 30.137 53.802 30.271 ;
     RECT  54.576 30.235 56.934 30.271 ;
     RECT  87.516 30.181 98.658 30.331 ;
     RECT  99.432 29.795 127.17 30.331 ;
     RECT  65.448 29.645 86.778 30.343 ;
     RECT  87.516 30.331 127.17 30.343 ;
     RECT  58.248 30.173 63.882 30.479 ;
     RECT  58.248 30.479 63.81 30.685 ;
     RECT  65.448 30.343 127.17 30.685 ;
     RECT  129.42 30.649 129.438 30.685 ;
     RECT  2.415 30.137 31.122 30.713 ;
     RECT  64.944 30.685 127.17 30.721 ;
     RECT  57.816 30.685 63.81 30.859 ;
     RECT  31.86 30.271 56.934 30.919 ;
     RECT  57.708 30.859 63.81 30.919 ;
     RECT  31.86 30.919 63.81 31.153 ;
     RECT  31.608 31.153 63.81 31.225 ;
     RECT  31.608 31.225 63.882 31.261 ;
     RECT  31.608 31.261 63.954 31.289 ;
     RECT  64.944 30.721 127.35 31.351 ;
     RECT  54.54 31.289 63.954 31.387 ;
     RECT  2.415 30.713 30.834 31.459 ;
     RECT  31.608 31.289 53.802 31.459 ;
     RECT  54.54 31.387 64.134 31.459 ;
     RECT  64.944 31.351 127.71 31.459 ;
     RECT  54.54 31.459 127.71 31.523 ;
     RECT  54.648 31.523 127.71 31.649 ;
     RECT  54.684 31.649 127.71 31.729 ;
     RECT  129.42 30.685 129.51 31.891 ;
     RECT  54.684 31.729 128.322 31.919 ;
     RECT  129.348 31.891 129.51 32.063 ;
     RECT  54.684 31.919 85.122 32.225 ;
     RECT  86.04 31.919 128.322 32.296 ;
     RECT  129.348 32.063 129.438 32.296 ;
     RECT  54.684 32.225 58.59 32.333 ;
     RECT  59.364 32.225 85.122 32.477 ;
     RECT  2.415 31.459 53.802 32.575 ;
     RECT  54.684 32.333 58.554 32.575 ;
     RECT  86.04 32.296 129.438 32.999 ;
     RECT  60.084 32.477 85.122 33.043 ;
     RECT  86.04 32.999 128.214 33.043 ;
     RECT  60.084 33.043 128.214 33.053 ;
     RECT  80.928 33.053 128.214 33.071 ;
     RECT  80.928 33.071 127.638 33.143 ;
     RECT  60.084 33.053 80.154 33.377 ;
     RECT  60.084 33.377 74.934 33.385 ;
     RECT  2.415 32.575 58.554 33.421 ;
     RECT  75.708 33.377 80.154 33.437 ;
     RECT  2.415 33.421 58.95 33.451 ;
     RECT  60.012 33.385 74.934 33.451 ;
     RECT  2.415 33.451 74.934 33.539 ;
     RECT  2.415 33.539 39.186 33.611 ;
     RECT  40.032 33.539 74.934 33.869 ;
     RECT  91.908 33.143 127.638 33.961 ;
     RECT  59.436 33.869 74.934 34.013 ;
     RECT  75.744 33.437 80.154 34.051 ;
     RECT  80.928 33.143 91.062 34.051 ;
     RECT  129.312 32.999 129.438 34.079 ;
     RECT  59.472 34.013 74.934 34.115 ;
     RECT  59.472 34.115 73.098 34.151 ;
     RECT  91.872 33.961 127.638 34.186 ;
     RECT  2.415 33.611 11.79 34.205 ;
     RECT  12.6 33.611 39.186 34.259 ;
     RECT  75.744 34.051 91.062 34.315 ;
     RECT  91.836 34.186 127.638 34.315 ;
     RECT  59.472 34.151 72.99 34.349 ;
     RECT  73.836 34.115 74.934 34.357 ;
     RECT  12.6 34.259 38.034 34.429 ;
     RECT  38.772 34.259 39.186 34.465 ;
     RECT  38.772 34.465 39.258 34.501 ;
     RECT  40.032 33.869 58.554 34.501 ;
     RECT  38.772 34.501 58.554 34.529 ;
     RECT  59.724 34.349 72.99 34.529 ;
     RECT  12.564 34.429 38.034 34.699 ;
     RECT  73.836 34.357 75.006 34.699 ;
     RECT  75.744 34.315 127.638 34.699 ;
     RECT  73.836 34.699 127.638 34.781 ;
     RECT  73.836 34.781 119.394 34.889 ;
     RECT  59.76 34.529 72.99 34.897 ;
     RECT  73.836 34.889 76.446 34.897 ;
     RECT  59.76 34.897 76.446 35.021 ;
     RECT  59.76 35.021 69.03 35.033 ;
     RECT  69.984 35.021 76.446 35.033 ;
     RECT  2.415 34.205 11.43 35.041 ;
     RECT  77.364 34.889 119.394 35.069 ;
     RECT  120.384 34.781 127.638 35.159 ;
     RECT  12.456 34.699 38.034 35.227 ;
     RECT  38.772 34.529 58.158 35.227 ;
     RECT  77.364 35.069 102.438 35.267 ;
     RECT  59.76 35.033 68.058 35.275 ;
     RECT  77.508 35.267 102.438 35.312 ;
     RECT  59.688 35.275 68.058 35.323 ;
     RECT  103.356 35.069 119.394 35.545 ;
     RECT  120.384 35.159 127.242 35.545 ;
     RECT  12.456 35.227 58.158 35.581 ;
     RECT  77.688 35.312 102.438 35.609 ;
     RECT  12.456 35.581 58.518 35.743 ;
     RECT  73.764 35.033 76.446 35.743 ;
     RECT  73.764 35.743 76.734 35.807 ;
     RECT  77.688 35.609 81.378 35.807 ;
     RECT  12.456 35.743 58.626 35.815 ;
     RECT  59.652 35.323 68.058 35.815 ;
     RECT  69.012 35.033 69.03 35.815 ;
     RECT  69.984 35.033 72.99 35.815 ;
     RECT  73.764 35.807 75.402 35.815 ;
     RECT  2.415 35.041 11.574 35.851 ;
     RECT  12.456 35.815 58.734 35.851 ;
     RECT  59.652 35.815 69.03 35.851 ;
     RECT  69.984 35.815 75.402 35.851 ;
     RECT  82.656 35.609 102.438 35.851 ;
     RECT  103.356 35.545 127.242 35.851 ;
     RECT  82.656 35.851 127.242 35.879 ;
     RECT  82.728 35.879 127.242 36.041 ;
     RECT  77.688 35.807 80.55 36.121 ;
     RECT  81.288 35.807 81.378 36.173 ;
     RECT  81.288 36.173 81.306 36.239 ;
     RECT  129.42 34.079 129.438 36.239 ;
     RECT  82.728 36.041 127.098 36.275 ;
     RECT  2.415 35.851 58.734 36.355 ;
     RECT  59.652 35.851 75.402 36.355 ;
     RECT  76.212 35.807 76.734 36.355 ;
     RECT  77.472 36.121 80.55 36.355 ;
     RECT  82.728 36.275 126.99 36.509 ;
     RECT  2.415 36.355 75.402 36.553 ;
     RECT  76.212 36.355 80.55 36.553 ;
     RECT  82.728 36.509 126.897 36.661 ;
     RECT  2.415 36.553 80.55 36.859 ;
     RECT  82.692 36.661 126.897 36.887 ;
     RECT  2.415 36.859 81.162 37.021 ;
     RECT  2.415 37.021 81.306 37.201 ;
     RECT  2.415 37.201 81.45 37.561 ;
     RECT  2.415 37.561 81.666 37.859 ;
     RECT  38.196 37.859 81.666 37.861 ;
     RECT  38.196 37.861 82.17 38.011 ;
     RECT  38.196 38.011 82.35 38.101 ;
     RECT  83.124 36.887 126.897 38.101 ;
     RECT  38.196 38.101 126.897 38.543 ;
     RECT  38.196 38.543 66.438 38.579 ;
     RECT  2.415 37.859 37.422 38.635 ;
     RECT  38.196 38.579 66.366 38.635 ;
     RECT  67.176 38.543 126.897 38.705 ;
     RECT  93.492 38.705 126.897 38.813 ;
     RECT  2.415 38.635 66.366 38.939 ;
     RECT  93.492 38.813 96.138 38.939 ;
     RECT  2.415 38.939 37.962 39.245 ;
     RECT  97.056 38.813 126.897 39.245 ;
     RECT  67.176 38.705 92.754 39.289 ;
     RECT  93.6 38.939 96.138 39.317 ;
     RECT  38.844 38.939 66.366 39.325 ;
     RECT  67.14 39.289 92.754 39.325 ;
     RECT  2.415 39.245 4.95 39.341 ;
     RECT  38.844 39.325 92.754 39.389 ;
     RECT  38.844 39.389 73.674 39.479 ;
     RECT  38.844 39.479 73.638 39.623 ;
     RECT  2.415 39.341 3.006 39.659 ;
     RECT  5.724 39.245 37.962 39.659 ;
     RECT  97.092 39.245 126.897 39.659 ;
     RECT  6.444 39.659 37.962 39.691 ;
     RECT  6.444 39.691 38.07 39.721 ;
     RECT  38.844 39.623 68.85 39.721 ;
     RECT  69.588 39.623 73.638 39.785 ;
     RECT  74.484 39.389 92.754 39.793 ;
     RECT  3.996 39.341 4.95 39.821 ;
     RECT  6.444 39.721 68.85 39.821 ;
     RECT  74.484 39.793 92.934 39.827 ;
     RECT  124.308 39.659 126.897 39.857 ;
     RECT  90.072 39.827 92.934 39.893 ;
     RECT  3.996 39.821 4.014 40.019 ;
     RECT  93.708 39.317 96.138 40.027 ;
     RECT  97.092 39.659 123.498 40.027 ;
     RECT  93.708 40.027 123.498 40.091 ;
     RECT  37.224 39.821 68.85 40.199 ;
     RECT  6.444 39.821 36.45 40.289 ;
     RECT  93.708 40.091 123.462 40.289 ;
     RECT  125.028 39.857 126.897 40.289 ;
     RECT  6.444 40.289 6.462 40.325 ;
     RECT  7.2 40.289 36.45 40.325 ;
     RECT  69.624 39.785 73.638 40.325 ;
     RECT  125.028 40.289 125.874 40.325 ;
     RECT  7.416 40.325 36.45 40.361 ;
     RECT  100.98 40.289 123.138 40.361 ;
     RECT  125.028 40.325 125.406 40.361 ;
     RECT  37.224 40.199 68.058 40.397 ;
     RECT  93.708 40.289 100.242 40.397 ;
     RECT  100.98 40.361 122.562 40.397 ;
     RECT  70.56 40.325 73.638 40.405 ;
     RECT  74.484 39.827 89.19 40.405 ;
     RECT  7.416 40.361 33.642 40.433 ;
     RECT  37.224 40.397 67.914 40.433 ;
     RECT  93.708 40.397 98.262 40.441 ;
     RECT  7.416 40.433 9.486 40.469 ;
     RECT  34.416 40.361 36.45 40.469 ;
     RECT  122.544 40.397 122.562 40.469 ;
     RECT  7.815 40.469 9.486 40.559 ;
     RECT  10.404 40.433 26.55 40.559 ;
     RECT  27.288 40.433 33.642 40.559 ;
     RECT  34.416 40.469 36.234 40.559 ;
     RECT  37.224 40.433 67.878 40.559 ;
     RECT  70.56 40.405 89.19 40.559 ;
     RECT  93.6 40.441 98.262 40.559 ;
     RECT  101.052 40.397 121.497 40.559 ;
     RECT  37.224 40.559 38.034 40.589 ;
     RECT  34.524 40.559 36.234 40.595 ;
     RECT  39.168 40.559 58.374 40.595 ;
     RECT  70.56 40.559 81.954 40.595 ;
     RECT  82.728 40.559 89.19 40.595 ;
     RECT  7.815 40.559 8.19 40.631 ;
     RECT  39.168 40.595 56.934 40.631 ;
     RECT  10.404 40.559 12.294 40.637 ;
     RECT  101.916 40.559 113.274 40.637 ;
     RECT  68.796 40.199 68.85 40.639 ;
     RECT  69.624 40.325 69.786 40.639 ;
     RECT  10.404 40.637 12.006 40.654 ;
     RECT  101.916 40.637 109.458 40.654 ;
     RECT  26.1 40.559 26.226 40.667 ;
     RECT  34.524 40.595 35.91 40.667 ;
     RECT  70.56 40.595 78.354 40.667 ;
     RECT  90.072 39.893 92.754 40.667 ;
     RECT  114.156 40.559 121.497 40.667 ;
     RECT  86.22 40.595 89.19 40.675 ;
     RECT  93.6 40.559 97.29 40.685 ;
     RECT  101.052 40.559 101.178 40.685 ;
     RECT  110.415 40.637 113.274 40.685 ;
     RECT  15.732 40.559 25.362 40.703 ;
     RECT  31.32 40.559 33.642 40.703 ;
     RECT  57.78 40.595 58.374 40.703 ;
     RECT  59.148 40.559 67.734 40.703 ;
     RECT  70.56 40.667 77.274 40.703 ;
     RECT  90.54 40.667 92.754 40.703 ;
     RECT  99.072 40.397 100.242 40.703 ;
     RECT  101.916 40.654 109.314 40.703 ;
     RECT  110.415 40.685 112.482 40.703 ;
     RECT  114.192 40.667 121.497 40.703 ;
     RECT  15.732 40.703 24.822 40.739 ;
     RECT  79.416 40.595 81.954 40.739 ;
     RECT  101.916 40.703 108.99 40.739 ;
     RECT  2.415 39.659 2.697 40.787 ;
     RECT  7.815 40.631 8.097 40.787 ;
     RECT  114.228 40.703 121.497 40.787 ;
     RECT  126.615 40.289 126.897 40.787 ;
     RECT  90.648 40.703 92.754 40.795 ;
     RECT  93.6 40.685 97.254 40.795 ;
     RECT  8.964 40.559 9.162 40.829 ;
     RECT  10.728 40.654 12.006 40.829 ;
     RECT  13.14 40.559 14.994 40.829 ;
     RECT  15.948 40.739 19.638 40.829 ;
     RECT  20.52 40.739 24.822 40.829 ;
     RECT  26.1 40.667 26.118 40.829 ;
     RECT  27.288 40.559 30.438 40.829 ;
     RECT  31.32 40.703 32.598 40.829 ;
     RECT  34.596 40.667 35.91 40.829 ;
     RECT  39.384 40.631 56.934 40.829 ;
     RECT  59.652 40.703 67.734 40.829 ;
     RECT  68.796 40.639 69.786 40.829 ;
     RECT  70.56 40.703 73.818 40.829 ;
     RECT  74.556 40.703 76.626 40.829 ;
     RECT  78.015 40.667 78.354 40.829 ;
     RECT  79.416 40.739 80.658 40.829 ;
     RECT  81.756 40.739 81.954 40.829 ;
     RECT  82.728 40.595 84.942 40.829 ;
     RECT  86.22 40.675 89.802 40.829 ;
     RECT  90.648 40.795 97.254 40.829 ;
     RECT  98.064 40.559 98.154 40.829 ;
     RECT  101.916 40.739 107.478 40.829 ;
     RECT  108.432 40.739 108.99 40.829 ;
     RECT  110.415 40.703 112.23 40.829 ;
     RECT  113.256 40.685 113.274 40.829 ;
     RECT  114.228 40.787 121.305 40.829 ;
     RECT  31.32 40.829 32.274 40.835 ;
     RECT  60.948 40.829 63.81 40.835 ;
     RECT  90.648 40.829 91.062 40.835 ;
     RECT  10.728 40.829 11.682 40.865 ;
     RECT  13.215 40.829 13.698 40.865 ;
     RECT  14.544 40.829 14.67 40.865 ;
     RECT  15.948 40.829 16.038 40.865 ;
     RECT  16.848 40.829 16.974 40.865 ;
     RECT  20.52 40.829 22.554 40.865 ;
     RECT  23.436 40.829 24.354 40.865 ;
     RECT  27.288 40.829 27.306 40.865 ;
     RECT  28.152 40.829 28.278 40.865 ;
     RECT  41.112 40.829 55.278 40.865 ;
     RECT  57.78 40.703 58.086 40.865 ;
     RECT  59.652 40.829 59.994 40.865 ;
     RECT  60.948 40.835 62.082 40.865 ;
     RECT  62.964 40.835 63.81 40.865 ;
     RECT  65.088 40.829 65.25 40.865 ;
     RECT  68.796 40.829 69.678 40.865 ;
     RECT  70.56 40.829 70.578 40.865 ;
     RECT  71.496 40.829 73.422 40.865 ;
     RECT  74.556 40.829 74.574 40.865 ;
     RECT  78.015 40.829 78.174 40.865 ;
     RECT  81.756 40.829 81.774 40.865 ;
     RECT  91.8 40.829 91.854 40.865 ;
     RECT  93.024 40.829 95.238 40.865 ;
     RECT  96.444 40.829 97.182 40.865 ;
     RECT  99.615 40.703 100.242 40.865 ;
     RECT  103.716 40.829 107.154 40.865 ;
     RECT  111.312 40.829 112.23 40.865 ;
     RECT  115.092 40.829 118.314 40.865 ;
     RECT  119.916 40.829 121.305 40.865 ;
     RECT  16.02 40.865 16.038 40.877 ;
     RECT  17.892 40.829 19.638 40.877 ;
     RECT  20.52 40.865 21.294 40.877 ;
     RECT  41.112 40.865 51.105 40.877 ;
     RECT  86.22 40.829 87.138 40.877 ;
     RECT  87.984 40.829 88.905 40.877 ;
     RECT  89.784 40.829 89.802 40.877 ;
     RECT  90.648 40.835 90.666 40.877 ;
     RECT  115.2 40.865 117.846 40.877 ;
     RECT  114.228 40.829 114.246 40.888 ;
     RECT  11.304 40.865 11.682 40.901 ;
     RECT  16.956 40.865 16.974 40.901 ;
     RECT  18.54 40.877 18.705 40.901 ;
     RECT  23.436 40.865 24.105 40.901 ;
     RECT  28.26 40.865 28.278 40.901 ;
     RECT  29.052 40.829 30.438 40.901 ;
     RECT  31.788 40.835 32.274 40.901 ;
     RECT  51.84 40.865 54.306 40.901 ;
     RECT  60.948 40.865 60.966 40.901 ;
     RECT  62.964 40.865 62.982 40.901 ;
     RECT  65.088 40.865 65.106 40.901 ;
     RECT  91.836 40.865 91.854 40.901 ;
     RECT  95.04 40.865 95.058 40.901 ;
     RECT  104.292 40.865 106.398 40.901 ;
     RECT  107.136 40.865 107.154 40.901 ;
     RECT  108.432 40.829 108.45 40.901 ;
     RECT  111.636 40.865 112.23 40.901 ;
     RECT  115.2 40.877 115.905 40.901 ;
     RECT  117.72 40.877 117.846 40.901 ;
     RECT  120.24 40.865 120.258 40.901 ;
     RECT  102.348 40.829 102.978 40.925 ;
     RECT  104.58 40.901 106.326 40.925 ;
     RECT  116.964 40.877 116.982 40.925 ;
     RECT  117.72 40.901 117.738 40.925 ;
     RECT  37.224 40.589 37.386 40.937 ;
     RECT  43.488 40.877 51.105 40.937 ;
     RECT  51.84 40.901 54.126 40.937 ;
     RECT  55.116 40.865 55.278 40.937 ;
     RECT  79.452 40.829 80.442 40.937 ;
     RECT  96.444 40.865 96.462 40.937 ;
     RECT  98.064 40.829 98.082 40.937 ;
     RECT  105.015 40.925 106.326 40.937 ;
     RECT  29.052 40.901 29.682 40.973 ;
     RECT  43.488 40.937 46.278 40.973 ;
     RECT  55.116 40.937 55.134 40.973 ;
     RECT  69.012 40.865 69.678 40.973 ;
     RECT  71.496 40.865 72.705 40.973 ;
     RECT  75.96 40.829 75.978 40.973 ;
     RECT  79.452 40.937 79.902 40.973 ;
     RECT  84.924 40.829 84.942 40.973 ;
     RECT  102.348 40.925 102.366 40.973 ;
     RECT  112.212 40.901 112.23 40.973 ;
     RECT  9.144 40.829 9.162 41.009 ;
     RECT  11.304 40.901 11.322 41.009 ;
     RECT  14.652 40.865 14.67 41.009 ;
     RECT  19.62 40.877 19.638 41.009 ;
     RECT  20.52 40.877 20.538 41.009 ;
     RECT  21.276 40.877 21.294 41.009 ;
     RECT  22.176 40.865 22.194 41.009 ;
     RECT  29.415 40.973 29.682 41.009 ;
     RECT  31.896 40.901 32.274 41.009 ;
     RECT  35.82 40.829 35.91 41.009 ;
     RECT  37.368 40.937 37.386 41.009 ;
     RECT  39.384 40.829 40.305 41.009 ;
     RECT  44.244 40.973 46.278 41.009 ;
     RECT  47.016 40.937 51.105 41.009 ;
     RECT  51.84 40.937 52.29 41.009 ;
     RECT  56.415 40.829 56.934 41.009 ;
     RECT  61.815 40.865 62.082 41.009 ;
     RECT  66.492 40.829 67.305 41.009 ;
     RECT  72.144 40.973 72.705 41.009 ;
     RECT  86.724 40.877 87.138 41.009 ;
     RECT  88.092 40.877 88.905 41.009 ;
     RECT  93.6 40.865 94.305 41.009 ;
     RECT  106.308 40.937 106.326 41.009 ;
     RECT  44.244 41.009 44.874 41.021 ;
     RECT  45.615 41.009 46.278 41.021 ;
     RECT  47.016 41.009 48.402 41.021 ;
     RECT  49.428 41.009 51.105 41.021 ;
     RECT  53.1 40.937 54.126 41.021 ;
     RECT  51.984 41.009 52.29 41.032 ;
     RECT  2.415 40.787 2.505 41.057 ;
     RECT  7.815 40.787 7.905 41.057 ;
     RECT  13.215 40.865 13.305 41.057 ;
     RECT  18.615 40.901 18.705 41.057 ;
     RECT  24.015 40.901 24.105 41.057 ;
     RECT  29.415 41.009 29.505 41.057 ;
     RECT  34.815 40.829 34.905 41.057 ;
     RECT  40.215 41.009 40.305 41.057 ;
     RECT  45.615 41.021 45.954 41.057 ;
     RECT  51.015 41.021 51.105 41.057 ;
     RECT  56.415 41.009 56.505 41.057 ;
     RECT  61.815 41.009 61.905 41.057 ;
     RECT  67.215 41.009 67.305 41.057 ;
     RECT  72.615 41.009 72.705 41.057 ;
     RECT  78.015 40.865 78.105 41.057 ;
     RECT  83.415 40.829 83.505 41.057 ;
     RECT  88.815 41.009 88.905 41.057 ;
     RECT  94.215 41.009 94.305 41.057 ;
     RECT  99.615 40.865 99.705 41.057 ;
     RECT  105.015 40.937 105.105 41.057 ;
     RECT  110.415 40.829 110.505 41.057 ;
     RECT  115.815 40.901 115.905 41.057 ;
     RECT  121.215 40.865 121.305 41.057 ;
     RECT  126.615 40.787 126.705 41.057 ;
     RECT  41.112 40.877 42.75 41.069 ;
     RECT  45.756 41.057 45.954 41.165 ;
     RECT  52.02 41.032 52.29 41.597 ;
     RECT  44.568 41.021 44.694 41.645 ;
     RECT  53.1 41.021 53.586 41.645 ;
     RECT  50.184 41.021 50.202 41.995 ;
     RECT  50.184 41.995 50.814 42.173 ;
     RECT  52.092 41.597 52.29 42.173 ;
     RECT  41.328 41.069 42.75 42.221 ;
     RECT  44.568 41.645 44.586 42.221 ;
     RECT  49.428 41.021 49.446 42.221 ;
     RECT  53.1 41.645 53.118 42.221 ;
     RECT  42.732 42.221 42.75 42.269 ;
     RECT  41.94 42.221 41.958 43.037 ;
     RECT  47.088 41.021 48.402 43.037 ;
     RECT  43.488 40.973 43.506 43.085 ;
     RECT  47.772 43.037 48.402 43.085 ;
     RECT  52.092 42.173 52.11 43.085 ;
    LAYER M4 ;
     RECT  0.06 3.456 0.097 3.672 ;
     RECT  0.097 2.88 0.137 3.672 ;
     RECT  0.137 2.88 2.408 3.48 ;
     RECT  2.401 15.984 2.408 16.872 ;
     RECT  2.408 2.148 2.512 41.052 ;
     RECT  2.512 2.418 2.704 40.782 ;
     RECT  2.704 14.208 2.819 16.872 ;
     RECT  2.704 34.032 2.909 35.352 ;
     RECT  2.704 6.576 2.963 11.4 ;
     RECT  2.704 2.88 3.269 4.536 ;
     RECT  2.963 9.12 3.443 11.4 ;
     RECT  2.704 39.312 3.457 40.296 ;
     RECT  2.819 14.208 3.629 15.384 ;
     RECT  2.909 34.032 3.665 34.152 ;
     RECT  2.704 36.432 3.697 36.456 ;
     RECT  2.704 37.44 3.697 37.464 ;
     RECT  3.697 36.432 3.731 37.464 ;
     RECT  2.963 7.968 3.737 7.992 ;
     RECT  2.704 24.48 3.773 25.608 ;
     RECT  2.819 16.848 3.877 16.872 ;
     RECT  2.704 31.392 3.925 31.416 ;
     RECT  3.877 16.416 3.964 16.872 ;
     RECT  3.925 30.72 3.985 31.416 ;
     RECT  2.704 32.448 3.985 32.568 ;
     RECT  2.704 27.168 4.057 28.968 ;
     RECT  3.985 30.72 4.097 32.568 ;
     RECT  3.697 38.592 4.165 38.616 ;
     RECT  3.629 15.36 4.201 15.384 ;
     RECT  4.165 38.448 4.205 38.616 ;
     RECT  4.097 30.72 4.241 32.376 ;
     RECT  2.963 6.576 4.273 6.6 ;
     RECT  3.773 25.152 4.277 25.608 ;
     RECT  3.964 16.848 4.309 16.872 ;
     RECT  4.241 30.72 4.309 31.944 ;
     RECT  3.629 14.208 4.417 14.232 ;
     RECT  2.704 18.048 4.417 18.168 ;
     RECT  3.443 10.416 4.501 11.4 ;
     RECT  2.704 20.592 4.501 23.4 ;
     RECT  4.201 12.912 4.547 12.936 ;
     RECT  4.201 15.36 4.547 15.72 ;
     RECT  4.273 6.288 4.549 6.6 ;
     RECT  3.443 9.12 4.549 9.144 ;
     RECT  4.057 27.168 4.549 29.064 ;
     RECT  4.501 10.32 4.588 11.544 ;
     RECT  4.549 26.784 4.595 29.064 ;
     RECT  4.595 27.936 4.601 29.064 ;
     RECT  4.417 18.048 4.633 18.696 ;
     RECT  4.595 26.784 4.636 26.808 ;
     RECT  2.909 35.232 4.637 35.352 ;
     RECT  4.549 5.664 4.669 6.6 ;
     RECT  4.549 7.584 4.669 7.608 ;
     RECT  4.309 16.848 4.669 17.064 ;
     RECT  4.633 18.048 4.669 18.744 ;
     RECT  4.417 13.968 4.693 14.232 ;
     RECT  4.547 15.36 4.693 15.384 ;
     RECT  4.693 13.968 4.739 15.384 ;
     RECT  4.739 13.968 4.741 15.048 ;
     RECT  4.669 5.664 4.745 7.608 ;
     RECT  4.741 13.44 4.781 15.048 ;
     RECT  4.745 6.816 4.789 7.608 ;
     RECT  4.549 8.688 4.789 9.144 ;
     RECT  4.789 6.816 4.835 9.144 ;
     RECT  4.277 25.152 4.849 25.368 ;
     RECT  4.745 5.664 4.961 5.688 ;
     RECT  4.588 10.32 4.961 11.4 ;
     RECT  4.669 16.848 5.077 18.744 ;
     RECT  4.835 7.872 5.101 9.144 ;
     RECT  4.961 10.32 5.101 10.344 ;
     RECT  4.501 19.776 5.123 23.4 ;
     RECT  5.123 19.776 5.133 22.824 ;
     RECT  4.205 38.448 5.164 38.52 ;
     RECT  3.731 37.104 5.173 37.464 ;
     RECT  5.164 38.448 5.173 38.472 ;
     RECT  5.133 20.064 5.184 22.824 ;
     RECT  3.269 2.88 5.245 4.008 ;
     RECT  5.209 5.136 5.245 5.16 ;
     RECT  5.245 2.88 5.293 5.16 ;
     RECT  4.849 25.104 5.353 25.368 ;
     RECT  4.345 34.176 5.461 34.2 ;
     RECT  4.601 29.04 5.501 29.064 ;
     RECT  5.461 33.888 5.509 34.2 ;
     RECT  5.509 33.84 5.533 34.2 ;
     RECT  5.533 33.6 5.569 34.2 ;
     RECT  4.961 11.376 5.605 11.4 ;
     RECT  4.309 30.432 5.641 31.944 ;
     RECT  5.077 16.512 5.653 18.744 ;
     RECT  5.353 24.96 5.677 25.368 ;
     RECT  4.637 35.328 5.677 35.352 ;
     RECT  5.653 16.512 5.699 18.84 ;
     RECT  5.605 11.376 5.708 11.976 ;
     RECT  4.835 6.816 5.749 6.84 ;
     RECT  5.173 37.104 5.789 38.472 ;
     RECT  5.101 7.872 5.795 10.344 ;
     RECT  4.781 13.44 5.893 13.464 ;
     RECT  4.781 14.736 5.893 15.048 ;
     RECT  5.795 8.736 5.897 10.344 ;
     RECT  5.569 33.12 5.965 34.2 ;
     RECT  5.677 35.232 5.965 35.352 ;
     RECT  5.641 30.192 5.969 31.944 ;
     RECT  5.897 10.08 6.001 10.344 ;
     RECT  5.708 11.376 6.001 12.456 ;
     RECT  5.699 16.512 6.001 17.352 ;
     RECT  5.317 26.4 6.181 26.424 ;
     RECT  6.001 10.08 6.217 12.456 ;
     RECT  5.893 13.44 6.217 15.048 ;
     RECT  6.217 10.08 6.253 15.048 ;
     RECT  6.001 16.272 6.253 17.352 ;
     RECT  5.184 20.064 6.253 22.728 ;
     RECT  5.969 31.68 6.253 31.944 ;
     RECT  6.253 31.68 6.289 32.04 ;
     RECT  5.965 33.12 6.289 35.352 ;
     RECT  6.253 20.064 6.365 23.304 ;
     RECT  5.965 27.696 6.401 27.72 ;
     RECT  6.289 31.68 6.433 35.352 ;
     RECT  3.457 40.272 6.433 40.296 ;
     RECT  5.677 24.672 6.469 25.368 ;
     RECT  6.181 26.4 6.469 26.664 ;
     RECT  6.433 40.128 6.473 40.296 ;
     RECT  5.699 18.672 6.541 18.84 ;
     RECT  6.365 20.064 6.541 21.48 ;
     RECT  6.253 10.08 6.653 17.352 ;
     RECT  6.433 31.68 6.757 36.024 ;
     RECT  5.789 37.152 6.757 38.472 ;
     RECT  6.473 40.128 6.757 40.152 ;
     RECT  6.757 31.68 6.803 40.152 ;
     RECT  6.613 28.176 6.865 28.2 ;
     RECT  6.541 18.672 6.901 21.48 ;
     RECT  6.653 11.376 6.973 17.352 ;
     RECT  6.901 18.528 6.973 21.48 ;
     RECT  5.749 6.624 7.153 6.84 ;
     RECT  5.969 30.192 7.153 30.408 ;
     RECT  7.153 29.76 7.369 30.408 ;
     RECT  7.369 29.76 7.405 30.696 ;
     RECT  6.803 31.68 7.405 37.32 ;
     RECT  6.469 24.672 7.573 26.664 ;
     RECT  6.653 10.08 7.693 10.104 ;
     RECT  6.973 11.376 7.693 21.48 ;
     RECT  7.573 24.672 7.729 27.192 ;
     RECT  6.865 28.176 7.729 28.488 ;
     RECT  5.293 2.88 7.808 4.776 ;
     RECT  7.153 6.24 7.808 6.84 ;
     RECT  5.897 8.736 7.808 9.096 ;
     RECT  7.693 10.08 7.808 21.48 ;
     RECT  6.365 22.512 7.808 23.304 ;
     RECT  7.729 24.672 7.808 28.488 ;
     RECT  7.405 29.76 7.808 37.32 ;
     RECT  6.803 38.352 7.808 40.152 ;
     RECT  7.808 2.148 7.912 41.052 ;
     RECT  7.912 2.418 8.104 40.782 ;
     RECT  8.104 24.576 8.243 34.728 ;
     RECT  8.104 39.888 8.243 40.584 ;
     RECT  8.243 24.576 8.38 27.912 ;
     RECT  8.104 13.536 8.525 21.528 ;
     RECT  8.243 39.888 8.633 40.152 ;
     RECT  8.243 28.992 8.777 34.728 ;
     RECT  8.777 28.992 8.849 34.392 ;
     RECT  8.104 22.512 8.867 23.304 ;
     RECT  8.104 35.76 8.885 38.808 ;
     RECT  8.104 10.08 9.011 11.448 ;
     RECT  8.525 14.688 9.065 21.528 ;
     RECT  8.867 23.28 9.097 23.304 ;
     RECT  9.065 19.104 9.107 21.528 ;
     RECT  8.104 8.688 9.137 9.096 ;
     RECT  8.885 38.544 9.137 38.808 ;
     RECT  8.104 6 9.269 7.032 ;
     RECT  8.885 35.76 9.277 37.32 ;
     RECT  8.104 2.88 9.5 4.824 ;
     RECT  9.107 19.776 9.529 21.528 ;
     RECT  9.5 2.832 9.587 4.824 ;
     RECT  8.525 13.536 9.601 13.704 ;
     RECT  9.065 14.688 9.601 17.832 ;
     RECT  8.633 39.888 9.601 39.912 ;
     RECT  9.529 19.776 9.613 22.248 ;
     RECT  9.011 10.224 9.673 11.448 ;
     RECT  8.104 12.48 9.673 12.504 ;
     RECT  9.601 13.536 9.683 17.832 ;
     RECT  9.673 10.224 9.809 12.504 ;
     RECT  9.683 13.536 9.821 17.352 ;
     RECT  9.809 10.224 9.829 12.552 ;
     RECT  9.821 13.536 9.829 15.24 ;
     RECT  9.587 2.88 9.853 4.824 ;
     RECT  9.829 10.224 9.875 15.24 ;
     RECT  9.821 16.272 9.929 17.352 ;
     RECT  9.853 2.88 10.117 4.968 ;
     RECT  9.269 6 10.117 7.416 ;
     RECT  8.38 24.912 10.117 27.912 ;
     RECT  8.849 28.992 10.117 34.248 ;
     RECT  9.137 8.688 10.141 8.712 ;
     RECT  9.875 10.224 10.141 13.704 ;
     RECT  9.097 23.28 10.141 23.928 ;
     RECT  9.137 38.544 10.177 38.616 ;
     RECT  9.929 16.272 10.181 17.208 ;
     RECT  9.875 14.688 10.289 15.24 ;
     RECT  9.277 35.712 10.357 37.32 ;
     RECT  10.177 38.544 10.357 38.76 ;
     RECT  10.357 35.712 10.393 38.76 ;
     RECT  9.601 39.84 10.393 39.912 ;
     RECT  10.141 22.464 10.444 23.928 ;
     RECT  10.444 22.8 10.453 23.928 ;
     RECT  10.117 24.912 10.453 34.248 ;
     RECT  10.453 22.8 10.499 34.248 ;
     RECT  10.289 14.736 10.505 15.24 ;
     RECT  10.393 35.712 10.573 40.632 ;
     RECT  9.613 19.776 10.645 21.384 ;
     RECT  10.117 2.88 10.681 7.416 ;
     RECT  10.141 8.688 10.681 13.704 ;
     RECT  10.573 35.472 10.681 40.632 ;
     RECT  10.681 35.424 10.753 40.632 ;
     RECT  10.181 17.184 10.829 17.208 ;
     RECT  10.499 23.328 10.861 34.248 ;
     RECT  10.753 35.328 10.861 40.632 ;
     RECT  10.645 19.776 11.009 21.528 ;
     RECT  11.009 19.776 11.153 20.136 ;
     RECT  10.861 23.328 11.293 40.632 ;
     RECT  11.293 23.328 11.405 40.872 ;
     RECT  10.505 14.736 11.545 14.76 ;
     RECT  11.509 15.744 11.545 15.768 ;
     RECT  11.009 21.12 11.657 21.528 ;
     RECT  11.405 23.328 11.657 39.336 ;
     RECT  11.405 40.608 11.693 40.872 ;
     RECT  10.681 2.88 11.725 13.704 ;
     RECT  11.545 14.736 11.725 17.112 ;
     RECT  11.657 23.808 11.873 39.336 ;
     RECT  11.725 2.88 11.981 17.112 ;
     RECT  11.657 21.168 12.085 21.528 ;
     RECT  11.941 0.096 12.236 0.12 ;
     RECT  12.236 0.096 12.323 0.552 ;
     RECT  11.981 2.88 12.421 8.856 ;
     RECT  12.085 21.168 12.733 21.576 ;
     RECT  11.981 10.272 12.757 17.112 ;
     RECT  11.153 19.776 12.841 19.8 ;
     RECT  12.733 21.168 12.841 21.768 ;
     RECT  12.553 22.752 12.841 22.776 ;
     RECT  12.013 1.728 12.853 1.752 ;
     RECT  12.421 2.736 12.853 8.856 ;
     RECT  11.873 23.808 12.949 38.712 ;
     RECT  12.853 1.152 13.091 8.856 ;
     RECT  12.757 10.272 13.093 17.88 ;
     RECT  12.841 19.44 13.093 19.8 ;
     RECT  13.091 1.728 13.208 8.856 ;
     RECT  13.093 10.272 13.208 19.848 ;
     RECT  12.841 21.168 13.208 22.776 ;
     RECT  12.949 23.808 13.208 39.528 ;
     RECT  11.693 40.608 13.208 40.632 ;
     RECT  13.208 1.728 13.312 41.052 ;
     RECT  12.323 0.096 13.333 0.168 ;
     RECT  13.312 1.728 13.504 40.782 ;
     RECT  13.504 10.272 13.601 15.288 ;
     RECT  13.504 1.728 13.715 9.192 ;
     RECT  13.504 16.368 13.745 22.776 ;
     RECT  13.504 23.808 13.745 40.632 ;
     RECT  13.745 36.816 13.773 40.632 ;
     RECT  13.745 16.368 13.781 21.144 ;
     RECT  13.773 36.816 13.817 40.44 ;
     RECT  13.745 23.808 13.853 35.832 ;
     RECT  13.781 18.96 13.925 21.144 ;
     RECT  13.925 19.104 13.961 21.144 ;
     RECT  13.333 0.096 14.293 0.552 ;
     RECT  13.601 10.272 14.393 14.904 ;
     RECT  14.393 13.968 14.465 14.904 ;
     RECT  13.853 23.808 14.485 35.352 ;
     RECT  13.745 22.32 14.531 22.776 ;
     RECT  14.393 10.272 14.533 12.888 ;
     RECT  14.485 23.76 14.573 35.352 ;
     RECT  13.817 36.816 14.609 39.144 ;
     RECT  13.781 16.368 14.749 16.92 ;
     RECT  14.609 36.816 14.789 38.616 ;
     RECT  13.715 2.88 14.821 9.192 ;
     RECT  14.533 10.224 14.821 12.888 ;
     RECT  14.531 22.32 14.821 22.344 ;
     RECT  14.465 13.968 14.825 14.76 ;
     RECT  14.789 36.816 14.857 38.568 ;
     RECT  14.821 22.224 14.861 22.344 ;
     RECT  14.857 36.336 14.861 38.568 ;
     RECT  13.961 19.104 15.001 21.048 ;
     RECT  14.293 0.096 15.02 0.6 ;
     RECT  13.715 1.728 15.02 1.752 ;
     RECT  15.02 0.096 15.107 1.752 ;
     RECT  14.749 16.128 15.289 16.92 ;
     RECT  14.573 23.808 15.361 35.352 ;
     RECT  14.861 36.336 15.361 38.472 ;
     RECT  14.821 2.88 15.505 12.888 ;
     RECT  14.825 13.968 15.505 14.664 ;
     RECT  15.289 16.128 15.833 17.16 ;
     RECT  15.833 16.128 15.901 16.392 ;
     RECT  15.107 1.728 15.937 1.752 ;
     RECT  15.505 2.88 15.937 14.664 ;
     RECT  13.817 40.416 15.937 40.44 ;
     RECT  15.937 40.416 16.009 40.824 ;
     RECT  14.861 22.224 16.013 22.248 ;
     RECT  16.009 40.32 16.081 40.872 ;
     RECT  15.107 0.096 16.117 0.552 ;
     RECT  15.937 1.728 16.117 14.664 ;
     RECT  16.081 40.272 16.297 40.872 ;
     RECT  16.117 0.096 16.373 14.664 ;
     RECT  16.373 0.096 16.445 0.12 ;
     RECT  15.001 19.104 16.765 21.096 ;
     RECT  16.765 18.96 16.837 21.096 ;
     RECT  16.297 40.08 16.837 40.872 ;
     RECT  16.796 22.752 16.883 22.776 ;
     RECT  16.373 1.104 16.931 14.664 ;
     RECT  16.931 1.152 16.985 14.664 ;
     RECT  16.985 1.68 17.129 14.664 ;
     RECT  15.901 16.032 17.341 16.392 ;
     RECT  16.513 17.616 17.341 17.64 ;
     RECT  15.361 23.808 17.341 38.472 ;
     RECT  17.129 1.728 17.353 14.664 ;
     RECT  17.353 11.184 17.449 14.664 ;
     RECT  17.341 16.032 17.449 16.584 ;
     RECT  17.449 11.184 17.557 16.584 ;
     RECT  17.341 17.616 17.557 17.784 ;
     RECT  17.557 11.184 17.701 17.784 ;
     RECT  16.837 18.96 17.701 21.672 ;
     RECT  17.341 23.664 17.881 38.472 ;
     RECT  17.881 23.664 17.989 38.52 ;
     RECT  17.989 23.664 18.061 38.664 ;
     RECT  16.837 39.744 18.061 40.872 ;
     RECT  17.701 11.184 18.097 21.672 ;
     RECT  18.097 11.184 18.133 21.768 ;
     RECT  18.061 23.664 18.133 40.872 ;
     RECT  17.749 0.096 18.373 0.12 ;
     RECT  18.373 0.096 18.425 0.216 ;
     RECT  18.133 11.184 18.457 22.008 ;
     RECT  18.457 11.184 18.469 22.488 ;
     RECT  17.353 1.728 18.608 9.912 ;
     RECT  18.469 10.896 18.608 22.488 ;
     RECT  18.133 23.568 18.608 40.872 ;
     RECT  18.608 1.728 18.712 41.052 ;
     RECT  18.425 0.144 18.956 0.216 ;
     RECT  18.712 1.728 18.956 40.872 ;
     RECT  18.956 0.144 19.565 40.872 ;
     RECT  19.565 0.096 19.649 40.872 ;
     RECT  19.649 0.144 19.763 40.872 ;
     RECT  19.763 0.144 20.627 38.52 ;
     RECT  19.763 39.84 20.729 40.872 ;
     RECT  20.627 0.24 20.765 38.52 ;
     RECT  20.765 0.528 20.963 38.52 ;
     RECT  20.963 1.152 20.981 38.52 ;
     RECT  20.981 1.152 21.125 38.472 ;
     RECT  20.729 39.84 21.197 40.584 ;
     RECT  21.125 1.152 21.629 21.192 ;
     RECT  21.629 1.152 21.809 21.144 ;
     RECT  21.809 1.152 22.211 20.904 ;
     RECT  21.197 40.56 22.345 40.584 ;
     RECT  21.125 22.224 22.457 38.472 ;
     RECT  21.925 0.144 22.489 0.168 ;
     RECT  22.457 22.224 22.637 23.4 ;
     RECT  22.457 24.432 22.777 38.472 ;
     RECT  22.777 24.432 23.029 38.712 ;
     RECT  22.345 40.32 23.029 40.584 ;
     RECT  22.489 0.144 23.141 0.696 ;
     RECT  23.141 0.144 23.597 0.6 ;
     RECT  23.597 0.096 23.789 0.6 ;
     RECT  22.211 1.728 24.008 20.904 ;
     RECT  22.637 22.464 24.008 23.4 ;
     RECT  23.029 24.432 24.008 40.584 ;
     RECT  24.008 1.728 24.112 41.052 ;
     RECT  24.112 1.728 24.304 40.782 ;
     RECT  24.304 1.728 24.545 20.904 ;
     RECT  24.545 1.728 24.563 20.664 ;
     RECT  23.789 0.096 24.949 0.552 ;
     RECT  24.563 1.728 24.949 1.752 ;
     RECT  24.949 0.096 25.091 1.752 ;
     RECT  24.304 22.176 25.091 23.4 ;
     RECT  25.091 0.096 25.517 0.6 ;
     RECT  25.517 0.144 25.553 0.6 ;
     RECT  25.091 1.728 25.58 1.752 ;
     RECT  24.563 2.88 25.58 20.664 ;
     RECT  25.091 22.704 25.669 23.4 ;
     RECT  24.304 24.432 25.669 40.392 ;
     RECT  25.58 1.728 25.765 20.664 ;
     RECT  25.669 22.704 25.769 40.392 ;
     RECT  25.765 1.728 25.949 20.76 ;
     RECT  25.769 22.704 26.093 40.152 ;
     RECT  26.093 22.704 26.165 39.816 ;
     RECT  25.949 1.728 26.252 1.8 ;
     RECT  26.252 1.68 26.389 1.8 ;
     RECT  26.165 22.704 26.417 39.768 ;
     RECT  26.389 1.152 26.525 1.8 ;
     RECT  25.553 0.144 26.773 0.168 ;
     RECT  25.949 2.784 26.981 20.76 ;
     RECT  26.981 2.784 27.065 21.672 ;
     RECT  26.525 1.728 27.154 1.8 ;
     RECT  27.065 2.784 27.154 21.144 ;
     RECT  26.773 0.144 27.241 0.312 ;
     RECT  27.241 0.096 27.389 0.312 ;
     RECT  27.389 0.096 27.605 0.264 ;
     RECT  26.417 22.704 27.709 23.016 ;
     RECT  26.417 24.144 27.709 39.768 ;
     RECT  27.154 1.728 27.749 21.144 ;
     RECT  27.749 1.728 27.821 1.752 ;
     RECT  27.709 22.704 27.889 39.768 ;
     RECT  27.749 2.736 28.217 21.144 ;
     RECT  27.889 22.176 28.253 39.768 ;
     RECT  28.253 39.312 28.753 39.768 ;
     RECT  28.753 39.312 28.789 40.152 ;
     RECT  28.789 39.312 29.041 40.44 ;
     RECT  27.605 0.096 29.153 0.12 ;
     RECT  29.041 39.312 29.257 40.968 ;
     RECT  28.217 2.784 29.408 21.144 ;
     RECT  28.253 22.176 29.408 37.704 ;
     RECT  29.257 38.736 29.408 40.968 ;
     RECT  29.408 2.148 29.512 41.052 ;
     RECT  29.512 2.148 29.693 40.968 ;
     RECT  29.693 2.148 29.704 40.782 ;
     RECT  29.704 23.664 29.801 23.688 ;
     RECT  29.704 2.148 29.833 21.288 ;
     RECT  29.704 24.912 29.909 40.44 ;
     RECT  29.909 40.32 30.269 40.44 ;
     RECT  29.909 24.912 30.341 39.336 ;
     RECT  29.977 0.528 30.562 0.552 ;
     RECT  30.562 0.528 30.563 0.6 ;
     RECT  30.563 0.576 30.673 0.6 ;
     RECT  30.341 24.912 30.809 38.232 ;
     RECT  30.805 23.328 30.889 23.352 ;
     RECT  30.809 24.912 30.901 37.416 ;
     RECT  29.833 1.728 30.953 21.288 ;
     RECT  30.901 23.904 30.989 37.416 ;
     RECT  30.989 24.096 31.169 37.416 ;
     RECT  30.341 39.312 31.309 39.336 ;
     RECT  30.269 40.416 31.309 40.44 ;
     RECT  31.169 24.096 31.385 26.328 ;
     RECT  31.169 27.408 31.421 37.416 ;
     RECT  31.309 40.416 31.885 40.824 ;
     RECT  31.421 35.952 31.909 37.416 ;
     RECT  31.309 38.976 31.909 39.336 ;
     RECT  31.909 35.952 31.916 39.336 ;
     RECT  31.885 40.416 31.916 40.968 ;
     RECT  30.953 2.208 31.957 21.288 ;
     RECT  31.597 22.416 31.957 22.44 ;
     RECT  31.916 35.952 32.003 40.968 ;
     RECT  31.957 2.208 32.029 22.44 ;
     RECT  32.003 35.952 32.141 39 ;
     RECT  32.029 2.208 32.147 22.584 ;
     RECT  31.385 26.016 32.149 26.328 ;
     RECT  31.421 27.408 32.149 34.728 ;
     RECT  32.147 2.256 32.177 22.584 ;
     RECT  32.177 2.256 32.249 22.44 ;
     RECT  32.141 38.976 32.285 39 ;
     RECT  32.003 40.128 32.285 40.968 ;
     RECT  32.249 2.256 32.321 22.344 ;
     RECT  32.321 2.784 32.465 22.344 ;
     RECT  31.385 24.096 32.497 24.936 ;
     RECT  32.149 26.016 32.497 34.728 ;
     RECT  32.497 24.096 32.537 34.728 ;
     RECT  32.537 26.64 32.605 34.728 ;
     RECT  32.141 35.952 32.605 37.416 ;
     RECT  32.537 24.096 32.789 25.272 ;
     RECT  32.605 26.64 33.145 37.416 ;
     RECT  33.145 26.64 33.293 37.464 ;
     RECT  33.541 38.88 33.721 38.904 ;
     RECT  32.465 2.88 33.733 22.344 ;
     RECT  33.721 38.736 33.793 38.904 ;
     RECT  33.793 38.448 34.261 38.904 ;
     RECT  32.789 24.096 34.333 25.224 ;
     RECT  32.285 40.128 34.333 40.44 ;
     RECT  33.733 2.784 34.765 22.344 ;
     RECT  34.333 23.568 34.765 25.224 ;
     RECT  34.765 2.496 34.808 25.224 ;
     RECT  33.293 27.072 34.808 37.464 ;
     RECT  34.261 38.448 34.808 39 ;
     RECT  34.333 40.08 34.808 40.44 ;
     RECT  34.808 2.148 34.912 41.052 ;
     RECT  34.912 2.418 35.104 40.782 ;
     RECT  35.104 31.728 35.273 35.496 ;
     RECT  35.273 31.728 35.453 35.016 ;
     RECT  35.104 26.208 35.597 30.648 ;
     RECT  35.104 38.784 35.741 40.44 ;
     RECT  35.104 2.496 35.777 25.224 ;
     RECT  35.741 38.784 35.891 39.336 ;
     RECT  35.453 31.776 36.457 35.016 ;
     RECT  35.597 26.208 36.497 30.168 ;
     RECT  36.497 26.208 36.533 29.112 ;
     RECT  36.497 30.144 36.613 30.168 ;
     RECT  36.457 31.776 36.613 35.304 ;
     RECT  35.104 36.672 36.641 37.464 ;
     RECT  36.613 30.144 36.659 35.304 ;
     RECT  36.659 31.104 36.705 35.304 ;
     RECT  36.705 32.448 36.899 35.304 ;
     RECT  36.899 32.496 37.037 35.304 ;
     RECT  37.037 32.736 37.073 35.304 ;
     RECT  35.777 2.496 37.325 25.08 ;
     RECT  37.325 2.64 37.361 25.08 ;
     RECT  36.641 36.672 37.861 36.792 ;
     RECT  37.073 35.28 37.897 35.304 ;
     RECT  37.361 24.528 37.933 25.08 ;
     RECT  36.533 26.208 37.933 28.392 ;
     RECT  37.933 24.528 37.973 28.392 ;
     RECT  35.741 40.416 38.005 40.44 ;
     RECT  36.705 31.104 38.012 31.128 ;
     RECT  37.073 32.736 38.012 34.104 ;
     RECT  35.891 38.784 38.012 38.808 ;
     RECT  38.005 40.416 38.012 40.584 ;
     RECT  37.897 35.28 38.041 35.352 ;
     RECT  37.861 36.672 38.041 37.608 ;
     RECT  38.012 38.784 38.077 40.584 ;
     RECT  38.012 31.104 38.081 34.104 ;
     RECT  37.973 27.072 38.108 28.392 ;
     RECT  38.108 27.072 38.147 28.92 ;
     RECT  38.147 27.168 38.195 28.92 ;
     RECT  38.041 35.28 38.245 37.608 ;
     RECT  38.077 38.64 38.245 40.584 ;
     RECT  37.361 2.64 38.329 23.304 ;
     RECT  38.245 35.28 38.332 40.584 ;
     RECT  38.329 2.64 38.509 23.352 ;
     RECT  37.973 24.528 38.509 25.848 ;
     RECT  38.332 38.64 38.585 40.584 ;
     RECT  38.332 35.28 38.725 37.608 ;
     RECT  38.725 35.232 38.761 37.608 ;
     RECT  38.195 27.168 38.945 28.44 ;
     RECT  38.081 31.104 39.061 33.864 ;
     RECT  38.761 34.944 39.061 37.608 ;
     RECT  38.509 2.64 39.265 25.848 ;
     RECT  38.945 27.168 39.265 27.432 ;
     RECT  39.061 31.104 39.265 37.608 ;
     RECT  38.585 38.688 39.445 40.584 ;
     RECT  38.945 28.416 39.913 28.44 ;
     RECT  39.265 30.96 40.021 37.608 ;
     RECT  39.445 38.688 40.021 40.68 ;
     RECT  40.021 30.336 40.069 40.68 ;
     RECT  39.913 28.416 40.201 29.064 ;
     RECT  40.069 30.048 40.201 40.68 ;
     RECT  39.265 2.64 40.208 27.432 ;
     RECT  40.201 28.416 40.208 40.68 ;
     RECT  40.208 2.148 40.312 41.052 ;
     RECT  40.312 2.418 40.504 41.052 ;
     RECT  40.504 23.664 40.601 41.052 ;
     RECT  40.601 31.104 40.673 41.052 ;
     RECT  40.601 23.664 40.737 29.832 ;
     RECT  40.737 23.664 40.787 27.912 ;
     RECT  40.673 31.296 41.101 41.052 ;
     RECT  40.787 23.664 41.213 25.128 ;
     RECT  41.101 31.296 41.555 41.064 ;
     RECT  40.737 28.944 41.749 29.832 ;
     RECT  41.555 31.296 41.749 39.384 ;
     RECT  41.317 42.192 41.929 42.216 ;
     RECT  40.504 2.64 42.001 22.344 ;
     RECT  40.787 26.112 42.001 27.912 ;
     RECT  41.749 28.944 42.001 39.384 ;
     RECT  42.001 2.64 42.037 22.536 ;
     RECT  41.213 23.664 42.037 25.032 ;
     RECT  41.929 42.192 42.037 43.032 ;
     RECT  42.037 42.192 42.179 43.08 ;
     RECT  41.555 40.416 42.467 41.064 ;
     RECT  42.001 26.112 42.677 39.384 ;
     RECT  42.467 40.416 42.677 41.016 ;
     RECT  42.037 2.64 42.721 25.032 ;
     RECT  42.677 26.112 42.721 41.016 ;
     RECT  42.721 2.64 42.755 41.016 ;
     RECT  42.755 2.64 42.757 40.968 ;
     RECT  42.757 2.544 42.905 40.968 ;
     RECT  42.179 42.192 43.043 43.032 ;
     RECT  42.905 2.544 43.225 22.344 ;
     RECT  43.225 2.256 43.331 22.344 ;
     RECT  43.043 43.008 43.477 43.032 ;
     RECT  43.477 43.008 43.619 43.08 ;
     RECT  42.905 23.328 44.149 40.968 ;
     RECT  43.619 43.008 44.243 43.032 ;
     RECT  43.331 2.496 44.305 22.344 ;
     RECT  44.149 23.328 44.305 41.016 ;
     RECT  44.305 2.496 44.381 41.016 ;
     RECT  44.381 24.912 44.665 41.016 ;
     RECT  44.557 42.192 44.665 42.216 ;
     RECT  44.381 2.496 45.157 23.88 ;
     RECT  44.665 24.912 45.349 42.216 ;
     RECT  45.157 2.256 45.421 23.88 ;
     RECT  45.349 24.912 45.421 43.032 ;
     RECT  45.421 2.256 45.608 43.032 ;
     RECT  45.608 2.148 45.712 43.032 ;
     RECT  45.712 2.352 45.965 43.032 ;
     RECT  45.965 42.096 46.115 43.032 ;
     RECT  46.115 42.96 46.165 43.032 ;
     RECT  45.965 2.352 46.892 41.016 ;
     RECT  46.892 2.256 46.979 41.016 ;
     RECT  46.165 42.96 47.441 43.08 ;
     RECT  46.979 2.352 47.477 41.016 ;
     RECT  47.441 43.008 48.413 43.08 ;
     RECT  47.477 2.64 48.589 41.016 ;
     RECT  48.565 42.816 48.803 42.936 ;
     RECT  48.589 2.496 50.029 41.016 ;
     RECT  49.417 42.192 50.173 42.216 ;
     RECT  50.173 42.144 50.725 42.216 ;
     RECT  50.725 42.144 50.78 43.032 ;
     RECT  50.78 42 50.867 43.032 ;
     RECT  50.029 2.256 51.008 41.016 ;
     RECT  50.867 42.096 51.011 43.032 ;
     RECT  51.011 43.008 51.107 43.032 ;
     RECT  51.008 2.148 51.112 41.052 ;
     RECT  51.112 2.418 51.304 41.052 ;
     RECT  51.304 25.008 51.925 41.052 ;
     RECT  51.304 2.64 51.971 23.976 ;
     RECT  51.925 25.008 52.049 41.592 ;
     RECT  52.049 25.008 52.085 40.968 ;
     RECT  51.733 43.056 52.117 43.08 ;
     RECT  52.117 42.144 52.121 43.08 ;
     RECT  52.121 42.144 52.301 42.168 ;
     RECT  52.085 25.008 52.373 40.536 ;
     RECT  52.373 25.008 52.451 40.488 ;
     RECT  53.089 42.192 53.516 42.216 ;
     RECT  51.971 2.64 53.557 23.928 ;
     RECT  52.451 25.008 53.557 39.384 ;
     RECT  53.516 41.616 53.603 42.216 ;
     RECT  53.557 2.64 53.644 39.384 ;
     RECT  53.644 24.96 53.653 39.384 ;
     RECT  52.451 40.416 53.653 40.488 ;
     RECT  53.653 24.96 53.669 40.488 ;
     RECT  53.603 42.192 53.795 42.216 ;
     RECT  53.669 28.896 54.037 40.488 ;
     RECT  54.037 28.896 54.137 41.016 ;
     RECT  54.137 28.896 54.317 40.728 ;
     RECT  53.644 2.64 54.709 23.928 ;
     RECT  54.317 28.896 54.853 40.536 ;
     RECT  53.669 24.96 55.033 27.768 ;
     RECT  54.853 28.8 55.033 40.536 ;
     RECT  55.033 24.96 55.333 40.536 ;
     RECT  55.333 24.96 55.397 40.584 ;
     RECT  55.397 36 55.433 40.584 ;
     RECT  54.709 2.544 55.933 23.928 ;
     RECT  55.397 24.96 55.933 35.016 ;
     RECT  55.933 2.544 56.408 35.016 ;
     RECT  55.433 36 56.408 38.76 ;
     RECT  55.433 39.744 56.408 40.584 ;
     RECT  56.408 2.148 56.512 41.052 ;
     RECT  56.512 2.304 56.704 40.782 ;
     RECT  56.704 2.304 56.981 34.104 ;
     RECT  56.704 36.336 57.011 40.392 ;
     RECT  56.704 35.232 57.125 35.256 ;
     RECT  57.011 40.368 57.697 40.392 ;
     RECT  56.981 28.8 57.737 34.104 ;
     RECT  57.011 36.336 57.913 39.24 ;
     RECT  57.913 35.952 58.025 39.24 ;
     RECT  57.737 28.8 58.097 33.96 ;
     RECT  56.981 2.304 58.133 27.768 ;
     RECT  58.025 36.336 58.165 39.24 ;
     RECT  57.697 40.368 58.165 40.44 ;
     RECT  58.165 36.336 58.385 40.44 ;
     RECT  58.133 2.64 58.988 27.768 ;
     RECT  58.097 28.8 58.988 32.472 ;
     RECT  58.097 33.504 59.281 33.96 ;
     RECT  59.281 33.456 59.425 33.96 ;
     RECT  58.385 36.336 59.569 39.816 ;
     RECT  59.425 33.456 59.713 34.008 ;
     RECT  59.641 35.328 59.713 35.352 ;
     RECT  59.713 33.456 59.785 35.352 ;
     RECT  59.569 36.336 59.785 40.152 ;
     RECT  59.785 33.456 60.041 40.152 ;
     RECT  58.988 2.64 60.277 32.472 ;
     RECT  60.041 33.456 60.277 39.912 ;
     RECT  60.277 2.64 60.508 39.912 ;
     RECT  60.508 39.888 61.009 39.912 ;
     RECT  60.508 2.64 61.153 38.808 ;
     RECT  61.153 2.256 61.693 38.808 ;
     RECT  61.009 39.888 61.693 40.344 ;
     RECT  61.693 2.256 61.808 40.344 ;
     RECT  61.808 2.148 61.912 41.052 ;
     RECT  61.912 2.208 62.104 40.824 ;
     RECT  62.104 35.664 62.489 40.824 ;
     RECT  62.489 35.664 62.741 39.72 ;
     RECT  62.741 35.664 62.777 36.12 ;
     RECT  62.104 31.344 62.813 34.488 ;
     RECT  62.741 37.296 62.819 39.72 ;
     RECT  62.489 40.8 62.819 40.824 ;
     RECT  62.813 31.44 62.867 34.488 ;
     RECT  62.104 2.208 62.957 29.784 ;
     RECT  62.867 34.368 63.065 34.488 ;
     RECT  62.957 2.208 63.107 29.592 ;
     RECT  62.867 31.44 63.713 33.048 ;
     RECT  62.777 35.856 63.853 36.12 ;
     RECT  62.819 37.296 63.853 38.952 ;
     RECT  63.713 31.44 63.893 32.904 ;
     RECT  63.107 2.208 63.965 28.824 ;
     RECT  63.065 34.416 64.105 34.488 ;
     RECT  63.853 35.856 64.105 38.952 ;
     RECT  64.105 34.416 64.141 38.952 ;
     RECT  64.141 34.416 64.181 39.72 ;
     RECT  63.965 2.208 64.253 24.264 ;
     RECT  64.253 2.496 64.325 24.264 ;
     RECT  63.893 31.44 64.469 32.28 ;
     RECT  63.965 25.536 64.969 28.824 ;
     RECT  64.469 31.44 64.979 32.088 ;
     RECT  64.969 25.44 65.185 28.824 ;
     RECT  64.325 2.544 65.261 24.264 ;
     RECT  64.979 31.44 65.324 31.848 ;
     RECT  65.261 2.592 65.329 24.264 ;
     RECT  65.185 25.44 65.329 29.64 ;
     RECT  65.324 30.768 65.333 31.848 ;
     RECT  65.329 2.592 65.365 29.64 ;
     RECT  65.333 30.768 65.365 31.8 ;
     RECT  64.681 33.264 65.401 33.336 ;
     RECT  65.365 2.592 65.411 31.8 ;
     RECT  65.401 33.168 65.473 33.336 ;
     RECT  64.181 34.464 65.473 39.72 ;
     RECT  65.473 33.168 65.585 39.72 ;
     RECT  65.585 33.168 65.761 38.424 ;
     RECT  65.585 39.696 65.873 39.72 ;
     RECT  65.411 31.44 66.325 31.8 ;
     RECT  65.761 33.12 66.325 38.424 ;
     RECT  65.411 2.592 66.481 30.12 ;
     RECT  66.325 31.44 66.481 38.424 ;
     RECT  66.481 2.592 67.165 38.424 ;
     RECT  67.165 2.592 67.208 39.336 ;
     RECT  64.213 41.376 67.208 41.4 ;
     RECT  67.208 2.148 67.312 41.4 ;
     RECT  67.312 2.418 67.504 41.4 ;
     RECT  67.504 33.648 67.889 40.248 ;
     RECT  67.889 33.648 68.485 39.24 ;
     RECT  67.504 2.64 68.785 32.328 ;
     RECT  68.485 33.312 68.785 39.24 ;
     RECT  67.889 40.224 68.785 40.248 ;
     RECT  67.504 41.376 68.785 41.4 ;
     RECT  68.785 2.64 68.933 39.24 ;
     RECT  68.933 34.992 68.965 39.24 ;
     RECT  68.785 40.224 68.965 41.4 ;
     RECT  68.933 2.64 69.347 34.008 ;
     RECT  68.965 34.992 69.443 41.4 ;
     RECT  69.443 35.424 69.617 41.4 ;
     RECT  69.617 35.424 69.689 38.712 ;
     RECT  69.347 2.64 70.301 33.672 ;
     RECT  70.301 2.64 70.405 29.064 ;
     RECT  70.301 30.048 70.477 33.672 ;
     RECT  70.405 2.256 70.492 29.064 ;
     RECT  69.689 35.424 70.517 38.472 ;
     RECT  70.517 35.424 70.733 38.232 ;
     RECT  70.477 30.048 71.017 34.44 ;
     RECT  70.733 35.424 71.017 37.368 ;
     RECT  69.617 39.744 71.593 41.4 ;
     RECT  71.017 30.048 71.881 37.368 ;
     RECT  70.492 2.496 71.893 29.064 ;
     RECT  71.881 30.048 71.893 37.608 ;
     RECT  71.893 2.496 71.948 37.608 ;
     RECT  71.948 2.496 72.469 37.992 ;
     RECT  71.593 39.024 72.469 41.4 ;
     RECT  72.469 2.496 72.608 41.4 ;
     RECT  72.608 2.148 72.712 41.4 ;
     RECT  72.712 2.418 72.904 41.4 ;
     RECT  72.904 35.424 74.153 41.4 ;
     RECT  72.904 2.64 74.533 34.392 ;
     RECT  74.533 2.256 74.729 34.392 ;
     RECT  74.153 35.424 75.413 39.096 ;
     RECT  75.413 35.424 75.628 38.664 ;
     RECT  74.729 2.64 75.98 34.392 ;
     RECT  75.628 35.424 75.98 38.52 ;
     RECT  75.98 2.64 76.067 38.52 ;
     RECT  74.153 40.32 76.345 41.4 ;
     RECT  76.067 35.424 76.633 38.52 ;
     RECT  76.633 35.424 76.957 39 ;
     RECT  76.345 40.176 76.957 41.4 ;
     RECT  76.067 2.64 77.132 34.44 ;
     RECT  77.132 2.256 77.389 34.44 ;
     RECT  76.957 35.424 77.389 41.4 ;
     RECT  77.389 2.256 78.008 41.4 ;
     RECT  78.008 2.148 78.112 41.4 ;
     RECT  78.112 2.304 78.797 41.4 ;
     RECT  78.797 2.304 79.768 37.08 ;
     RECT  79.768 2.304 80.129 37.128 ;
     RECT  80.129 2.64 80.149 37.128 ;
     RECT  78.797 38.16 80.149 41.4 ;
     RECT  80.149 2.64 80.669 41.4 ;
     RECT  80.669 2.64 80.849 39.864 ;
     RECT  80.849 2.64 81.029 39.816 ;
     RECT  81.029 2.64 81.097 36.36 ;
     RECT  81.029 37.872 81.281 39.816 ;
     RECT  81.097 2.352 82.037 36.36 ;
     RECT  81.281 39.792 82.037 39.816 ;
     RECT  81.281 37.872 82.181 38.76 ;
     RECT  82.037 2.64 82.361 36.36 ;
     RECT  80.669 41.376 82.897 41.4 ;
     RECT  82.897 40.464 83.293 41.4 ;
     RECT  82.361 2.64 83.329 34.2 ;
     RECT  82.361 35.232 83.329 36.36 ;
     RECT  83.329 2.64 83.408 36.36 ;
     RECT  82.181 38.736 83.408 38.76 ;
     RECT  83.293 40.368 83.408 41.4 ;
     RECT  83.408 2.148 83.512 41.4 ;
     RECT  83.512 2.256 83.704 41.4 ;
     RECT  83.704 38.448 83.873 38.76 ;
     RECT  83.704 2.256 84.323 36.36 ;
     RECT  84.323 30.96 84.377 36.36 ;
     RECT  84.323 2.256 84.485 29.688 ;
     RECT  84.377 30.96 84.593 32.088 ;
     RECT  84.377 33.072 84.953 36.36 ;
     RECT  83.873 38.688 85.097 38.76 ;
     RECT  84.953 33.264 85.129 36.36 ;
     RECT  84.841 37.632 85.129 37.656 ;
     RECT  85.097 38.688 85.169 38.712 ;
     RECT  84.485 2.256 85.853 29.64 ;
     RECT  85.129 33.264 85.921 37.656 ;
     RECT  85.921 33.168 85.961 37.656 ;
     RECT  84.593 31.2 86.029 32.088 ;
     RECT  85.961 33.168 86.029 37.128 ;
     RECT  85.853 2.64 86.053 29.64 ;
     RECT  83.704 39.984 86.06 41.4 ;
     RECT  86.053 2.64 86.065 29.736 ;
     RECT  86.065 2.64 86.249 30.168 ;
     RECT  86.249 2.64 86.357 28.92 ;
     RECT  86.249 30.144 86.677 30.168 ;
     RECT  86.029 31.2 86.677 37.128 ;
     RECT  86.06 39.264 86.825 41.4 ;
     RECT  86.825 39.264 86.929 39.864 ;
     RECT  86.929 38.784 87.041 39.864 ;
     RECT  87.041 39.216 87.149 39.864 ;
     RECT  87.149 39.216 87.437 39.48 ;
     RECT  87.437 39.216 87.509 39.24 ;
     RECT  86.677 30.144 87.577 37.128 ;
     RECT  87.577 30.144 87.613 37.416 ;
     RECT  87.613 30.144 88.045 38.04 ;
     RECT  86.357 2.64 88.069 28.824 ;
     RECT  88.069 2.496 88.081 28.824 ;
     RECT  88.081 2.256 88.117 28.824 ;
     RECT  88.045 30.144 88.117 38.232 ;
     RECT  86.825 40.848 88.261 41.4 ;
     RECT  88.261 40.368 88.549 41.4 ;
     RECT  88.549 39.792 88.657 41.4 ;
     RECT  88.117 2.256 88.808 38.232 ;
     RECT  88.657 39.312 88.808 41.4 ;
     RECT  88.808 2.148 88.912 41.4 ;
     RECT  88.912 2.256 89.104 41.4 ;
     RECT  89.104 38.784 89.219 39.864 ;
     RECT  89.104 2.256 89.525 30.936 ;
     RECT  89.525 2.496 90.421 30.936 ;
     RECT  89.104 31.968 90.421 37.416 ;
     RECT  89.219 38.784 90.601 39.816 ;
     RECT  89.104 40.848 90.601 41.4 ;
     RECT  90.421 2.496 90.641 37.416 ;
     RECT  90.641 2.496 90.995 37.368 ;
     RECT  90.601 38.784 91.145 41.4 ;
     RECT  90.995 2.496 91.969 30.888 ;
     RECT  90.995 31.968 91.969 37.368 ;
     RECT  91.969 2.496 92.113 37.368 ;
     RECT  91.145 38.832 92.113 41.4 ;
     RECT  92.113 2.496 92.401 41.4 ;
     RECT  92.401 2.256 92.485 41.4 ;
     RECT  92.485 2.496 92.585 41.4 ;
     RECT  92.585 39.84 92.869 41.4 ;
     RECT  92.585 2.496 92.873 38.664 ;
     RECT  92.869 39.84 93.053 41.592 ;
     RECT  93.053 39.84 94.057 39.864 ;
     RECT  93.053 40.848 94.057 41.592 ;
     RECT  92.873 38.64 94.069 38.664 ;
     RECT  94.057 39.84 94.069 41.592 ;
     RECT  92.873 2.496 94.208 37.368 ;
     RECT  94.069 38.64 94.208 41.592 ;
     RECT  94.208 2.148 94.312 41.592 ;
     RECT  94.312 2.418 94.504 41.592 ;
     RECT  94.504 2.592 94.997 41.592 ;
     RECT  94.997 2.592 95.501 38.472 ;
     RECT  95.501 2.592 95.609 21.24 ;
     RECT  95.501 22.464 95.717 38.472 ;
     RECT  95.609 2.592 95.821 21.192 ;
     RECT  95.717 22.464 95.897 37.416 ;
     RECT  95.717 38.4 96.145 38.472 ;
     RECT  96.145 38.4 96.217 38.52 ;
     RECT  95.821 2.256 96.227 21.192 ;
     RECT  96.217 38.4 96.397 38.712 ;
     RECT  96.227 2.592 96.437 21.192 ;
     RECT  95.897 22.464 96.685 37.368 ;
     RECT  96.397 38.4 96.997 38.808 ;
     RECT  94.997 39.84 96.997 41.592 ;
     RECT  96.685 22.08 97.049 37.368 ;
     RECT  97.049 22.608 97.333 37.368 ;
     RECT  97.333 22.608 97.405 37.416 ;
     RECT  96.997 38.4 97.405 41.592 ;
     RECT  96.437 2.592 97.513 21.096 ;
     RECT  97.513 2.592 97.964 21.576 ;
     RECT  97.964 2.256 98.012 21.576 ;
     RECT  97.405 22.608 98.012 41.592 ;
     RECT  98.012 2.256 98.051 41.592 ;
     RECT  98.051 2.64 99.608 41.592 ;
     RECT  99.608 2.148 99.712 41.592 ;
     RECT  99.712 2.418 100.577 41.592 ;
     RECT  100.577 2.418 100.717 21.528 ;
     RECT  100.717 2.256 100.937 21.528 ;
     RECT  100.937 2.256 101.941 21 ;
     RECT  101.941 2.256 102.277 21.48 ;
     RECT  100.577 22.512 102.277 41.592 ;
     RECT  102.277 2.256 102.803 41.592 ;
     RECT  102.803 2.64 102.809 41.592 ;
     RECT  102.809 38.496 102.917 41.592 ;
     RECT  102.917 38.496 103.228 39.816 ;
     RECT  102.809 2.64 103.493 37.416 ;
     RECT  103.493 2.736 103.907 37.416 ;
     RECT  103.228 38.496 104.065 39.768 ;
     RECT  103.907 2.784 104.281 37.416 ;
     RECT  104.065 38.4 104.281 39.768 ;
     RECT  104.281 2.784 105.008 39.768 ;
     RECT  102.917 40.896 105.008 41.592 ;
     RECT  105.008 2.148 105.112 41.592 ;
     RECT  105.112 2.256 105.443 41.592 ;
     RECT  105.443 2.736 105.833 41.592 ;
     RECT  105.833 2.736 106.453 40.344 ;
     RECT  106.453 2.688 106.621 40.344 ;
     RECT  106.621 2.592 106.693 40.344 ;
     RECT  106.693 2.544 106.949 40.344 ;
     RECT  106.949 2.544 107.377 24.216 ;
     RECT  107.377 2.304 107.66 24.216 ;
     RECT  106.949 25.248 107.737 40.344 ;
     RECT  105.833 41.376 107.737 41.592 ;
     RECT  107.66 2.256 107.747 24.216 ;
     RECT  107.747 2.304 108.097 24.216 ;
     RECT  107.737 25.248 108.097 41.592 ;
     RECT  108.097 2.304 108.345 41.592 ;
     RECT  108.345 2.544 109.036 41.592 ;
     RECT  109.036 2.544 110.408 24.168 ;
     RECT  109.036 25.296 110.408 41.592 ;
     RECT  110.408 2.148 110.833 41.592 ;
     RECT  110.833 2.064 112.385 41.592 ;
     RECT  112.385 2.064 113.461 21.672 ;
     RECT  113.461 2.064 113.857 21.768 ;
     RECT  112.385 22.752 113.857 41.592 ;
     RECT  113.857 2.064 117.301 41.592 ;
     RECT  117.301 1.968 117.683 41.592 ;
     RECT  117.683 38.688 118.073 41.592 ;
     RECT  117.683 1.968 119.401 37.656 ;
     RECT  118.073 38.736 119.401 41.592 ;
     RECT  119.401 1.968 119.405 41.592 ;
     RECT  119.405 36 119.693 41.592 ;
     RECT  119.693 36 120.053 40.392 ;
     RECT  119.405 1.968 121.205 34.968 ;
     RECT  121.205 2.016 121.208 34.968 ;
     RECT  120.053 36 121.208 40.344 ;
     RECT  119.693 41.376 121.208 41.592 ;
     RECT  121.208 2.016 121.504 41.592 ;
     RECT  121.504 2.016 121.619 40.344 ;
     RECT  121.619 2.016 122.537 25.224 ;
     RECT  122.537 2.016 122.609 25.176 ;
     RECT  121.619 38.832 122.677 40.344 ;
     RECT  121.619 26.256 122.713 37.704 ;
     RECT  122.677 38.736 122.713 40.344 ;
     RECT  122.713 26.256 122.861 40.344 ;
     RECT  122.861 26.256 122.965 39.288 ;
     RECT  122.609 2.016 123.155 25.128 ;
     RECT  123.155 2.208 123.577 25.128 ;
     RECT  122.965 26.208 123.577 39.288 ;
     RECT  123.577 2.208 123.581 39.288 ;
     RECT  123.581 2.256 123.833 39.288 ;
     RECT  123.833 2.256 124.067 38.232 ;
     RECT  124.067 2.304 124.265 38.232 ;
     RECT  124.265 2.304 124.401 37.08 ;
     RECT  123.833 39.264 124.405 39.288 ;
     RECT  122.861 40.32 124.405 40.344 ;
     RECT  124.401 24.24 124.769 37.08 ;
     RECT  124.769 24.24 124.877 24.552 ;
     RECT  124.401 2.304 124.985 22.536 ;
     RECT  124.405 39.264 125.057 40.344 ;
     RECT  125.057 39.264 125.129 39.624 ;
     RECT  124.985 2.304 125.237 19.368 ;
     RECT  124.265 38.208 125.269 38.232 ;
     RECT  124.769 25.584 125.305 37.08 ;
     RECT  125.269 38.16 125.305 38.232 ;
     RECT  125.305 25.584 125.489 38.232 ;
     RECT  125.489 32.448 125.525 38.232 ;
     RECT  124.985 20.448 125.561 22.536 ;
     RECT  125.525 32.448 125.561 33.816 ;
     RECT  125.525 38.112 125.597 38.232 ;
     RECT  124.877 24.24 125.845 24.504 ;
     RECT  125.489 25.584 125.845 31.128 ;
     RECT  125.845 24.24 126.061 31.128 ;
     RECT  125.561 22.464 126.385 22.536 ;
     RECT  125.561 20.448 126.565 21.144 ;
     RECT  126.385 22.464 126.565 22.776 ;
     RECT  125.237 2.352 126.608 19.368 ;
     RECT  126.565 20.448 126.608 22.776 ;
     RECT  126.061 23.952 126.608 31.128 ;
     RECT  125.561 32.448 126.608 32.52 ;
     RECT  125.561 33.792 126.608 33.816 ;
     RECT  125.525 34.848 126.608 37.08 ;
     RECT  125.597 38.112 126.608 38.136 ;
     RECT  125.129 39.264 126.608 39.288 ;
     RECT  121.504 41.376 126.608 41.592 ;
     RECT  126.608 2.148 126.712 41.592 ;
     RECT  126.712 2.418 126.904 41.592 ;
     RECT  126.904 16.56 127.001 18.216 ;
     RECT  126.904 26.88 127.001 29.016 ;
     RECT  127.001 18.192 127.037 18.216 ;
     RECT  126.904 31.44 127.132 32.904 ;
     RECT  126.904 2.592 127.145 11.496 ;
     RECT  126.904 12.768 127.145 12.792 ;
     RECT  127.001 16.56 127.145 17.208 ;
     RECT  127.001 26.88 127.181 28.728 ;
     RECT  127.181 27.12 127.217 28.728 ;
     RECT  127.145 16.56 127.955 17.064 ;
     RECT  127.217 27.936 128.221 28.728 ;
     RECT  127.145 3.36 128.405 11.496 ;
     RECT  127.955 17.04 128.531 17.064 ;
     RECT  126.904 15.408 128.579 15.432 ;
     RECT  127.132 31.92 129.301 32.904 ;
     RECT  129.301 31.92 129.409 33 ;
     RECT  128.221 27.936 129.443 28.824 ;
     RECT  128.405 3.36 129.449 11.064 ;
     RECT  129.449 3.36 129.564 11.016 ;
     RECT  129.443 27.936 129.564 28.728 ;
     RECT  129.409 31.92 129.564 33.048 ;
     RECT  126.904 41.376 129.564 41.592 ;
    LAYER M5 ;
     RECT  12.096 0.016 27.672 0.131 ;
     RECT  12.192 0.131 27.576 1.763 ;
     RECT  12.576 1.763 27.48 1.811 ;
     RECT  30.048 0.016 31.128 2.137 ;
     RECT  111.312 2.053 111.336 2.137 ;
     RECT  2.4 2.137 2.52 2.151 ;
     RECT  7.8 2.137 7.92 2.151 ;
     RECT  34.8 2.137 34.92 2.151 ;
     RECT  40.2 2.137 40.32 2.151 ;
     RECT  45.6 2.137 45.72 2.151 ;
     RECT  51 2.137 51.12 2.151 ;
     RECT  56.4 2.137 56.52 2.151 ;
     RECT  61.8 2.137 61.92 2.151 ;
     RECT  67.2 2.137 67.32 2.151 ;
     RECT  72.6 2.137 72.72 2.151 ;
     RECT  78 2.137 78.12 2.151 ;
     RECT  83.4 2.137 83.52 2.151 ;
     RECT  88.8 2.137 88.92 2.151 ;
     RECT  94.2 2.137 94.32 2.151 ;
     RECT  99.6 2.137 99.72 2.151 ;
     RECT  105 2.137 105.12 2.151 ;
     RECT  115.8 2.137 115.92 2.151 ;
     RECT  121.2 2.137 121.32 2.151 ;
     RECT  126.6 2.137 126.72 2.151 ;
     RECT  29.4 2.137 31.128 2.197 ;
     RECT  121.2 2.151 121.512 2.197 ;
     RECT  123.12 2.005 123.144 2.197 ;
     RECT  45.6 2.151 45.912 2.245 ;
     RECT  51 2.151 51.312 2.245 ;
     RECT  61.8 2.151 62.112 2.245 ;
     RECT  78 2.151 78.312 2.245 ;
     RECT  105 2.151 105.312 2.245 ;
     RECT  121.2 2.197 123.528 2.245 ;
     RECT  107.712 2.245 107.736 2.293 ;
     RECT  88.8 2.151 89.112 2.485 ;
     RECT  94.2 2.151 94.512 2.485 ;
     RECT  99.6 2.151 99.912 2.533 ;
     RECT  117.312 1.957 117.336 2.533 ;
     RECT  107.712 2.293 108.312 2.581 ;
     RECT  107.184 2.581 108.312 2.629 ;
     RECT  121.2 2.245 124.056 2.629 ;
     RECT  112.848 2.437 112.872 2.675 ;
     RECT  61.68 2.245 62.112 2.677 ;
     RECT  107.088 2.629 108.312 2.677 ;
     RECT  117.312 2.533 117.912 2.677 ;
     RECT  12.576 1.811 26.856 2.725 ;
     RECT  70.416 2.245 70.44 2.725 ;
     RECT  12.432 2.725 26.856 2.773 ;
     RECT  29.4 2.197 32.136 2.773 ;
     RECT  34.8 2.151 35.112 2.773 ;
     RECT  98.016 2.245 98.04 2.773 ;
     RECT  117.312 2.677 118.584 2.819 ;
     RECT  29.4 2.773 32.328 2.821 ;
     RECT  33.744 2.773 33.768 2.821 ;
     RECT  34.8 2.773 35.928 2.821 ;
     RECT  77.184 2.245 78.312 2.821 ;
     RECT  83.4 2.151 83.712 2.821 ;
     RECT  102.768 2.245 102.792 2.821 ;
     RECT  103.872 2.725 103.896 2.821 ;
     RECT  106.464 2.677 108.312 2.867 ;
     RECT  37.008 2.773 37.032 2.869 ;
     RECT  45.168 2.245 45.912 2.915 ;
     RECT  45.264 2.915 45.912 3.011 ;
     RECT  74.544 2.245 74.568 3.011 ;
     RECT  96.192 2.245 96.216 3.011 ;
     RECT  119.616 2.245 119.64 3.011 ;
     RECT  33.744 2.821 35.928 3.013 ;
     RECT  97.344 2.773 98.04 3.059 ;
     RECT  69.552 2.725 70.44 3.061 ;
     RECT  37.008 2.869 37.128 3.107 ;
     RECT  121.2 2.629 124.248 3.109 ;
     RECT  9.552 2.821 9.576 3.157 ;
     RECT  46.944 2.245 46.968 3.203 ;
     RECT  43.296 2.245 43.32 3.299 ;
     RECT  85.2 2.245 85.224 3.299 ;
     RECT  88.08 2.485 89.112 3.299 ;
     RECT  113.952 2.341 114.648 3.299 ;
     RECT  9.552 3.157 9.912 3.301 ;
     RECT  56.4 2.151 56.712 3.301 ;
     RECT  102.768 2.821 103.896 3.349 ;
     RECT  69.552 3.061 71.4 3.395 ;
     RECT  113.952 3.299 113.976 3.397 ;
     RECT  61.008 2.677 62.112 3.443 ;
     RECT  94.08 2.485 94.512 3.587 ;
     RECT  113.136 3.397 113.976 3.587 ;
     RECT  29.4 2.821 32.424 3.589 ;
     RECT  120.624 3.109 124.248 3.589 ;
     RECT  12.432 2.773 27.144 3.637 ;
     RECT  67.2 2.151 67.512 3.637 ;
     RECT  9.552 3.301 10.248 3.685 ;
     RECT  11.376 3.397 11.4 3.685 ;
     RECT  120.624 3.589 124.488 3.685 ;
     RECT  110.4 2.137 111.336 3.731 ;
     RECT  33.744 3.013 36.024 3.779 ;
     RECT  102.768 3.349 103.944 3.829 ;
     RECT  105 2.245 105.432 3.829 ;
     RECT  67.2 3.637 68.088 3.875 ;
     RECT  88.368 3.299 89.112 3.875 ;
     RECT  92.448 2.245 92.472 3.875 ;
     RECT  102.72 3.829 105.432 3.875 ;
     RECT  12.432 3.637 27.624 3.877 ;
     RECT  29.4 3.589 32.664 3.877 ;
     RECT  76.416 2.821 78.312 3.923 ;
     RECT  7.8 2.151 8.112 3.925 ;
     RECT  9.552 3.685 11.4 3.925 ;
     RECT  12.432 3.877 32.664 3.925 ;
     RECT  63.216 2.773 63.24 3.925 ;
     RECT  82.896 2.821 83.712 3.925 ;
     RECT  108.288 2.867 108.312 3.925 ;
     RECT  102.72 3.875 105.312 3.971 ;
     RECT  117.312 2.819 117.336 4.019 ;
     RECT  99.6 2.533 100.872 4.021 ;
     RECT  97.344 3.059 97.368 4.067 ;
     RECT  80.976 2.773 81 4.115 ;
     RECT  108.288 3.925 109.224 4.115 ;
     RECT  115.8 2.151 116.112 4.117 ;
     RECT  82.896 3.925 84.552 4.213 ;
     RECT  61.68 3.443 62.112 4.259 ;
     RECT  82.08 4.213 84.552 4.259 ;
     RECT  115.8 4.117 117.048 4.259 ;
     RECT  50.16 2.245 51.312 4.355 ;
     RECT  45.6 3.011 45.912 4.357 ;
     RECT  69.552 3.395 69.576 4.357 ;
     RECT  76.416 3.923 76.44 4.357 ;
     RECT  86.112 3.349 86.136 4.357 ;
     RECT  109.2 4.115 109.224 4.357 ;
     RECT  110.4 3.731 111.24 4.357 ;
     RECT  63.216 3.925 64.104 4.405 ;
     RECT  9.552 3.925 32.664 4.451 ;
     RECT  120.624 3.685 124.68 4.453 ;
     RECT  10.224 4.451 32.664 4.501 ;
     RECT  109.2 4.357 111.24 4.547 ;
     RECT  91.296 3.925 91.848 4.643 ;
     RECT  109.2 4.547 109.224 4.643 ;
     RECT  65.568 3.925 65.592 4.691 ;
     RECT  69.552 4.357 70.152 4.691 ;
     RECT  71.376 3.395 71.4 4.691 ;
     RECT  75.792 4.357 76.44 4.691 ;
     RECT  118.848 3.397 118.872 4.693 ;
     RECT  7.8 3.925 8.232 4.789 ;
     RECT  63.216 4.405 64.152 4.883 ;
     RECT  67.2 3.875 67.512 4.981 ;
     RECT  118.56 4.693 118.872 5.027 ;
     RECT  94.2 3.587 94.512 5.077 ;
     RECT  10.224 4.501 33.048 5.125 ;
     RECT  88.8 3.875 89.112 5.125 ;
     RECT  5.232 3.685 5.256 5.171 ;
     RECT  53.712 3.925 53.736 5.171 ;
     RECT  75.792 4.691 75.816 5.171 ;
     RECT  102.72 3.971 103.992 5.171 ;
     RECT  105 3.971 105.312 5.173 ;
     RECT  110.4 4.547 111.24 5.173 ;
     RECT  98.64 4.021 100.872 5.221 ;
     RECT  104.88 5.173 105.312 5.221 ;
     RECT  106.464 2.867 107.208 5.221 ;
     RECT  58.752 3.925 58.776 5.267 ;
     RECT  115.8 4.259 116.328 5.363 ;
     RECT  120.192 4.453 124.68 5.365 ;
     RECT  34.08 3.779 36.024 5.413 ;
     RECT  37.008 3.107 37.032 5.413 ;
     RECT  126.6 2.151 126.912 5.413 ;
     RECT  93.36 5.077 95.304 5.507 ;
     RECT  110.4 5.173 111.864 5.507 ;
     RECT  10.224 5.125 33.096 5.605 ;
     RECT  34.08 5.413 37.032 5.605 ;
     RECT  70.128 4.691 70.152 5.605 ;
     RECT  72.6 2.151 72.912 5.605 ;
     RECT  93.456 5.507 95.304 5.605 ;
     RECT  126.384 5.413 126.912 5.651 ;
     RECT  104.88 5.221 107.208 5.653 ;
     RECT  118.848 5.027 118.872 5.653 ;
     RECT  120.048 5.365 124.68 5.653 ;
     RECT  74.064 3.925 74.088 5.747 ;
     RECT  98.64 5.221 100.968 5.747 ;
     RECT  102.72 5.171 103.704 5.747 ;
     RECT  83.4 4.259 84.552 5.749 ;
     RECT  66.72 4.981 67.512 5.845 ;
     RECT  118.848 5.653 124.68 5.845 ;
     RECT  10.128 5.605 37.032 5.891 ;
     RECT  10.128 5.891 33.768 6.035 ;
     RECT  82.08 4.259 82.104 6.035 ;
     RECT  97.248 4.453 97.272 6.037 ;
     RECT  110.4 5.507 111.24 6.083 ;
     RECT  118.848 5.845 124.824 6.083 ;
     RECT  88.8 5.125 90.024 6.133 ;
     RECT  34.8 5.891 37.032 6.181 ;
     RECT  38.448 4.981 38.472 6.181 ;
     RECT  34.8 6.181 38.472 6.229 ;
     RECT  40.2 2.151 40.512 6.229 ;
     RECT  75.264 5.653 75.288 6.229 ;
     RECT  10.896 6.035 33.768 6.275 ;
     RECT  61.8 4.259 62.112 6.277 ;
     RECT  85.872 4.357 86.136 6.323 ;
     RECT  91.824 4.643 91.848 6.323 ;
     RECT  93.456 5.605 96.024 6.323 ;
     RECT  99.168 5.747 100.968 6.323 ;
     RECT  34.8 6.229 40.512 6.371 ;
     RECT  87.6 5.845 87.624 6.373 ;
     RECT  88.8 6.133 90.552 6.373 ;
     RECT  74.448 6.229 75.288 6.515 ;
     RECT  103.68 5.747 103.704 6.517 ;
     RECT  87.6 6.373 90.552 6.563 ;
     RECT  103.68 6.517 103.752 6.709 ;
     RECT  83.4 5.749 84.792 6.805 ;
     RECT  87.6 6.563 89.544 6.805 ;
     RECT  103.152 6.709 103.752 6.805 ;
     RECT  104.88 5.653 108.024 6.805 ;
     RECT  47.904 5.077 47.928 6.851 ;
     RECT  66.288 5.845 67.512 6.851 ;
     RECT  87.36 6.805 89.544 6.851 ;
     RECT  118.848 6.083 124.488 6.851 ;
     RECT  103.152 6.805 108.024 6.853 ;
     RECT  102.72 6.853 108.024 6.995 ;
     RECT  7.8 4.789 9.096 7.043 ;
     RECT  70.128 5.605 71.016 7.043 ;
     RECT  53.28 6.805 53.304 7.091 ;
     RECT  64.08 4.883 64.152 7.235 ;
     RECT  86.064 6.323 86.136 7.235 ;
     RECT  2.4 2.151 2.712 7.237 ;
     RECT  113.136 3.587 113.16 7.331 ;
     RECT  64.08 7.235 64.104 7.333 ;
     RECT  120.288 6.851 124.488 7.333 ;
     RECT  70.992 7.043 71.016 7.379 ;
     RECT  4.56 5.653 4.584 7.381 ;
     RECT  5.76 6.613 5.784 7.381 ;
     RECT  34.8 6.371 35.928 7.381 ;
     RECT  37.008 6.371 40.512 7.381 ;
     RECT  115.8 5.363 116.112 7.381 ;
     RECT  117.168 5.701 117.192 7.381 ;
     RECT  58.32 6.853 58.344 7.475 ;
     RECT  61.8 6.277 62.472 7.475 ;
     RECT  90.528 6.563 90.552 7.523 ;
     RECT  34.8 7.381 40.512 7.525 ;
     RECT  95.952 6.323 96.024 7.525 ;
     RECT  97.248 6.037 97.512 7.525 ;
     RECT  99.504 6.323 100.968 7.571 ;
     RECT  34.8 7.525 40.632 7.619 ;
     RECT  87.36 6.851 87.384 7.619 ;
     RECT  38.736 7.619 40.632 7.621 ;
     RECT  76.944 6.853 76.968 7.621 ;
     RECT  78 3.923 78.312 7.621 ;
     RECT  83.4 6.805 84.984 7.667 ;
     RECT  95.952 7.525 97.512 7.667 ;
     RECT  38.736 7.621 41.064 7.763 ;
     RECT  45.6 4.357 46.008 7.765 ;
     RECT  102.72 6.995 106.536 7.909 ;
     RECT  60.72 6.805 60.744 7.955 ;
     RECT  80.784 6.229 80.808 7.955 ;
     RECT  56.4 3.301 56.952 7.957 ;
     RECT  102.432 7.909 106.536 7.957 ;
     RECT  11.472 6.275 33.768 8.003 ;
     RECT  115.8 7.381 117.192 8.003 ;
     RECT  102.432 7.957 106.584 8.099 ;
     RECT  95.952 7.667 95.976 8.147 ;
     RECT  120.288 7.333 124.728 8.149 ;
     RECT  2.4 7.237 2.952 8.195 ;
     RECT  118.848 6.851 119.112 8.389 ;
     RECT  21.408 8.003 33.768 8.437 ;
     RECT  34.8 7.619 37.608 8.437 ;
     RECT  38.784 7.763 41.064 8.483 ;
     RECT  66.624 6.851 67.512 8.483 ;
     RECT  69.072 6.805 69.096 8.483 ;
     RECT  81.84 8.389 81.864 8.485 ;
     RECT  83.4 7.667 84.648 8.485 ;
     RECT  94.2 6.323 94.632 8.485 ;
     RECT  74.448 6.515 74.472 8.581 ;
     RECT  49.728 7.909 49.752 8.627 ;
     RECT  63.696 7.333 64.104 8.627 ;
     RECT  88.512 6.851 89.544 8.627 ;
     RECT  63.696 8.627 63.864 8.675 ;
     RECT  4.56 7.381 5.784 8.723 ;
     RECT  9.312 7.381 9.336 8.723 ;
     RECT  21.408 8.437 37.608 8.723 ;
     RECT  102.432 8.099 106.536 8.723 ;
     RECT  120.288 8.149 124.776 8.773 ;
     RECT  40.2 8.483 41.064 8.819 ;
     RECT  117.168 8.003 117.192 8.869 ;
     RECT  118.272 8.389 119.112 8.869 ;
     RECT  21.408 8.723 35.736 8.963 ;
     RECT  11.472 8.003 20.376 8.965 ;
     RECT  21.408 8.963 29.712 8.965 ;
     RECT  59.568 7.381 59.592 9.011 ;
     RECT  129.264 8.869 129.288 9.011 ;
     RECT  86.112 7.235 86.136 9.013 ;
     RECT  99.6 7.571 100.968 9.013 ;
     RECT  98.976 9.013 100.968 9.059 ;
     RECT  115.8 8.003 116.112 9.061 ;
     RECT  117.168 8.869 119.112 9.061 ;
     RECT  4.8 8.723 5.784 9.155 ;
     RECT  11.472 8.965 29.712 9.155 ;
     RECT  31.584 8.963 35.736 9.155 ;
     RECT  54.288 7.381 54.312 9.155 ;
     RECT  86.112 9.013 86.52 9.155 ;
     RECT  92.592 7.765 92.616 9.155 ;
     RECT  11.472 9.155 11.496 9.203 ;
     RECT  76.944 7.621 78.312 9.203 ;
     RECT  120.288 8.773 125.4 9.205 ;
     RECT  102.432 8.723 102.744 9.253 ;
     RECT  107.568 6.995 108.024 9.253 ;
     RECT  51 4.355 51.312 9.301 ;
     RECT  79.632 8.965 79.656 9.301 ;
     RECT  12.48 9.155 29.712 9.347 ;
     RECT  72.384 5.605 72.912 9.349 ;
     RECT  97.248 7.667 97.512 9.349 ;
     RECT  51 9.301 51.864 9.443 ;
     RECT  83.28 8.485 84.648 9.541 ;
     RECT  86.112 9.155 86.136 9.541 ;
     RECT  127.92 9.301 127.944 9.541 ;
     RECT  98.976 9.059 100.104 9.587 ;
     RECT  103.968 8.723 106.536 9.589 ;
     RECT  107.568 9.253 108.264 9.589 ;
     RECT  36.864 8.723 37.608 9.635 ;
     RECT  51 9.443 51.312 9.637 ;
     RECT  67.2 8.483 67.512 9.637 ;
     RECT  61.8 7.475 62.112 9.685 ;
     RECT  45.6 7.765 46.632 9.731 ;
     RECT  88.8 8.627 89.544 9.731 ;
     RECT  96.48 9.349 97.512 9.731 ;
     RECT  45.6 9.731 46.008 9.779 ;
     RECT  56.4 7.957 57.24 9.779 ;
     RECT  80.976 8.485 81.864 9.779 ;
     RECT  101.808 9.253 102.744 9.779 ;
     RECT  22.656 9.347 29.712 9.875 ;
     RECT  33.216 9.155 35.736 9.875 ;
     RECT  98.976 9.587 100.008 9.875 ;
     RECT  74.448 8.581 74.52 9.923 ;
     RECT  115.8 9.061 119.112 9.923 ;
     RECT  120.288 9.205 125.496 9.925 ;
     RECT  120.288 9.925 125.544 9.973 ;
     RECT  77.52 9.203 78.312 10.021 ;
     RECT  79.632 9.301 79.8 10.021 ;
     RECT  38.784 8.483 38.808 10.067 ;
     RECT  2.4 8.195 2.712 10.069 ;
     RECT  7.8 7.043 8.112 10.069 ;
     RECT  81.408 9.779 81.864 10.069 ;
     RECT  83.28 9.541 86.136 10.069 ;
     RECT  61.536 9.685 62.112 10.115 ;
     RECT  63.84 8.675 63.864 10.163 ;
     RECT  94.2 8.485 95.16 10.163 ;
     RECT  81.408 10.069 86.136 10.211 ;
     RECT  120.192 9.973 125.544 10.259 ;
     RECT  97.488 9.731 97.512 10.261 ;
     RECT  102.432 9.779 102.744 10.261 ;
     RECT  12.48 9.347 21.48 10.307 ;
     RECT  60.432 9.637 60.456 10.307 ;
     RECT  64.992 9.925 65.016 10.307 ;
     RECT  87.744 9.397 87.768 10.307 ;
     RECT  92.544 9.349 92.568 10.307 ;
     RECT  97.488 10.261 97.656 10.307 ;
     RECT  5.136 9.155 5.784 10.309 ;
     RECT  4.512 10.309 5.784 10.355 ;
     RECT  12.816 10.307 13.512 10.355 ;
     RECT  83.28 10.211 86.136 10.355 ;
     RECT  96.48 9.731 96.504 10.355 ;
     RECT  70.704 9.541 70.728 10.501 ;
     RECT  71.76 9.349 72.912 10.501 ;
     RECT  33.408 9.875 35.736 10.549 ;
     RECT  14.544 10.307 21.48 10.595 ;
     RECT  70.704 10.501 72.912 10.643 ;
     RECT  102.432 10.261 102.792 10.645 ;
     RECT  68.736 9.541 68.76 10.693 ;
     RECT  127.92 9.541 128.568 10.693 ;
     RECT  103.968 9.589 109.176 10.739 ;
     RECT  74.496 9.923 74.52 10.835 ;
     RECT  66.72 9.637 67.512 10.837 ;
     RECT  68.496 10.693 68.76 10.837 ;
     RECT  22.656 9.875 27.096 10.883 ;
     RECT  36.912 9.635 37.608 10.883 ;
     RECT  77.52 10.021 79.8 10.883 ;
     RECT  111.888 7.285 111.912 10.883 ;
     RECT  68.496 10.837 68.952 10.979 ;
     RECT  33.408 10.549 35.832 10.981 ;
     RECT  36.912 10.883 36.936 10.981 ;
     RECT  71.28 10.643 72.912 11.027 ;
     RECT  81.408 10.211 81.432 11.027 ;
     RECT  42.72 10.453 42.744 11.029 ;
     RECT  44.064 8.197 44.088 11.029 ;
     RECT  2.4 10.069 3.432 11.075 ;
     RECT  127.92 10.693 129.432 11.075 ;
     RECT  75.504 9.301 75.528 11.123 ;
     RECT  103.968 10.739 108.36 11.123 ;
     RECT  59.184 10.789 59.208 11.125 ;
     RECT  58.272 11.125 59.208 11.171 ;
     RECT  99.6 9.875 100.008 11.173 ;
     RECT  13.2 10.355 13.512 11.365 ;
     RECT  14.544 10.595 20.088 11.365 ;
     RECT  102.432 10.645 102.888 11.413 ;
     RECT  103.968 11.123 108.264 11.413 ;
     RECT  7.8 10.069 9 11.459 ;
     RECT  13.2 11.365 20.088 11.459 ;
     RECT  22.656 10.883 26.376 11.459 ;
     RECT  68.496 10.979 68.76 11.459 ;
     RECT  83.4 10.355 86.136 11.459 ;
     RECT  102.432 11.413 108.264 11.459 ;
     RECT  33.408 10.981 36.936 11.507 ;
     RECT  115.8 9.923 118.872 11.507 ;
     RECT  61.8 10.115 62.112 11.557 ;
     RECT  37.92 10.981 37.944 11.699 ;
     RECT  50.736 9.637 51.312 11.699 ;
     RECT  102.432 11.459 106.056 11.747 ;
     RECT  42.72 11.029 44.088 11.749 ;
     RECT  120.288 10.259 125.544 11.749 ;
     RECT  126.6 5.651 126.912 11.749 ;
     RECT  66.144 10.837 67.512 11.797 ;
     RECT  83.4 11.459 85.512 11.797 ;
     RECT  65.28 11.797 67.512 11.843 ;
     RECT  71.28 11.027 71.304 11.893 ;
     RECT  42.72 11.749 44.472 11.939 ;
     RECT  58.272 11.171 58.296 11.939 ;
     RECT  7.8 11.459 8.112 11.941 ;
     RECT  110.4 6.083 110.712 11.941 ;
     RECT  34.224 11.507 36.936 11.987 ;
     RECT  67.104 11.843 67.512 11.989 ;
     RECT  115.8 11.507 118.776 11.989 ;
     RECT  28.464 9.875 29.712 12.035 ;
     RECT  34.224 11.987 35.4 12.035 ;
     RECT  77.52 10.883 78.312 12.035 ;
     RECT  102.864 11.747 106.056 12.035 ;
     RECT  23.04 11.459 26.376 12.131 ;
     RECT  34.56 12.035 35.4 12.131 ;
     RECT  67.104 11.989 67.656 12.179 ;
     RECT  120.288 11.749 126.912 12.181 ;
     RECT  83.232 11.797 85.512 12.227 ;
     RECT  112.896 11.893 112.92 12.229 ;
     RECT  44.064 11.939 44.472 12.275 ;
     RECT  119.904 12.181 126.912 12.323 ;
     RECT  5.76 10.355 5.784 12.467 ;
     RECT  99.6 11.173 100.152 12.469 ;
     RECT  45.6 9.779 45.912 12.517 ;
     RECT  83.232 12.227 83.712 12.517 ;
     RECT  13.2 11.459 19.224 12.563 ;
     RECT  23.04 12.131 25.752 12.563 ;
     RECT  44.448 12.275 44.472 12.563 ;
     RECT  61.8 11.557 62.664 12.563 ;
     RECT  99.36 12.469 100.152 12.563 ;
     RECT  102.864 12.035 103.224 12.563 ;
     RECT  104.256 12.035 106.056 12.563 ;
     RECT  13.2 12.563 15.576 12.611 ;
     RECT  16.656 12.563 16.728 12.659 ;
     RECT  85.248 12.227 85.512 12.709 ;
     RECT  36.432 11.987 36.936 12.755 ;
     RECT  42.72 11.939 42.744 12.755 ;
     RECT  67.2 12.179 67.656 12.757 ;
     RECT  68.736 11.459 68.76 12.757 ;
     RECT  88.8 9.731 89.112 12.757 ;
     RECT  81.84 12.517 83.712 12.803 ;
     RECT  67.2 12.757 68.76 12.899 ;
     RECT  112.896 12.229 113.112 12.997 ;
     RECT  68.736 12.899 68.76 13.043 ;
     RECT  40.2 8.819 40.512 13.045 ;
     RECT  41.568 11.029 41.592 13.045 ;
     RECT  63.744 11.605 63.768 13.045 ;
     RECT  65.28 11.843 65.304 13.045 ;
     RECT  79.632 10.883 79.8 13.045 ;
     RECT  94.2 10.163 94.512 13.045 ;
     RECT  110.4 11.941 111.384 13.045 ;
     RECT  67.2 12.899 67.656 13.091 ;
     RECT  29.088 12.035 29.712 13.093 ;
     RECT  32.928 12.757 32.952 13.093 ;
     RECT  74.256 12.517 74.28 13.093 ;
     RECT  115.68 11.989 118.776 13.093 ;
     RECT  13.2 12.611 14.376 13.139 ;
     RECT  15.552 12.611 15.576 13.139 ;
     RECT  16.656 12.659 16.68 13.139 ;
     RECT  23.04 12.563 24.408 13.139 ;
     RECT  74.064 13.093 74.28 13.139 ;
     RECT  85.248 12.709 86.472 13.139 ;
     RECT  102.864 12.563 103.176 13.139 ;
     RECT  63.744 13.045 65.304 13.235 ;
     RECT  112.848 12.997 113.112 13.237 ;
     RECT  107.184 11.459 108.264 13.283 ;
     RECT  21.456 10.595 21.48 13.331 ;
     RECT  109.488 13.045 111.384 13.333 ;
     RECT  115.392 13.093 118.776 13.333 ;
     RECT  17.808 12.563 19.224 13.379 ;
     RECT  112.56 13.237 113.112 13.379 ;
     RECT  29.088 13.093 29.832 13.429 ;
     RECT  93.84 13.045 94.512 13.429 ;
     RECT  7.296 11.941 8.112 13.475 ;
     RECT  63.744 13.235 64.392 13.523 ;
     RECT  7.8 13.475 8.112 13.525 ;
     RECT  70.752 11.893 71.304 13.525 ;
     RECT  72.6 11.027 72.912 13.525 ;
     RECT  31.584 9.155 31.608 13.573 ;
     RECT  32.928 13.093 33.096 13.573 ;
     RECT  48.384 11.893 48.408 13.573 ;
     RECT  78 12.035 78.312 13.573 ;
     RECT  92.88 13.429 94.512 13.573 ;
     RECT  99.36 12.563 99.912 13.573 ;
     RECT  53.184 12.517 53.208 13.619 ;
     RECT  75.984 11.941 76.008 13.619 ;
     RECT  85.248 13.139 85.272 13.619 ;
     RECT  97.632 10.307 97.656 13.619 ;
     RECT  114.528 13.333 118.776 13.619 ;
     RECT  24 13.139 24.408 13.621 ;
     RECT  25.44 12.563 25.752 13.621 ;
     RECT  31.584 13.573 33.096 13.621 ;
     RECT  112.896 13.379 113.112 13.621 ;
     RECT  28.752 13.429 29.832 13.667 ;
     RECT  70.752 13.525 72.912 13.667 ;
     RECT  112.896 13.621 113.304 13.667 ;
     RECT  28.896 13.667 29.832 13.715 ;
     RECT  48.384 13.573 48.984 13.715 ;
     RECT  50.88 11.699 51.312 13.715 ;
     RECT  79.296 13.045 79.8 13.715 ;
     RECT  24 13.621 25.752 13.859 ;
     RECT  31.584 13.621 33.432 13.859 ;
     RECT  64.368 13.523 64.392 13.859 ;
     RECT  120.624 12.323 126.912 13.909 ;
     RECT  120.576 13.909 126.912 13.957 ;
     RECT  115.68 13.619 118.776 14.003 ;
     RECT  4.512 10.355 4.536 14.005 ;
     RECT  118.464 14.003 118.776 14.005 ;
     RECT  120.48 13.957 126.912 14.005 ;
     RECT  31.584 13.859 32.28 14.051 ;
     RECT  103.152 13.139 103.176 14.053 ;
     RECT  104.256 12.563 105.312 14.053 ;
     RECT  29.4 13.715 29.832 14.099 ;
     RECT  40.2 13.045 41.592 14.147 ;
     RECT  77.904 13.573 78.312 14.147 ;
     RECT  109.344 13.333 111.384 14.147 ;
     RECT  86.448 13.139 86.472 14.195 ;
     RECT  54.576 11.125 54.6 14.197 ;
     RECT  56.4 9.779 56.712 14.197 ;
     RECT  61.8 12.563 62.112 14.197 ;
     RECT  113.28 13.667 113.304 14.197 ;
     RECT  9.84 12.517 9.864 14.291 ;
     RECT  44.448 13.621 44.472 14.291 ;
     RECT  22.944 14.149 22.968 14.339 ;
     RECT  25.344 13.859 25.752 14.339 ;
     RECT  45.6 12.517 46.344 14.341 ;
     RECT  81.84 12.803 81.864 14.389 ;
     RECT  80.976 14.389 81.864 14.435 ;
     RECT  25.728 14.339 25.752 14.483 ;
     RECT  36.432 12.755 36.648 14.485 ;
     RECT  54.576 14.197 56.712 14.485 ;
     RECT  99.264 13.573 99.912 14.485 ;
     RECT  107.184 13.283 107.928 14.533 ;
     RECT  114.528 13.619 114.552 14.533 ;
     RECT  98.544 14.485 99.912 14.581 ;
     RECT  2.4 11.075 2.712 14.629 ;
     RECT  71.28 13.667 72.912 14.629 ;
     RECT  103.152 14.053 105.312 14.629 ;
     RECT  53.76 14.485 56.712 14.675 ;
     RECT  51 13.715 51.312 14.677 ;
     RECT  54.576 14.675 56.712 14.723 ;
     RECT  61.8 14.197 62.76 14.723 ;
     RECT  71.04 14.629 72.912 14.771 ;
     RECT  79.44 13.715 79.8 14.771 ;
     RECT  7.8 13.525 8.232 14.773 ;
     RECT  88.8 12.757 89.208 14.773 ;
     RECT  51 14.677 51.432 14.819 ;
     RECT  91.776 13.429 91.8 14.819 ;
     RECT  34.56 12.131 35.112 14.821 ;
     RECT  36.432 14.485 37.368 14.821 ;
     RECT  54.672 14.723 56.712 14.867 ;
     RECT  98.544 14.581 100.296 14.867 ;
     RECT  118.464 14.005 126.912 14.867 ;
     RECT  67.2 13.091 67.512 14.869 ;
     RECT  48.96 13.715 48.984 14.915 ;
     RECT  29.4 14.099 29.712 14.917 ;
     RECT  58.128 14.725 58.152 14.917 ;
     RECT  33.408 13.859 33.432 14.963 ;
     RECT  38.688 13.573 38.712 14.963 ;
     RECT  57.792 14.917 58.152 14.963 ;
     RECT  29.04 14.917 29.712 15.059 ;
     RECT  54.72 14.867 56.712 15.059 ;
     RECT  109.344 14.147 111.24 15.205 ;
     RECT  88.8 14.773 89.928 15.251 ;
     RECT  92.88 13.573 94.872 15.251 ;
     RECT  45.6 14.341 46.68 15.299 ;
     RECT  79.632 14.771 79.8 15.299 ;
     RECT  71.76 14.771 72.912 15.301 ;
     RECT  74.064 13.139 74.088 15.301 ;
     RECT  114.432 14.533 114.552 15.301 ;
     RECT  7.68 14.773 8.856 15.349 ;
     RECT  113.28 14.197 113.448 15.349 ;
     RECT  115.68 14.003 117.432 15.349 ;
     RECT  118.464 14.867 118.536 15.349 ;
     RECT  4.512 14.005 4.728 15.395 ;
     RECT  20.496 13.621 20.52 15.443 ;
     RECT  60.096 13.861 60.12 15.443 ;
     RECT  71.76 15.301 74.088 15.443 ;
     RECT  97.44 14.437 97.464 15.443 ;
     RECT  102.912 14.629 105.312 15.443 ;
     RECT  119.52 14.867 124.584 15.443 ;
     RECT  127.92 11.075 128.568 15.443 ;
     RECT  107.088 14.533 107.928 15.541 ;
     RECT  109.104 15.205 111.24 15.541 ;
     RECT  112.8 15.349 113.448 15.733 ;
     RECT  114.432 15.301 114.696 15.733 ;
     RECT  48.192 15.637 48.216 15.779 ;
     RECT  90.528 15.733 90.552 15.829 ;
     RECT  125.616 14.867 126.912 15.829 ;
     RECT  61.8 14.723 62.112 15.877 ;
     RECT  112.8 15.733 114.696 15.877 ;
     RECT  107.088 15.541 111.24 15.925 ;
     RECT  112.656 15.877 114.696 15.925 ;
     RECT  24 13.859 24.312 15.973 ;
     RECT  40.2 14.147 41.208 15.973 ;
     RECT  2.4 14.629 2.808 16.019 ;
     RECT  7.68 15.349 9.768 16.019 ;
     RECT  80.976 14.435 81.24 16.019 ;
     RECT  107.088 15.925 114.696 16.019 ;
     RECT  115.68 15.349 118.536 16.021 ;
     RECT  119.52 15.443 124.44 16.021 ;
     RECT  39.888 15.973 41.208 16.163 ;
     RECT  90.528 15.829 90.6 16.163 ;
     RECT  125.568 15.829 126.912 16.165 ;
     RECT  61.344 15.877 62.112 16.307 ;
     RECT  63.168 15.109 63.192 16.307 ;
     RECT  112.8 16.019 114.696 16.309 ;
     RECT  115.68 16.021 124.44 16.309 ;
     RECT  75.168 15.061 75.192 16.357 ;
     RECT  65.28 14.725 65.304 16.403 ;
     RECT  4.512 15.395 4.536 16.405 ;
     RECT  45.6 15.299 46.008 16.405 ;
     RECT  86.592 15.877 86.616 16.405 ;
     RECT  83.232 12.803 83.712 16.453 ;
     RECT  80.976 16.019 81 16.499 ;
     RECT  3.888 16.405 4.536 16.501 ;
     RECT  29.4 15.059 29.712 16.501 ;
     RECT  34.56 14.821 37.368 16.549 ;
     RECT  55.44 15.059 56.712 16.595 ;
     RECT  92.88 15.251 94.776 16.595 ;
     RECT  127.92 15.443 128.52 16.595 ;
     RECT  7.8 16.019 9.768 16.691 ;
     RECT  39.984 16.163 41.208 16.693 ;
     RECT  34.56 16.549 37.416 16.739 ;
     RECT  57.792 14.963 57.816 16.787 ;
     RECT  112.8 16.309 124.44 16.787 ;
     RECT  24 15.973 24.6 16.835 ;
     RECT  101.856 15.301 101.88 16.835 ;
     RECT  107.088 16.019 111.816 16.837 ;
     RECT  3.888 16.501 5.112 16.883 ;
     RECT  112.8 16.787 118.824 16.883 ;
     RECT  39.984 16.693 41.304 16.931 ;
     RECT  119.904 16.787 124.44 16.933 ;
     RECT  125.424 16.165 126.912 16.933 ;
     RECT  27.696 16.501 27.72 16.981 ;
     RECT  55.968 16.595 56.712 16.981 ;
     RECT  13.2 13.139 13.512 17.029 ;
     RECT  67.056 14.869 67.512 17.029 ;
     RECT  86.496 16.405 86.616 17.029 ;
     RECT  104.544 15.443 105.312 17.029 ;
     RECT  106.56 16.837 111.816 17.029 ;
     RECT  112.8 16.883 114.456 17.029 ;
     RECT  71.76 15.443 73.176 17.075 ;
     RECT  86.064 17.029 86.616 17.075 ;
     RECT  128.496 16.595 128.52 17.075 ;
     RECT  70.08 17.029 70.104 17.077 ;
     RECT  11.76 16.501 11.784 17.123 ;
     RECT  55.968 16.981 57.048 17.123 ;
     RECT  67.056 17.029 68.376 17.123 ;
     RECT  106.56 17.029 114.456 17.123 ;
     RECT  119.904 16.933 126.912 17.123 ;
     RECT  104.256 17.029 105.312 17.125 ;
     RECT  90.528 16.163 90.552 17.171 ;
     RECT  92.88 16.595 94.68 17.171 ;
     RECT  17.808 13.379 19.032 17.219 ;
     RECT  84.768 17.077 84.792 17.219 ;
     RECT  82.752 16.453 83.712 17.267 ;
     RECT  86.064 17.075 86.52 17.267 ;
     RECT  45.6 16.405 46.248 17.315 ;
     RECT  79.632 15.299 79.656 17.315 ;
     RECT  31.584 14.051 31.608 17.317 ;
     RECT  40.2 16.931 41.304 17.317 ;
     RECT  80.688 16.501 80.712 17.363 ;
     RECT  106.56 17.123 111.912 17.363 ;
     RECT  40.2 17.317 41.736 17.459 ;
     RECT  108.624 17.363 111.912 17.459 ;
     RECT  25.728 16.981 25.752 17.461 ;
     RECT  27.36 16.981 27.72 17.507 ;
     RECT  31.536 17.317 31.608 17.507 ;
     RECT  37.008 16.739 37.416 17.507 ;
     RECT  37.2 17.507 37.416 17.603 ;
     RECT  55.968 17.123 56.712 17.603 ;
     RECT  71.76 17.075 72.912 17.603 ;
     RECT  108.624 17.459 109.032 17.603 ;
     RECT  115.8 16.883 118.824 17.603 ;
     RECT  102.912 15.443 103.08 17.605 ;
     RECT  20.64 16.405 20.664 17.651 ;
     RECT  28.896 16.501 29.712 17.651 ;
     RECT  37.392 17.603 37.416 17.651 ;
     RECT  69.744 17.077 70.104 17.651 ;
     RECT  88.8 15.251 89.208 17.653 ;
     RECT  106.56 17.363 107.256 17.699 ;
     RECT  113.664 17.123 114.456 17.699 ;
     RECT  69.888 17.651 70.104 17.797 ;
     RECT  86.496 17.267 86.52 17.843 ;
     RECT  12.768 17.029 13.512 17.891 ;
     RECT  53.28 16.165 53.304 17.891 ;
     RECT  75.168 16.357 75.288 17.891 ;
     RECT  61.8 16.307 62.112 18.133 ;
     RECT  99.36 14.867 100.296 18.179 ;
     RECT  104.256 17.125 105.432 18.179 ;
     RECT  125.424 17.123 126.912 18.179 ;
     RECT  18.6 17.219 19.032 18.181 ;
     RECT  45.6 17.315 45.912 18.181 ;
     RECT  83.232 17.267 83.712 18.181 ;
     RECT  88.8 17.653 89.688 18.181 ;
     RECT  98.064 17.845 98.088 18.181 ;
     RECT  119.904 17.123 124.248 18.181 ;
     RECT  67.2 17.123 68.376 18.371 ;
     RECT  34.56 16.739 35.592 18.419 ;
     RECT  54.912 17.653 54.936 18.419 ;
     RECT  24 16.835 24.312 18.421 ;
     RECT  109.008 17.603 109.032 18.421 ;
     RECT  110.4 17.459 111.912 18.421 ;
     RECT  75.168 17.891 75.192 18.565 ;
     RECT  69.888 17.797 70.68 18.611 ;
     RECT  94.08 17.171 94.68 18.659 ;
     RECT  4.512 16.883 4.536 18.661 ;
     RECT  119.904 18.181 124.824 18.661 ;
     RECT  29.4 17.651 29.712 18.709 ;
     RECT  31.584 17.507 31.608 18.709 ;
     RECT  102.576 17.605 103.08 18.709 ;
     RECT  44.736 18.181 45.912 18.755 ;
     RECT  49.968 18.181 49.992 18.755 ;
     RECT  5.664 18.037 5.688 18.851 ;
     RECT  25.728 17.461 25.8 18.851 ;
     RECT  52.464 18.037 52.488 18.851 ;
     RECT  125.904 18.179 126.912 18.851 ;
     RECT  109.008 18.421 111.912 18.853 ;
     RECT  40.2 17.459 41.304 18.947 ;
     RECT  74.928 18.565 75.192 18.947 ;
     RECT  113.664 17.699 113.688 18.949 ;
     RECT  23.04 18.421 24.312 18.995 ;
     RECT  115.8 17.603 118.728 18.995 ;
     RECT  99.6 18.179 100.296 18.997 ;
     RECT  25.728 18.851 25.752 19.091 ;
     RECT  109.008 18.853 112.008 19.091 ;
     RECT  83.232 18.181 83.832 19.141 ;
     RECT  99.6 18.997 100.968 19.187 ;
     RECT  104.88 18.179 105.432 19.189 ;
     RECT  102.576 18.709 103.848 19.237 ;
     RECT  104.88 19.189 105.48 19.237 ;
     RECT  115.8 18.995 118.104 19.283 ;
     RECT  56.4 17.603 56.712 19.285 ;
     RECT  76.752 17.605 76.776 19.285 ;
     RECT  113.424 18.949 113.688 19.331 ;
     RECT  18.6 18.181 19.08 19.333 ;
     RECT  60.72 19.093 60.744 19.333 ;
     RECT  61.8 18.133 62.568 19.333 ;
     RECT  109.008 19.091 111.912 19.333 ;
     RECT  119.856 18.661 124.824 19.333 ;
     RECT  60.72 19.333 62.568 19.475 ;
     RECT  69.888 18.611 70.104 19.523 ;
     RECT  98.064 18.181 98.616 19.523 ;
     RECT  76.608 19.285 76.776 19.525 ;
     RECT  78 14.147 78.312 19.525 ;
     RECT  13.104 17.891 13.512 19.571 ;
     RECT  18.48 19.333 19.08 19.667 ;
     RECT  79.584 18.709 79.608 19.763 ;
     RECT  4.512 18.661 4.632 19.765 ;
     RECT  56.4 19.285 57.048 19.765 ;
     RECT  4.512 19.765 5.112 19.811 ;
     RECT  82.272 19.141 83.832 19.811 ;
     RECT  88.8 18.181 90.072 19.811 ;
     RECT  102.576 19.237 105.48 19.811 ;
     RECT  92.88 17.171 92.904 19.813 ;
     RECT  45.216 18.755 45.912 19.909 ;
     RECT  106.704 17.699 107.256 19.909 ;
     RECT  113.664 19.331 113.688 19.909 ;
     RECT  29.4 18.709 31.608 20.003 ;
     RECT  45.216 19.909 46.392 20.003 ;
     RECT  102.576 19.811 105.432 20.003 ;
     RECT  98.064 19.523 98.088 20.005 ;
     RECT  83.232 19.811 83.832 20.243 ;
     RECT  119.856 19.333 125.448 20.243 ;
     RECT  74.928 18.947 75.144 20.291 ;
     RECT  76.608 19.525 78.312 20.293 ;
     RECT  27.552 17.507 27.72 20.339 ;
     RECT  69.888 19.523 69.912 20.339 ;
     RECT  76.608 20.293 79.224 20.339 ;
     RECT  120 20.243 125.448 20.339 ;
     RECT  67.2 18.371 67.512 20.341 ;
     RECT  99.6 19.187 100.872 20.389 ;
     RECT  102.576 20.003 102.6 20.389 ;
     RECT  103.824 20.003 105.432 20.435 ;
     RECT  106.704 19.909 107.784 20.483 ;
     RECT  120.048 20.339 125.448 20.483 ;
     RECT  56.4 19.765 57.144 20.485 ;
     RECT  92.784 19.813 92.904 20.485 ;
     RECT  115.8 19.283 117.576 20.485 ;
     RECT  18.48 19.667 18.912 20.579 ;
     RECT  60.72 19.475 62.232 20.579 ;
     RECT  75.12 20.291 75.144 20.579 ;
     RECT  94.08 18.659 94.512 20.579 ;
     RECT  99.6 20.389 102.6 20.579 ;
     RECT  108.912 19.333 111.912 20.579 ;
     RECT  97.728 20.005 98.088 20.581 ;
     RECT  37.248 19.813 37.272 20.627 ;
     RECT  113.664 19.909 113.736 20.627 ;
     RECT  96.672 19.237 96.696 20.629 ;
     RECT  97.728 20.581 98.616 20.629 ;
     RECT  101.664 20.579 102.6 20.675 ;
     RECT  29.4 20.003 30.648 20.819 ;
     RECT  22.32 19.621 23.016 20.915 ;
     RECT  108.912 20.579 109.032 20.915 ;
     RECT  37.056 20.773 37.08 21.011 ;
     RECT  110.112 20.579 111.912 21.013 ;
     RECT  113.664 20.627 113.688 21.013 ;
     RECT  7.8 16.691 9.72 21.061 ;
     RECT  61.44 20.579 62.232 21.061 ;
     RECT  80.832 18.181 80.856 21.061 ;
     RECT  34.56 18.419 35.112 21.107 ;
     RECT  80.832 21.061 80.952 21.107 ;
     RECT  96.672 20.629 98.616 21.107 ;
     RECT  2.4 16.019 2.712 21.109 ;
     RECT  45.6 20.003 46.392 21.155 ;
     RECT  49.776 20.149 49.8 21.155 ;
     RECT  83.28 20.243 83.832 21.155 ;
     RECT  88.8 19.811 89.688 21.155 ;
     RECT  99.6 20.579 100.296 21.155 ;
     RECT  110.112 21.013 113.688 21.155 ;
     RECT  61.44 21.061 62.76 21.299 ;
     RECT  104.064 20.435 105.432 21.299 ;
     RECT  76.752 20.339 79.224 21.347 ;
     RECT  80.928 21.107 80.952 21.347 ;
     RECT  4.608 19.811 5.112 21.349 ;
     RECT  76.752 21.347 78.648 21.395 ;
     RECT  115.8 20.485 117.72 21.397 ;
     RECT  83.4 21.155 83.832 21.443 ;
     RECT  108.912 20.915 108.936 21.443 ;
     RECT  64.176 21.109 64.2 21.491 ;
     RECT  48.768 19.813 48.792 21.493 ;
     RECT  107.232 20.483 107.784 21.493 ;
     RECT  61.44 21.299 62.328 21.539 ;
     RECT  96.96 21.107 98.616 21.539 ;
     RECT  114.864 21.397 117.72 21.541 ;
     RECT  104.88 21.299 105.432 21.637 ;
     RECT  114.864 21.541 118.488 21.637 ;
     RECT  4.56 21.349 5.112 21.683 ;
     RECT  27.024 21.061 27.048 21.683 ;
     RECT  82.08 20.725 82.104 21.683 ;
     RECT  120.048 20.483 124.68 21.683 ;
     RECT  59.184 20.917 59.208 21.875 ;
     RECT  48.768 21.493 49.656 21.971 ;
     RECT  114.864 21.637 118.536 21.971 ;
     RECT  92.304 20.485 92.904 22.021 ;
     RECT  94.2 20.579 94.512 22.021 ;
     RECT  38.112 21.637 38.136 22.117 ;
     RECT  104.88 21.637 105.672 22.163 ;
     RECT  24 18.995 24.312 22.165 ;
     RECT  75.072 21.781 75.096 22.165 ;
     RECT  76.752 21.395 76.776 22.165 ;
     RECT  88.8 21.155 89.112 22.165 ;
     RECT  101.664 20.675 101.688 22.165 ;
     RECT  92.304 22.021 94.512 22.211 ;
     RECT  96.96 21.539 97.032 22.211 ;
     RECT  115.104 21.971 118.536 22.211 ;
     RECT  22.32 20.915 22.344 22.213 ;
     RECT  7.8 21.061 10.392 22.259 ;
     RECT  54.144 20.965 54.168 22.259 ;
     RECT  61.44 21.539 62.232 22.259 ;
     RECT  75.072 22.165 76.776 22.259 ;
     RECT  123.552 21.683 124.68 22.259 ;
     RECT  123.696 22.259 124.68 22.309 ;
     RECT  98.064 21.539 98.616 22.453 ;
     RECT  99.6 21.155 100.248 22.453 ;
     RECT  10.368 22.259 10.392 22.499 ;
     RECT  2.4 21.109 2.904 22.547 ;
     RECT  7.8 22.259 8.856 22.547 ;
     RECT  107.232 21.493 108.072 22.547 ;
     RECT  110.112 21.155 111.912 22.547 ;
     RECT  123.696 22.309 124.776 22.595 ;
     RECT  67.2 20.341 68.424 22.739 ;
     RECT  75.072 22.259 76.392 22.739 ;
     RECT  108.048 22.547 108.072 22.739 ;
     RECT  115.8 22.211 118.536 22.739 ;
     RECT  29.4 20.819 29.712 22.741 ;
     RECT  40.2 18.947 40.512 22.741 ;
     RECT  120.048 21.683 122.52 22.741 ;
     RECT  126.48 18.851 126.912 22.741 ;
     RECT  16.848 21.637 16.872 22.787 ;
     RECT  24 22.165 25.08 22.787 ;
     RECT  78 21.395 78.648 22.787 ;
     RECT  45.6 21.155 45.912 22.789 ;
     RECT  22.08 22.213 22.344 22.883 ;
     RECT  61.536 22.259 62.232 22.883 ;
     RECT  92.592 22.211 94.512 22.883 ;
     RECT  115.8 22.739 118.488 22.883 ;
     RECT  88.8 22.165 89.448 22.979 ;
     RECT  112.896 21.155 112.92 22.979 ;
     RECT  75.984 22.739 76.392 23.075 ;
     RECT  97.008 22.211 97.032 23.125 ;
     RECT  98.064 22.453 100.248 23.125 ;
     RECT  117.696 22.883 118.488 23.171 ;
     RECT  72.6 17.603 72.912 23.173 ;
     RECT  97.008 23.125 100.248 23.315 ;
     RECT  51 14.819 51.312 23.317 ;
     RECT  104.88 22.163 105.432 23.317 ;
     RECT  45.6 22.789 46.008 23.363 ;
     RECT  97.008 23.315 97.464 23.363 ;
     RECT  101.664 22.165 102.312 23.363 ;
     RECT  2.4 22.547 2.856 23.411 ;
     RECT  5.088 21.683 5.112 23.411 ;
     RECT  61.536 22.883 62.112 23.411 ;
     RECT  87.168 22.645 87.192 23.411 ;
     RECT  98.64 23.315 100.248 23.411 ;
     RECT  110.4 22.547 111.912 23.411 ;
     RECT  49.488 21.971 49.656 23.555 ;
     RECT  98.64 23.411 99.912 23.555 ;
     RECT  102.048 23.363 102.312 23.555 ;
     RECT  115.8 22.883 116.28 23.555 ;
     RECT  86.064 22.741 86.088 23.557 ;
     RECT  29.04 22.741 29.712 23.603 ;
     RECT  34.8 21.107 35.112 23.605 ;
     RECT  69.504 23.317 69.528 23.653 ;
     RECT  40.08 22.741 40.512 23.699 ;
     RECT  14.496 22.741 14.52 23.795 ;
     RECT  104.496 23.317 105.432 23.797 ;
     RECT  74.784 23.317 74.808 23.845 ;
     RECT  78 22.787 78.408 23.845 ;
     RECT  30.816 23.317 30.84 23.893 ;
     RECT  80.592 22.885 80.616 23.893 ;
     RECT  94.2 22.883 94.512 23.893 ;
     RECT  117.936 23.171 118.488 23.893 ;
     RECT  97.44 23.363 97.464 23.939 ;
     RECT  92.592 22.883 92.904 23.941 ;
     RECT  94.2 23.893 94.68 23.941 ;
     RECT  10.464 22.789 10.488 23.987 ;
     RECT  51 23.317 51.96 23.987 ;
     RECT  92.592 23.941 94.68 23.987 ;
     RECT  110.4 23.411 111.528 23.987 ;
     RECT  119.664 22.741 122.52 23.987 ;
     RECT  49.488 23.555 49.512 24.037 ;
     RECT  49.344 24.037 49.512 24.083 ;
     RECT  69.504 23.653 70.008 24.083 ;
     RECT  80.592 23.893 81.576 24.083 ;
     RECT  48.144 23.125 48.168 24.085 ;
     RECT  49.344 24.083 49.368 24.085 ;
     RECT  34.8 23.605 35.208 24.131 ;
     RECT  48.144 24.085 49.368 24.131 ;
     RECT  86.064 23.557 86.952 24.467 ;
     RECT  120.912 23.987 122.472 24.467 ;
     RECT  81.552 24.083 81.576 24.469 ;
     RECT  83.4 21.443 83.712 24.469 ;
     RECT  104.496 23.797 105.768 24.469 ;
     RECT  117.936 23.893 118.536 24.469 ;
     RECT  126.432 22.741 126.912 24.469 ;
     RECT  120.912 24.467 121.992 24.515 ;
     RECT  74.784 23.845 75.288 24.517 ;
     RECT  76.368 23.075 76.392 24.517 ;
     RECT  99.6 23.555 99.912 24.517 ;
     RECT  22.32 22.883 22.344 24.563 ;
     RECT  92.88 23.987 94.68 24.563 ;
     RECT  102.048 23.555 102.072 24.563 ;
     RECT  117.408 24.469 118.536 24.563 ;
     RECT  120.912 24.515 121.512 24.563 ;
     RECT  124.08 22.595 124.776 24.563 ;
     RECT  7.8 22.547 8.328 24.611 ;
     RECT  104.016 24.469 105.768 24.611 ;
     RECT  110.4 23.987 111.144 24.611 ;
     RECT  124.08 24.563 124.2 24.611 ;
     RECT  61.8 23.411 62.112 24.709 ;
     RECT  19.968 22.453 19.992 24.805 ;
     RECT  19.968 24.805 20.136 24.851 ;
     RECT  43.008 23.893 43.032 24.899 ;
     RECT  78 23.845 79.272 24.899 ;
     RECT  34.8 24.131 35.112 24.901 ;
     RECT  24 22.787 24.312 24.949 ;
     RECT  94.032 24.563 94.68 24.949 ;
     RECT  115.8 23.555 116.232 24.995 ;
     RECT  117.408 24.563 117.432 24.995 ;
     RECT  67.2 22.739 67.512 24.997 ;
     RECT  84.912 24.853 84.936 25.043 ;
     RECT  45.6 23.363 45.912 25.045 ;
     RECT  47.472 24.757 47.496 25.045 ;
     RECT  71.808 23.173 72.912 25.045 ;
     RECT  86.928 24.467 86.952 25.045 ;
     RECT  88.8 22.979 89.112 25.045 ;
     RECT  108.96 23.797 108.984 25.091 ;
     RECT  24 24.949 24.408 25.093 ;
     RECT  94.032 24.949 94.728 25.093 ;
     RECT  118.512 24.563 118.536 25.139 ;
     RECT  124.08 24.611 124.104 25.139 ;
     RECT  81.552 24.469 83.712 25.187 ;
     RECT  7.8 24.611 8.112 25.237 ;
     RECT  74.784 24.517 76.392 25.285 ;
     RECT  94.032 25.093 94.776 25.331 ;
     RECT  74.64 25.285 76.392 25.333 ;
     RECT  66.384 24.997 67.512 25.429 ;
     RECT  125.904 24.469 126.912 25.429 ;
     RECT  81.696 25.187 83.712 25.475 ;
     RECT  55.248 25.045 55.272 25.477 ;
     RECT  66.384 25.429 67.944 25.571 ;
     RECT  74.64 25.333 76.536 25.571 ;
     RECT  110.4 24.611 110.808 25.571 ;
     RECT  119.664 23.987 119.688 25.573 ;
     RECT  125.856 25.429 126.912 25.573 ;
     RECT  45.6 25.045 47.496 25.621 ;
     RECT  48.912 24.131 49.368 25.621 ;
     RECT  55.2 25.477 55.272 25.621 ;
     RECT  80.304 25.573 80.328 25.621 ;
     RECT  125.376 25.573 126.912 25.621 ;
     RECT  71.472 25.045 72.912 25.667 ;
     RECT  66.384 25.571 67.512 25.715 ;
     RECT  86.928 25.045 89.112 25.715 ;
     RECT  99.6 24.517 100.296 25.715 ;
     RECT  61.056 24.709 62.112 25.717 ;
     RECT  121.2 24.563 121.512 25.717 ;
     RECT  14.976 24.469 15 25.763 ;
     RECT  20.112 24.851 20.136 25.763 ;
     RECT  30.816 23.893 30.936 25.763 ;
     RECT  24 25.093 24.696 25.811 ;
     RECT  38.112 22.117 38.856 25.811 ;
     RECT  51 23.987 51.312 25.813 ;
     RECT  114.72 25.573 114.744 25.813 ;
     RECT  115.8 24.995 116.112 25.813 ;
     RECT  40.2 23.699 40.512 25.861 ;
     RECT  55.2 25.621 55.32 25.861 ;
     RECT  92.88 24.563 92.904 25.861 ;
     RECT  94.032 25.331 94.728 25.861 ;
     RECT  83.4 25.475 83.712 25.957 ;
     RECT  53.568 23.125 53.592 26.005 ;
     RECT  45.6 25.621 49.368 26.053 ;
     RECT  52.944 26.005 53.592 26.053 ;
     RECT  83.4 25.957 84.504 26.053 ;
     RECT  119.664 25.573 119.976 26.053 ;
     RECT  121.2 25.717 121.608 26.053 ;
     RECT  7.584 25.237 8.112 26.101 ;
     RECT  99.6 25.715 100.2 26.147 ;
     RECT  42.768 25.621 42.792 26.149 ;
     RECT  52.944 26.053 53.64 26.149 ;
     RECT  54.864 25.861 55.32 26.149 ;
     RECT  104.016 24.611 105.312 26.197 ;
     RECT  114.72 25.813 116.112 26.197 ;
     RECT  125.28 25.621 126.912 26.197 ;
     RECT  92.88 25.861 94.728 26.243 ;
     RECT  96.912 25.573 96.936 26.243 ;
     RECT  42.768 26.149 43.704 26.245 ;
     RECT  80.064 25.621 80.328 26.245 ;
     RECT  114.72 26.197 116.904 26.291 ;
     RECT  69.984 24.083 70.008 26.293 ;
     RECT  18.6 20.579 18.912 26.341 ;
     RECT  24 25.811 24.504 26.387 ;
     RECT  91.296 26.341 91.32 26.389 ;
     RECT  74.64 25.571 75.288 26.437 ;
     RECT  86.928 25.715 86.952 26.437 ;
     RECT  71.808 25.667 72.912 26.483 ;
     RECT  86.16 26.437 86.952 26.483 ;
     RECT  56.4 20.485 57.336 26.485 ;
     RECT  17.088 26.341 17.112 26.531 ;
     RECT  103.68 26.197 105.312 26.579 ;
     RECT  61.056 25.717 62.472 26.581 ;
     RECT  78 24.899 78.744 26.627 ;
     RECT  38.112 25.811 38.136 26.629 ;
     RECT  80.064 26.245 80.664 26.629 ;
     RECT  76.368 25.571 76.536 26.675 ;
     RECT  119.664 26.053 121.608 26.675 ;
     RECT  107.424 24.181 107.448 26.677 ;
     RECT  73.968 26.437 75.288 26.725 ;
     RECT  76.368 26.675 76.392 26.725 ;
     RECT  52.944 26.149 55.32 26.819 ;
     RECT  73.968 26.725 76.392 26.819 ;
     RECT  81.696 25.475 82.152 26.819 ;
     RECT  45.6 26.053 49.656 26.821 ;
     RECT  50.88 25.813 51.312 26.821 ;
     RECT  115.8 26.291 116.904 26.867 ;
     RECT  53.952 26.819 55.32 26.869 ;
     RECT  56.4 26.485 57.576 26.869 ;
     RECT  42.672 26.245 43.704 26.963 ;
     RECT  53.952 26.869 57.576 27.011 ;
     RECT  108.864 26.869 108.888 27.059 ;
     RECT  13.2 19.571 13.512 27.157 ;
     RECT  7.584 26.101 8.232 27.203 ;
     RECT  16.656 26.869 16.68 27.203 ;
     RECT  34.608 24.901 35.112 27.205 ;
     RECT  72.432 26.483 72.912 27.251 ;
     RECT  18.48 26.341 18.912 27.253 ;
     RECT  66.432 25.715 67.512 27.301 ;
     RECT  82.128 26.819 82.152 27.301 ;
     RECT  103.92 26.579 105.312 27.301 ;
     RECT  103.92 27.301 105.672 27.347 ;
     RECT  114.72 26.291 114.744 27.347 ;
     RECT  37.872 26.629 38.136 27.349 ;
     RECT  61.056 26.581 63.24 27.349 ;
     RECT  92.88 26.243 94.632 27.349 ;
     RECT  37.872 27.349 38.184 27.395 ;
     RECT  42.672 26.963 43.656 27.395 ;
     RECT  61.008 27.349 63.24 27.395 ;
     RECT  24 26.387 24.312 27.397 ;
     RECT  124.8 26.197 126.912 27.397 ;
     RECT  91.152 26.389 91.32 27.445 ;
     RECT  124.08 27.397 126.912 27.445 ;
     RECT  99.6 26.147 100.008 27.637 ;
     RECT  34.272 27.205 35.112 27.683 ;
     RECT  4.56 26.773 4.584 27.731 ;
     RECT  32.16 27.061 32.184 27.733 ;
     RECT  78 26.627 78.408 27.781 ;
     RECT  34.608 27.683 35.112 27.829 ;
     RECT  29.4 23.603 29.712 27.877 ;
     RECT  30.816 25.763 30.84 27.877 ;
     RECT  59.856 27.733 59.88 27.877 ;
     RECT  77.232 27.781 78.408 27.877 ;
     RECT  109.248 27.589 109.272 27.877 ;
     RECT  110.4 25.571 110.712 27.877 ;
     RECT  92.88 27.349 95.208 27.923 ;
     RECT  90.96 27.445 91.32 27.925 ;
     RECT  92.88 27.923 93.096 27.925 ;
     RECT  34.608 27.829 36.024 28.019 ;
     RECT  115.8 26.867 116.76 28.165 ;
     RECT  12.336 27.157 13.512 28.259 ;
     RECT  99.6 27.637 100.872 28.259 ;
     RECT  77.232 27.877 78.696 28.357 ;
     RECT  79.776 26.629 80.664 28.357 ;
     RECT  73.968 26.819 75.528 28.403 ;
     RECT  32.16 27.733 33.048 28.405 ;
     RECT  52.944 26.819 52.968 28.405 ;
     RECT  53.952 27.011 55.32 28.405 ;
     RECT  56.4 27.011 57.576 28.405 ;
     RECT  72.48 27.251 72.912 28.405 ;
     RECT  59.04 27.877 59.88 28.451 ;
     RECT  118.08 27.637 118.104 28.451 ;
     RECT  24 27.397 24.456 28.453 ;
     RECT  32.064 28.405 33.048 28.453 ;
     RECT  66.432 27.301 68.04 28.453 ;
     RECT  77.232 28.357 80.664 28.453 ;
     RECT  107.088 26.677 107.448 28.453 ;
     RECT  119.664 26.675 121.512 28.453 ;
     RECT  61.008 27.395 62.328 28.499 ;
     RECT  98.592 25.429 98.616 28.501 ;
     RECT  99.6 28.259 99.912 28.501 ;
     RECT  109.248 27.877 110.712 28.501 ;
     RECT  82.128 27.301 82.248 28.547 ;
     RECT  102.672 26.197 102.696 28.549 ;
     RECT  104.064 27.347 105.672 28.549 ;
     RECT  98.592 28.501 99.912 28.643 ;
     RECT  108.816 28.501 110.712 28.643 ;
     RECT  10.128 27.205 10.152 28.787 ;
     RECT  90.96 27.925 93.096 28.787 ;
     RECT  129.408 28.693 129.432 28.835 ;
     RECT  106.896 28.453 107.448 28.837 ;
     RECT  71.904 28.405 72.912 28.885 ;
     RECT  34.8 28.019 36.024 28.931 ;
     RECT  38.16 27.395 38.184 28.931 ;
     RECT  59.04 28.451 59.064 28.979 ;
     RECT  106.896 28.837 107.64 28.979 ;
     RECT  69.264 26.293 70.008 29.027 ;
     RECT  77.232 28.453 80.808 29.029 ;
     RECT  83.4 26.053 85.128 29.029 ;
     RECT  86.16 26.483 86.184 29.029 ;
     RECT  92.064 28.787 93.096 29.029 ;
     RECT  94.2 27.923 94.512 29.029 ;
     RECT  61.008 28.499 62.112 29.075 ;
     RECT  97.728 28.933 97.752 29.075 ;
     RECT  123.264 27.445 126.912 29.077 ;
     RECT  32.064 28.453 33.576 29.123 ;
     RECT  76.704 29.029 80.808 29.123 ;
     RECT  112.848 28.837 112.872 29.125 ;
     RECT  112.848 29.125 112.968 29.171 ;
     RECT  29.4 27.877 30.84 29.219 ;
     RECT  102.672 28.549 105.672 29.219 ;
     RECT  45.6 26.821 51.312 29.221 ;
     RECT  52.464 28.405 52.968 29.221 ;
     RECT  80.64 29.123 80.808 29.221 ;
     RECT  83.4 29.029 86.184 29.267 ;
     RECT  119.664 28.453 121.992 29.267 ;
     RECT  96.336 28.261 96.36 29.315 ;
     RECT  123.168 29.077 126.912 29.315 ;
     RECT  99.6 28.643 99.912 29.317 ;
     RECT  66.096 28.453 68.04 29.459 ;
     RECT  76.704 29.123 79.08 29.507 ;
     RECT  99.6 29.317 100.008 29.507 ;
     RECT  41.904 28.933 41.928 29.509 ;
     RECT  43.056 27.395 43.656 29.509 ;
     RECT  53.952 28.405 57.576 29.509 ;
     RECT  71.808 28.885 72.912 29.509 ;
     RECT  74.064 28.403 75.528 29.509 ;
     RECT  82.128 28.547 82.152 29.509 ;
     RECT  15.312 28.405 15.336 29.555 ;
     RECT  45.6 29.221 52.968 29.555 ;
     RECT  61.2 29.075 62.112 29.557 ;
     RECT  66.096 29.459 67.608 29.605 ;
     RECT  69.408 29.027 70.008 29.605 ;
     RECT  115.8 28.165 116.904 29.605 ;
     RECT  97.68 29.221 97.704 29.653 ;
     RECT  40.2 25.861 40.776 29.699 ;
     RECT  81.888 29.509 82.152 29.699 ;
     RECT  83.4 29.267 84.456 29.699 ;
     RECT  25.68 24.181 25.704 29.747 ;
     RECT  86.064 29.267 86.184 29.747 ;
     RECT  119.904 29.267 121.992 29.747 ;
     RECT  53.952 29.509 58.776 29.795 ;
     RECT  71.808 29.509 75.528 29.795 ;
     RECT  75.504 29.795 75.528 29.843 ;
     RECT  112.944 29.171 112.968 29.843 ;
     RECT  13.2 28.259 13.512 29.845 ;
     RECT  18.384 27.253 18.912 29.891 ;
     RECT  26.88 29.797 26.904 29.987 ;
     RECT  40.2 29.699 40.728 30.037 ;
     RECT  53.952 29.795 57.048 30.083 ;
     RECT  71.808 29.795 74.136 30.083 ;
     RECT  109.248 28.643 110.712 30.083 ;
     RECT  45.6 29.555 52.488 30.085 ;
     RECT  99.6 29.507 99.912 30.085 ;
     RECT  78 29.507 79.08 30.133 ;
     RECT  80.64 29.221 80.904 30.133 ;
     RECT  7.8 27.203 8.232 30.181 ;
     RECT  58.464 29.795 58.776 30.275 ;
     RECT  92.064 29.029 94.512 30.275 ;
     RECT  53.952 30.083 56.904 30.323 ;
     RECT  69.408 29.605 70.2 30.419 ;
     RECT  97.584 29.653 97.704 30.419 ;
     RECT  45.264 30.085 52.488 30.469 ;
     RECT  32.064 29.123 32.088 30.565 ;
     RECT  54.384 30.323 56.904 30.611 ;
     RECT  123.168 29.315 125.4 30.611 ;
     RECT  23.904 28.453 24.456 30.613 ;
     RECT  69.504 30.419 70.2 30.613 ;
     RECT  88.8 25.715 89.112 30.613 ;
     RECT  81.888 29.699 81.912 30.659 ;
     RECT  115.8 29.605 117.336 30.659 ;
     RECT  13.2 29.845 13.608 30.707 ;
     RECT  32.064 30.565 32.52 30.707 ;
     RECT  78 30.133 80.904 30.709 ;
     RECT  77.856 30.709 80.904 30.755 ;
     RECT  97.584 30.419 97.608 30.755 ;
     RECT  41.904 29.509 43.656 30.757 ;
     RECT  44.64 30.469 52.488 30.757 ;
     RECT  65.376 29.605 67.608 30.803 ;
     RECT  61.2 29.557 63.096 30.805 ;
     RECT  3.936 30.709 3.96 30.851 ;
     RECT  66.336 30.803 67.608 30.851 ;
     RECT  106.896 28.979 107.544 30.853 ;
     RECT  23.904 30.613 24.504 30.901 ;
     RECT  76.704 29.507 76.728 30.947 ;
     RECT  41.904 30.757 52.488 30.949 ;
     RECT  94.2 30.275 94.512 30.949 ;
     RECT  40.08 30.037 40.728 30.995 ;
     RECT  115.8 30.659 117.24 31.045 ;
     RECT  7.8 30.181 8.616 31.139 ;
     RECT  23.904 30.901 24.744 31.139 ;
     RECT  54.432 30.611 56.904 31.139 ;
     RECT  113.856 30.517 113.88 31.139 ;
     RECT  119.904 29.747 121.608 31.139 ;
     RECT  123.36 30.611 125.4 31.139 ;
     RECT  83.4 29.699 84.36 31.141 ;
     RECT  120.384 31.139 121.608 31.187 ;
     RECT  123.36 31.139 123.48 31.187 ;
     RECT  105 29.219 105.672 31.189 ;
     RECT  94.2 30.949 95.016 31.235 ;
     RECT  23.904 31.139 24.504 31.237 ;
     RECT  55.776 31.139 56.904 31.237 ;
     RECT  58.464 30.275 58.488 31.237 ;
     RECT  77.856 30.755 80.808 31.379 ;
     RECT  86.16 29.747 86.184 31.379 ;
     RECT  124.752 31.139 125.4 31.379 ;
     RECT  60.864 30.805 63.096 31.381 ;
     RECT  32.064 30.707 32.088 31.427 ;
     RECT  126.6 29.315 126.912 31.429 ;
     RECT  125.088 31.379 125.112 31.475 ;
     RECT  30.816 29.219 30.84 31.477 ;
     RECT  99.168 30.085 99.912 31.477 ;
     RECT  69.504 30.613 70.488 31.523 ;
     RECT  77.856 31.379 78.696 31.523 ;
     RECT  80.4 31.379 80.808 31.523 ;
     RECT  115.152 31.045 117.24 31.523 ;
     RECT  121.2 31.187 121.608 31.525 ;
     RECT  102.672 29.219 103.56 31.621 ;
     RECT  60.816 31.381 63.096 31.669 ;
     RECT  64.224 22.213 64.248 31.669 ;
     RECT  30.816 31.477 31.656 31.715 ;
     RECT  106.896 30.853 107.736 31.717 ;
     RECT  109.248 30.083 109.272 31.717 ;
     RECT  18.432 29.891 18.912 31.763 ;
     RECT  20.976 31.285 21 31.763 ;
     RECT  34.8 28.931 35.112 31.765 ;
     RECT  60.816 31.669 64.248 31.813 ;
     RECT  104.832 31.189 105.672 31.813 ;
     RECT  106.896 31.717 109.272 31.813 ;
     RECT  69.504 31.523 69.528 31.859 ;
     RECT  18.6 31.763 18.912 31.861 ;
     RECT  97.344 31.477 97.368 31.909 ;
     RECT  102.672 31.621 103.752 31.909 ;
     RECT  104.832 31.813 109.272 31.909 ;
     RECT  110.304 30.083 110.712 31.909 ;
     RECT  38.064 31.093 38.088 31.955 ;
     RECT  72.192 30.083 74.136 31.955 ;
     RECT  80.4 31.523 80.664 31.955 ;
     RECT  83.184 31.141 84.36 31.955 ;
     RECT  99.168 31.477 100.872 31.955 ;
     RECT  102.672 31.909 110.712 31.955 ;
     RECT  96.192 31.909 96.216 31.957 ;
     RECT  117.216 31.523 117.24 31.957 ;
     RECT  94.2 31.235 94.68 32.003 ;
     RECT  103.344 31.955 110.712 32.003 ;
     RECT  99.6 31.955 100.872 32.051 ;
     RECT  59.808 30.229 59.832 32.053 ;
     RECT  60.816 31.813 64.968 32.053 ;
     RECT  23.232 31.237 24.504 32.099 ;
     RECT  95.76 31.957 96.216 32.099 ;
     RECT  41.904 30.949 52.728 32.149 ;
     RECT  88.32 30.613 89.112 32.195 ;
     RECT  104.16 32.003 110.712 32.195 ;
     RECT  95.76 32.099 95.88 32.243 ;
     RECT  121.2 31.525 121.992 32.243 ;
     RECT  97.344 31.909 97.512 32.245 ;
     RECT  66.336 30.851 67.512 32.291 ;
     RECT  72.192 31.955 72.912 32.293 ;
     RECT  110.112 32.195 110.712 32.293 ;
     RECT  36.624 30.133 36.648 32.341 ;
     RECT  54.432 31.139 54.456 32.341 ;
     RECT  112.848 32.197 112.872 32.387 ;
     RECT  55.776 31.237 58.488 32.435 ;
     RECT  33.552 29.123 33.576 32.437 ;
     RECT  36.336 32.341 36.648 32.437 ;
     RECT  110.112 32.293 111.096 32.437 ;
     RECT  126.6 31.429 127.08 32.437 ;
     RECT  97.344 32.245 97.752 32.483 ;
     RECT  92.064 30.275 92.904 32.531 ;
     RECT  94.2 32.003 94.632 32.531 ;
     RECT  100.896 32.341 100.92 32.531 ;
     RECT  115.152 31.523 116.112 32.531 ;
     RECT  14.832 30.997 14.856 32.581 ;
     RECT  126.336 32.437 127.08 32.581 ;
     RECT  126.336 32.581 127.608 32.723 ;
     RECT  13.2 30.707 13.512 32.725 ;
     RECT  115.8 32.531 116.112 32.725 ;
     RECT  121.2 32.243 121.608 32.725 ;
     RECT  23.232 32.099 24.456 32.771 ;
     RECT  92.256 32.531 92.904 32.773 ;
     RECT  94.2 32.531 94.512 32.773 ;
     RECT  23.232 32.771 24.312 32.821 ;
     RECT  30.816 31.715 31.512 32.821 ;
     RECT  32.592 32.437 33.576 32.821 ;
     RECT  54.144 32.341 54.456 32.821 ;
     RECT  30.816 32.821 33.576 32.867 ;
     RECT  22.8 32.821 24.312 32.963 ;
     RECT  104.16 32.195 108.504 33.011 ;
     RECT  41.904 32.149 53.016 33.013 ;
     RECT  54.048 32.821 54.456 33.013 ;
     RECT  13.104 32.725 13.512 33.059 ;
     RECT  59.808 32.053 64.968 33.059 ;
     RECT  74.112 31.955 74.136 33.059 ;
     RECT  76.752 31.285 76.776 33.059 ;
     RECT  90.96 28.787 90.984 33.059 ;
     RECT  104.688 33.011 108.504 33.059 ;
     RECT  97.344 32.483 97.512 33.107 ;
     RECT  105 33.059 108.264 33.107 ;
     RECT  83.184 31.955 83.712 33.155 ;
     RECT  14.832 32.581 15 33.203 ;
     RECT  123.456 31.187 123.48 33.251 ;
     RECT  72.096 32.293 72.912 33.253 ;
     RECT  55.776 32.435 58.008 33.299 ;
     RECT  59.808 33.059 62.856 33.299 ;
     RECT  64.224 33.059 64.968 33.299 ;
     RECT  110.112 32.437 111.192 33.299 ;
     RECT  36.336 32.437 36.888 33.395 ;
     RECT  75.84 33.253 75.864 33.397 ;
     RECT  18.6 31.861 19.368 33.443 ;
     RECT  59.808 33.299 59.832 33.491 ;
     RECT  21.072 33.445 21.096 33.493 ;
     RECT  55.776 33.299 57.624 33.539 ;
     RECT  102.576 33.349 102.6 33.541 ;
     RECT  102.096 33.541 102.6 33.587 ;
     RECT  21.072 33.493 21.624 33.635 ;
     RECT  55.776 33.539 56.712 33.635 ;
     RECT  106.896 33.107 108.264 33.635 ;
     RECT  30.816 32.867 31.848 33.683 ;
     RECT  34.8 31.765 35.208 33.683 ;
     RECT  70.128 33.013 70.152 33.683 ;
     RECT  95.76 32.243 95.784 33.683 ;
     RECT  102.096 33.587 102.12 33.685 ;
     RECT  92.256 32.773 94.512 33.733 ;
     RECT  91.536 33.733 94.512 33.779 ;
     RECT  14.832 33.203 14.856 33.781 ;
     RECT  55.824 33.635 56.712 33.827 ;
     RECT  120.72 32.725 121.608 33.877 ;
     RECT  60.864 33.299 62.856 33.971 ;
     RECT  68.496 32.245 68.52 33.973 ;
     RECT  78 31.523 78.696 34.117 ;
     RECT  30.816 33.683 31.512 34.259 ;
     RECT  33.552 32.867 33.576 34.259 ;
     RECT  21.6 33.635 21.624 34.355 ;
     RECT  36.864 33.395 36.888 34.355 ;
     RECT  68.496 33.973 69.336 34.355 ;
     RECT  75.696 33.397 75.864 34.355 ;
     RECT  80.544 33.013 80.568 34.355 ;
     RECT  91.536 33.779 93 34.355 ;
     RECT  72 33.253 72.912 34.403 ;
     RECT  75.696 34.355 75.72 34.403 ;
     RECT  40.2 30.995 40.728 34.405 ;
     RECT  41.904 33.013 54.648 34.405 ;
     RECT  39.168 32.821 39.192 34.453 ;
     RECT  40.2 34.405 54.648 34.453 ;
     RECT  7.8 31.139 8.232 34.501 ;
     RECT  60.864 33.971 62.112 34.549 ;
     RECT  60.432 34.549 62.112 34.595 ;
     RECT  14.496 33.781 14.856 34.643 ;
     RECT  39.168 34.453 54.648 34.645 ;
     RECT  120.672 33.877 121.608 34.741 ;
     RECT  60.432 34.595 60.456 34.787 ;
     RECT  2.4 23.411 2.712 34.789 ;
     RECT  110.112 33.299 111.144 34.835 ;
     RECT  2.4 34.789 2.808 34.931 ;
     RECT  110.112 34.835 110.712 34.931 ;
     RECT  119.712 34.741 121.608 34.931 ;
     RECT  18.6 33.443 19.176 34.933 ;
     RECT  39.072 34.645 54.648 34.981 ;
     RECT  69.312 34.355 69.336 34.981 ;
     RECT  106.896 33.635 107.784 35.123 ;
     RECT  88.8 32.195 89.112 35.173 ;
     RECT  18 34.933 19.176 35.219 ;
     RECT  39.072 34.981 54.792 35.269 ;
     RECT  39.072 35.269 54.84 35.317 ;
     RECT  5.52 33.829 5.544 35.363 ;
     RECT  6.864 34.501 8.232 35.363 ;
     RECT  72.048 34.403 72.912 35.363 ;
     RECT  80.928 34.789 80.952 35.363 ;
     RECT  38.064 35.317 54.84 35.365 ;
     RECT  78 34.117 78.792 35.413 ;
     RECT  38.064 35.365 55.176 35.459 ;
     RECT  97.344 33.107 97.368 35.461 ;
     RECT  92.16 34.355 93 35.507 ;
     RECT  97.344 35.461 97.512 35.507 ;
     RECT  86.544 34.357 86.568 35.555 ;
     RECT  40.2 35.459 55.176 35.747 ;
     RECT  102 33.685 102.12 35.795 ;
     RECT  76.032 35.317 76.056 35.843 ;
     RECT  7.8 35.363 8.232 35.845 ;
     RECT  67.2 32.291 67.512 35.845 ;
     RECT  69.312 34.981 69.432 35.845 ;
     RECT  18 35.219 18.912 35.939 ;
     RECT  20.88 34.741 20.904 35.939 ;
     RECT  77.52 35.413 78.792 36.035 ;
     RECT  53.616 35.747 55.176 36.037 ;
     RECT  56.4 33.827 56.712 36.037 ;
     RECT  69.312 35.845 69.72 36.085 ;
     RECT  92.256 35.507 93 36.085 ;
     RECT  94.2 33.779 94.512 36.085 ;
     RECT  92.256 36.085 94.512 36.131 ;
     RECT  105 33.107 105.312 36.181 ;
     RECT  69.312 36.085 70.056 36.277 ;
     RECT  69.216 36.277 70.056 36.371 ;
     RECT  117.216 31.957 117.72 36.373 ;
     RECT  96.24 34.117 96.264 36.421 ;
     RECT  106.896 35.123 107.544 36.421 ;
     RECT  12.192 35.749 12.216 36.515 ;
     RECT  38.064 35.459 39.096 36.515 ;
     RECT  53.616 36.037 56.712 36.515 ;
     RECT  126.336 32.723 126.912 36.515 ;
     RECT  88.8 35.173 89.832 36.517 ;
     RECT  67.2 35.845 67.8 36.565 ;
     RECT  69.216 36.371 69.72 36.565 ;
     RECT  72.6 35.363 72.912 36.565 ;
     RECT  99.6 32.051 99.912 36.565 ;
     RECT  106.896 36.421 107.784 36.565 ;
     RECT  30.816 34.259 30.84 36.611 ;
     RECT  72.6 36.565 73.272 36.613 ;
     RECT  74.688 35.749 74.712 36.613 ;
     RECT  21.984 36.037 22.008 36.659 ;
     RECT  72.6 36.613 74.712 36.661 ;
     RECT  104.784 36.181 105.312 36.661 ;
     RECT  99.6 36.565 100.776 36.709 ;
     RECT  106.56 36.565 107.784 36.853 ;
     RECT  7.8 35.845 9.096 36.899 ;
     RECT  72.6 36.661 75.576 36.899 ;
     RECT  99.6 36.709 100.92 36.899 ;
     RECT  106.56 36.853 108.072 36.899 ;
     RECT  64.224 33.299 64.248 36.949 ;
     RECT  65.424 36.565 65.448 36.949 ;
     RECT  104.784 36.661 105.432 36.949 ;
     RECT  100.896 36.899 100.92 36.995 ;
     RECT  40.2 35.747 52.344 36.997 ;
     RECT  7.8 36.899 8.232 37.043 ;
     RECT  72.6 36.899 73.272 37.045 ;
     RECT  77.904 36.035 78.312 37.045 ;
     RECT  67.2 36.565 69.72 37.091 ;
     RECT  98.592 36.853 98.616 37.091 ;
     RECT  124.32 36.565 124.344 37.091 ;
     RECT  18.6 35.939 18.912 37.093 ;
     RECT  34.8 33.683 35.112 37.093 ;
     RECT  120.672 34.931 121.608 37.093 ;
     RECT  104.304 36.949 105.432 37.139 ;
     RECT  67.2 37.091 69.336 37.189 ;
     RECT  104.304 37.139 105.312 37.235 ;
     RECT  117.216 36.373 117.96 37.331 ;
     RECT  17.712 37.093 18.912 37.379 ;
     RECT  74.688 36.899 75.576 37.379 ;
     RECT  102.096 35.795 102.12 37.429 ;
     RECT  3.696 36.421 3.72 37.475 ;
     RECT  65.328 36.949 65.448 37.571 ;
     RECT  40.08 36.997 52.344 37.573 ;
     RECT  64.224 36.949 64.344 37.573 ;
     RECT  115.8 32.725 116.232 37.573 ;
     RECT  117.216 37.331 117.672 37.573 ;
     RECT  115.8 37.573 117.672 37.619 ;
     RECT  117.648 37.619 117.672 37.859 ;
     RECT  40.08 37.573 52.44 37.957 ;
     RECT  72.48 37.045 73.272 37.957 ;
     RECT  80.688 36.997 80.712 38.005 ;
     RECT  65.328 37.571 65.352 38.051 ;
     RECT  29.4 29.219 29.712 38.101 ;
     RECT  72 37.957 73.272 38.147 ;
     RECT  53.664 36.515 56.712 38.149 ;
     RECT  61.44 34.595 62.112 38.149 ;
     RECT  80.16 38.005 80.712 38.149 ;
     RECT  53.664 38.149 57 38.243 ;
     RECT  59.28 36.565 59.304 38.243 ;
     RECT  63.792 37.573 64.344 38.243 ;
     RECT  123.504 37.573 123.528 38.243 ;
     RECT  63.792 38.243 64.248 38.435 ;
     RECT  66.768 37.189 69.336 38.435 ;
     RECT  80.016 38.149 80.712 38.435 ;
     RECT  96.24 36.421 96.36 38.435 ;
     RECT  112.32 37.669 112.344 38.435 ;
     RECT  120.288 37.093 121.608 38.435 ;
     RECT  67.2 38.435 69.336 38.483 ;
     RECT  23.04 32.963 24.312 38.485 ;
     RECT  96.336 38.435 96.36 38.485 ;
     RECT  97.488 35.507 97.512 38.485 ;
     RECT  105 37.235 105.312 38.485 ;
     RECT  5.088 37.429 5.112 38.531 ;
     RECT  96.336 38.485 97.512 38.531 ;
     RECT  14.496 34.643 14.52 38.627 ;
     RECT  75.552 37.379 75.576 38.675 ;
     RECT  92.88 36.131 94.512 38.675 ;
     RECT  110.4 34.931 110.712 38.677 ;
     RECT  61.44 38.149 62.808 38.723 ;
     RECT  40.032 37.957 52.44 38.725 ;
     RECT  77.904 37.045 79.032 38.725 ;
     RECT  99.6 36.899 99.912 38.725 ;
     RECT  102.096 37.429 102.216 38.771 ;
     RECT  34.272 37.093 35.112 38.773 ;
     RECT  97.008 38.531 97.512 38.773 ;
     RECT  69.312 38.483 69.336 38.819 ;
     RECT  88.8 36.517 90.072 38.819 ;
     RECT  120.624 38.435 121.608 38.819 ;
     RECT  106.896 36.899 108.072 38.867 ;
     RECT  34.272 38.773 35.88 39.011 ;
     RECT  80.016 38.435 80.184 39.011 ;
     RECT  121.2 38.819 121.608 39.059 ;
     RECT  6.768 36.901 6.792 39.251 ;
     RECT  86.256 35.845 86.28 39.253 ;
     RECT  2.4 34.931 2.712 39.301 ;
     RECT  18.6 37.379 18.912 39.301 ;
     RECT  29.4 38.101 29.88 39.301 ;
     RECT  38.064 36.515 38.76 39.301 ;
     RECT  53.664 38.243 55.272 39.301 ;
     RECT  29.28 39.301 29.88 39.347 ;
     RECT  31.92 38.005 31.944 39.347 ;
     RECT  34.8 39.011 35.88 39.347 ;
     RECT  99.216 38.725 99.912 39.347 ;
     RECT  107.52 38.867 108.072 39.347 ;
     RECT  97.008 38.773 97.896 39.395 ;
     RECT  102.096 38.771 102.12 39.395 ;
     RECT  104.112 38.485 105.312 39.539 ;
     RECT  22.896 38.485 24.312 39.587 ;
     RECT  56.4 38.243 57 39.587 ;
     RECT  7.8 37.043 8.112 39.589 ;
     RECT  13.2 33.059 13.512 39.589 ;
     RECT  25.68 38.149 25.704 39.779 ;
     RECT  115.8 37.619 116.52 39.827 ;
     RECT  88.8 38.819 89.112 39.829 ;
     RECT  10.8 35.509 10.824 39.875 ;
     RECT  80.016 39.011 80.04 39.875 ;
     RECT  39.936 38.725 52.44 39.923 ;
     RECT  60.432 39.301 60.456 39.923 ;
     RECT  86.112 39.253 86.28 39.923 ;
     RECT  114.096 39.061 114.12 39.923 ;
     RECT  38.064 39.301 38.904 39.971 ;
     RECT  41.52 39.923 52.44 39.971 ;
     RECT  39.936 39.923 40.512 40.019 ;
     RECT  77.472 38.725 79.032 40.019 ;
     RECT  86.112 39.923 86.136 40.019 ;
     RECT  29.28 39.347 29.712 40.067 ;
     RECT  40.032 40.019 40.512 40.067 ;
     RECT  97.44 39.395 97.896 40.115 ;
     RECT  7.584 39.589 8.112 40.117 ;
     RECT  7.584 40.117 8.232 40.163 ;
     RECT  67.2 38.483 68.136 40.259 ;
     RECT  2.4 39.301 3.432 40.307 ;
     RECT  38.88 39.971 38.904 40.307 ;
     RECT  53.664 39.301 55.368 40.307 ;
     RECT  42.048 39.971 52.44 40.355 ;
     RECT  108.048 39.347 108.072 40.355 ;
     RECT  124.416 39.781 124.44 40.355 ;
     RECT  58.176 39.205 58.2 40.451 ;
     RECT  78 40.019 79.032 40.451 ;
     RECT  53.664 40.307 54.168 40.453 ;
     RECT  42.048 40.355 52.392 40.499 ;
     RECT  55.152 40.307 55.368 40.499 ;
     RECT  69.552 39.733 69.576 40.499 ;
     RECT  55.248 40.499 55.368 40.547 ;
     RECT  7.8 40.163 8.232 40.595 ;
     RECT  22.896 39.587 22.92 40.595 ;
     RECT  55.344 40.547 55.368 40.595 ;
     RECT  78 40.451 78.696 40.595 ;
     RECT  110.208 38.677 110.712 40.595 ;
     RECT  111.84 39.637 111.864 40.595 ;
     RECT  13.2 39.589 13.704 40.643 ;
     RECT  115.8 39.827 116.232 40.643 ;
     RECT  94.08 38.675 94.512 40.691 ;
     RECT  97.44 40.115 97.464 40.691 ;
     RECT  99.264 39.347 99.912 40.691 ;
     RECT  31.968 39.829 31.992 40.835 ;
     RECT  61.8 38.723 62.808 40.835 ;
     RECT  72 38.147 72.912 40.835 ;
     RECT  18.6 39.301 19.752 40.883 ;
     RECT  88.8 39.829 89.208 40.883 ;
     RECT  103.152 39.781 103.176 40.931 ;
     RECT  2.4 40.307 2.712 41.049 ;
     RECT  7.8 40.595 8.112 41.049 ;
     RECT  13.2 40.643 13.512 41.049 ;
     RECT  18.6 40.883 18.912 41.049 ;
     RECT  24 39.587 24.312 41.049 ;
     RECT  29.4 40.067 29.712 41.049 ;
     RECT  34.8 39.347 35.112 41.049 ;
     RECT  40.2 40.067 40.512 41.049 ;
     RECT  56.4 39.587 56.712 41.049 ;
     RECT  61.8 40.835 62.112 41.049 ;
     RECT  67.2 40.259 67.512 41.049 ;
     RECT  72.6 40.835 72.912 41.049 ;
     RECT  78 40.595 78.312 41.049 ;
     RECT  83.4 33.155 83.712 41.049 ;
     RECT  88.8 40.883 89.112 41.049 ;
     RECT  94.2 40.691 94.512 41.049 ;
     RECT  99.6 40.691 99.912 41.049 ;
     RECT  105 39.539 105.312 41.049 ;
     RECT  110.4 40.595 110.712 41.049 ;
     RECT  115.8 40.643 116.112 41.049 ;
     RECT  121.2 39.059 121.512 41.049 ;
     RECT  126.6 36.515 126.912 41.049 ;
     RECT  2.4 41.049 2.52 41.063 ;
     RECT  7.8 41.049 7.92 41.063 ;
     RECT  13.2 41.049 13.32 41.063 ;
     RECT  18.6 41.049 18.72 41.063 ;
     RECT  24 41.049 24.12 41.063 ;
     RECT  29.4 41.049 29.52 41.063 ;
     RECT  34.8 41.049 34.92 41.063 ;
     RECT  40.2 41.049 40.32 41.063 ;
     RECT  56.4 41.049 56.52 41.063 ;
     RECT  61.8 41.049 61.92 41.063 ;
     RECT  67.2 41.049 67.32 41.063 ;
     RECT  72.6 41.049 72.72 41.063 ;
     RECT  78 41.049 78.12 41.063 ;
     RECT  83.4 41.049 83.52 41.063 ;
     RECT  88.8 41.049 88.92 41.063 ;
     RECT  94.2 41.049 94.32 41.063 ;
     RECT  99.6 41.049 99.72 41.063 ;
     RECT  105 41.049 105.12 41.063 ;
     RECT  110.4 41.049 110.52 41.063 ;
     RECT  115.8 41.049 115.92 41.063 ;
     RECT  121.2 41.049 121.32 41.063 ;
     RECT  126.6 41.049 126.72 41.063 ;
     RECT  64.224 38.435 64.248 41.411 ;
     RECT  92.88 38.675 92.904 41.603 ;
     RECT  42.048 40.499 52.248 43.091 ;
     RECT  42.144 43.091 52.248 43.152 ;
     RECT  53.472 40.453 54.168 43.152 ;
     RECT  12.432 1.763 12.576 2.725 ;
     RECT  26.856 1.811 27.144 2.773 ;
     RECT  115.92 2.137 117.312 2.151 ;
     RECT  116.112 2.151 117.312 4.019 ;
     RECT  45.912 2.245 46.944 3.203 ;
     RECT  83.712 2.245 85.2 3.299 ;
     RECT  114.648 2.341 115.8 3.299 ;
     RECT  111.336 2.437 112.848 2.675 ;
     RECT  112.872 2.437 113.952 2.675 ;
     RECT  113.136 2.675 113.952 3.397 ;
     RECT  105.432 2.677 106.464 3.875 ;
     RECT  118.584 2.677 119.616 2.819 ;
     RECT  102.792 2.725 103.872 2.821 ;
     RECT  103.896 2.725 105 3.349 ;
     RECT  32.328 2.773 33.744 2.821 ;
     RECT  33.768 2.773 34.8 2.821 ;
     RECT  35.928 2.773 37.008 3.013 ;
     RECT  62.112 2.773 63.216 4.883 ;
     RECT  96.216 2.773 97.344 3.011 ;
     RECT  117.336 2.819 119.616 3.011 ;
     RECT  8.112 2.821 9.552 3.925 ;
     RECT  32.424 2.821 33.744 3.589 ;
     RECT  107.208 2.867 108.288 4.115 ;
     RECT  97.248 3.011 97.344 4.067 ;
     RECT  117.336 3.011 119.64 3.109 ;
     RECT  36.024 3.013 37.008 5.413 ;
     RECT  97.368 3.059 98.04 4.021 ;
     RECT  71.4 3.061 72.6 4.691 ;
     RECT  117.336 3.109 120.624 3.397 ;
     RECT  45.912 3.203 46.008 4.357 ;
     RECT  83.712 3.299 85.224 3.349 ;
     RECT  83.712 3.349 86.112 3.925 ;
     RECT  103.944 3.349 105 3.829 ;
     RECT  69.576 3.395 71.376 4.357 ;
     RECT  10.248 3.397 11.376 3.685 ;
     RECT  11.4 3.397 12.432 3.925 ;
     RECT  117.336 3.397 118.848 4.019 ;
     RECT  118.872 3.397 120.624 4.453 ;
     RECT  94.08 3.587 94.2 5.077 ;
     RECT  32.664 3.589 33.744 3.779 ;
     RECT  68.088 3.637 69.552 3.875 ;
     RECT  111.24 3.731 111.336 5.173 ;
     RECT  32.664 3.779 34.08 4.501 ;
     RECT  92.448 3.875 92.472 3.925 ;
     RECT  105.312 3.875 106.464 5.221 ;
     RECT  8.232 3.925 9.552 4.451 ;
     RECT  64.104 3.925 65.568 4.405 ;
     RECT  72.912 3.925 74.064 5.747 ;
     RECT  84.552 3.925 86.112 4.357 ;
     RECT  91.848 3.925 92.472 5.077 ;
     RECT  109.224 3.925 110.4 4.357 ;
     RECT  103.992 3.971 105 5.171 ;
     RECT  116.112 4.019 118.848 4.117 ;
     RECT  97.368 4.021 98.64 4.067 ;
     RECT  97.248 4.067 98.64 4.453 ;
     RECT  117.048 4.117 118.848 4.259 ;
     RECT  82.104 4.259 83.4 6.035 ;
     RECT  116.328 4.259 118.848 4.693 ;
     RECT  70.152 4.357 71.376 4.691 ;
     RECT  84.552 4.357 85.872 5.749 ;
     RECT  64.152 4.405 65.568 4.691 ;
     RECT  8.232 4.451 10.224 4.789 ;
     RECT  97.272 4.453 98.64 5.747 ;
     RECT  118.872 4.453 120.192 5.365 ;
     RECT  33.048 4.501 34.08 5.125 ;
     RECT  109.224 4.547 110.4 4.643 ;
     RECT  91.296 4.643 91.824 5.125 ;
     RECT  70.152 4.691 72.6 5.605 ;
     RECT  116.328 4.693 118.56 5.027 ;
     RECT  9.096 4.789 10.224 5.605 ;
     RECT  62.112 4.883 62.472 6.277 ;
     RECT  37.032 4.981 38.448 6.181 ;
     RECT  116.328 5.027 117.192 5.363 ;
     RECT  91.848 5.077 93.36 5.507 ;
     RECT  33.096 5.125 34.08 5.605 ;
     RECT  90.024 5.125 91.824 6.133 ;
     RECT  5.232 5.171 5.256 5.653 ;
     RECT  103.704 5.171 105 5.173 ;
     RECT  103.704 5.173 104.88 6.517 ;
     RECT  111.864 5.173 113.136 5.507 ;
     RECT  116.112 5.363 117.192 5.701 ;
     RECT  118.872 5.365 120.048 5.653 ;
     RECT  9.096 5.605 10.128 6.035 ;
     RECT  71.016 5.605 72.384 7.379 ;
     RECT  96.024 5.605 97.248 7.525 ;
     RECT  4.584 5.653 5.256 6.613 ;
     RECT  74.088 5.653 75.264 5.747 ;
     RECT  116.112 5.701 117.168 7.381 ;
     RECT  74.448 5.747 75.264 6.229 ;
     RECT  97.272 5.747 97.512 6.037 ;
     RECT  102.72 5.747 103.68 6.709 ;
     RECT  84.792 5.749 85.872 6.323 ;
     RECT  86.136 5.845 87.6 6.805 ;
     RECT  87.624 5.845 88.8 6.373 ;
     RECT  33.768 5.891 34.8 8.437 ;
     RECT  9.096 6.035 9.336 7.043 ;
     RECT  110.712 6.083 111.24 7.285 ;
     RECT  124.488 6.083 124.728 7.333 ;
     RECT  90.552 6.133 91.824 6.323 ;
     RECT  84.792 6.323 86.064 6.805 ;
     RECT  94.632 6.323 95.952 8.147 ;
     RECT  35.928 6.371 37.008 7.381 ;
     RECT  103.752 6.517 104.88 6.805 ;
     RECT  89.544 6.563 90.528 7.523 ;
     RECT  4.584 6.613 5.76 7.381 ;
     RECT  102.72 6.709 103.152 6.853 ;
     RECT  60.744 6.805 61.8 7.955 ;
     RECT  69.096 6.805 70.128 7.043 ;
     RECT  84.984 6.805 86.064 7.235 ;
     RECT  86.136 6.805 87.36 7.619 ;
     RECT  87.384 6.851 88.512 7.619 ;
     RECT  119.112 6.851 120.288 9.923 ;
     RECT  56.952 6.853 58.32 7.475 ;
     RECT  76.968 6.853 78 7.621 ;
     RECT  106.536 6.995 107.568 7.957 ;
     RECT  8.112 7.043 9.336 7.381 ;
     RECT  84.984 7.235 86.112 7.667 ;
     RECT  110.712 7.285 111.888 10.883 ;
     RECT  111.912 7.285 113.136 7.331 ;
     RECT  62.472 7.333 63.696 7.475 ;
     RECT  8.112 7.381 9.312 8.723 ;
     RECT  58.344 7.381 59.568 7.475 ;
     RECT  59.592 7.381 60.72 7.955 ;
     RECT  56.952 7.475 57.24 7.957 ;
     RECT  99.504 7.571 99.6 9.013 ;
     RECT  37.608 7.619 38.736 7.763 ;
     RECT  86.136 7.619 86.52 9.013 ;
     RECT  84.648 7.667 86.112 9.541 ;
     RECT  95.976 7.667 97.248 8.147 ;
     RECT  37.608 7.763 38.784 10.067 ;
     RECT  49.752 7.909 51 8.627 ;
     RECT  100.968 7.909 102.432 9.059 ;
     RECT  80.784 7.955 80.808 8.389 ;
     RECT  106.584 7.957 107.568 8.099 ;
     RECT  20.376 8.003 21.408 8.965 ;
     RECT  116.112 8.003 117.168 9.061 ;
     RECT  106.536 8.099 107.568 9.589 ;
     RECT  94.632 8.147 97.248 8.485 ;
     RECT  44.088 8.197 45.6 11.749 ;
     RECT  80.784 8.389 81.84 8.485 ;
     RECT  117.192 8.389 118.272 8.869 ;
     RECT  38.808 8.483 40.2 10.067 ;
     RECT  66.72 8.483 67.2 9.637 ;
     RECT  80.784 8.485 80.976 8.965 ;
     RECT  81.864 8.485 83.28 10.069 ;
     RECT  95.16 8.485 97.248 9.349 ;
     RECT  50.736 8.627 51 9.637 ;
     RECT  63.864 8.627 64.104 9.925 ;
     RECT  88.512 8.627 88.8 9.397 ;
     RECT  4.56 8.723 4.8 9.155 ;
     RECT  8.112 8.723 9 10.069 ;
     RECT  35.736 8.723 36.864 9.635 ;
     RECT  102.744 8.723 103.968 10.261 ;
     RECT  125.4 8.773 126.6 9.205 ;
     RECT  78.312 8.965 79.632 10.021 ;
     RECT  79.656 8.965 80.976 9.301 ;
     RECT  97.512 9.013 98.976 9.875 ;
     RECT  101.808 9.059 102.432 9.253 ;
     RECT  4.56 9.155 5.136 10.069 ;
     RECT  11.496 9.155 12.48 9.203 ;
     RECT  125.496 9.205 126.6 9.925 ;
     RECT  74.52 9.301 75.504 10.835 ;
     RECT  79.8 9.301 80.976 9.779 ;
     RECT  126.912 9.301 127.92 16.595 ;
     RECT  21.48 9.347 22.656 11.459 ;
     RECT  95.16 9.349 96.48 10.163 ;
     RECT  87.768 9.397 88.8 10.307 ;
     RECT  67.512 9.541 68.736 10.693 ;
     RECT  70.728 9.541 71.76 10.501 ;
     RECT  109.176 9.589 110.4 10.739 ;
     RECT  35.736 9.635 36.912 10.549 ;
     RECT  60.456 9.637 61.8 9.685 ;
     RECT  60.456 9.685 61.536 10.115 ;
     RECT  96.504 9.731 97.488 10.307 ;
     RECT  27.096 9.875 28.464 10.883 ;
     RECT  97.512 9.875 97.656 10.261 ;
     RECT  118.872 9.923 120.288 9.973 ;
     RECT  63.864 9.925 64.992 10.163 ;
     RECT  125.544 9.925 126.6 11.749 ;
     RECT  118.872 9.973 120.192 10.259 ;
     RECT  37.608 10.067 37.944 10.883 ;
     RECT  3.432 10.069 5.136 10.309 ;
     RECT  60.456 10.115 61.8 10.307 ;
     RECT  63.84 10.163 64.992 10.307 ;
     RECT  118.872 10.259 120.288 11.507 ;
     RECT  102.792 10.261 103.968 10.645 ;
     RECT  13.512 10.307 14.544 11.365 ;
     RECT  63.84 10.307 65.016 10.837 ;
     RECT  96.504 10.307 97.632 10.355 ;
     RECT  3.432 10.309 4.512 11.075 ;
     RECT  4.536 10.355 5.76 12.467 ;
     RECT  83.28 10.355 83.4 11.797 ;
     RECT  42.744 10.453 44.064 11.029 ;
     RECT  35.832 10.549 36.912 10.981 ;
     RECT  20.088 10.595 21.456 11.459 ;
     RECT  70.752 10.643 71.28 11.893 ;
     RECT  102.888 10.645 103.968 11.413 ;
     RECT  67.512 10.693 68.496 11.459 ;
     RECT  63.84 10.837 66.144 11.557 ;
     RECT  36.936 10.883 37.944 10.981 ;
     RECT  78.312 10.883 79.632 13.045 ;
     RECT  110.712 10.883 111.912 11.893 ;
     RECT  36.936 10.981 37.92 11.699 ;
     RECT  71.304 11.027 72.6 13.525 ;
     RECT  40.512 11.029 41.568 13.045 ;
     RECT  41.592 11.029 42.72 12.755 ;
     RECT  67.512 11.459 68.736 11.989 ;
     RECT  85.512 11.459 86.136 12.709 ;
     RECT  106.056 11.459 107.184 12.563 ;
     RECT  33.408 11.507 34.224 12.035 ;
     RECT  118.776 11.507 120.288 12.181 ;
     RECT  62.664 11.557 66.144 11.605 ;
     RECT  62.664 11.605 63.744 12.563 ;
     RECT  63.768 11.605 66.144 11.797 ;
     RECT  44.472 11.749 45.6 12.563 ;
     RECT  63.768 11.797 65.28 13.045 ;
     RECT  110.712 11.893 112.896 11.941 ;
     RECT  42.744 11.939 44.064 12.275 ;
     RECT  5.784 11.941 7.296 12.467 ;
     RECT  76.008 11.941 77.52 12.035 ;
     RECT  111.384 11.941 112.896 12.997 ;
     RECT  35.4 11.987 36.432 12.131 ;
     RECT  67.656 11.989 68.736 12.757 ;
     RECT  28.752 12.035 29.088 13.429 ;
     RECT  33.408 12.035 34.56 12.757 ;
     RECT  103.224 12.035 104.256 12.563 ;
     RECT  35.112 12.131 36.432 14.821 ;
     RECT  118.776 12.181 119.904 12.323 ;
     RECT  53.208 12.517 54.576 13.619 ;
     RECT  72.912 12.517 74.256 13.093 ;
     RECT  15.576 12.563 16.656 13.139 ;
     RECT  16.728 12.563 17.808 12.659 ;
     RECT  24.408 12.563 25.44 13.621 ;
     RECT  44.448 12.563 45.6 13.621 ;
     RECT  103.176 12.563 104.256 14.053 ;
     RECT  14.376 12.611 15.552 13.139 ;
     RECT  16.68 12.659 17.808 13.139 ;
     RECT  31.608 12.757 32.928 13.573 ;
     RECT  32.952 12.757 34.56 13.093 ;
     RECT  81.864 12.803 83.232 14.435 ;
     RECT  67.656 12.899 68.736 13.043 ;
     RECT  111.384 12.997 112.848 13.237 ;
     RECT  78.312 13.045 79.296 13.715 ;
     RECT  108.264 13.045 109.488 13.283 ;
     RECT  33.096 13.093 34.56 13.621 ;
     RECT  72.912 13.093 74.064 15.301 ;
     RECT  23.04 13.139 24 14.149 ;
     RECT  85.272 13.139 86.448 13.619 ;
     RECT  102.912 13.139 103.152 14.629 ;
     RECT  64.392 13.235 65.304 13.859 ;
     RECT  111.384 13.237 112.56 13.379 ;
     RECT  107.928 13.283 109.488 13.333 ;
     RECT  107.928 13.333 109.344 15.205 ;
     RECT  113.112 13.333 114.528 13.621 ;
     RECT  19.032 13.379 19.224 13.621 ;
     RECT  111.384 13.379 112.896 13.667 ;
     RECT  91.8 13.429 92.88 14.819 ;
     RECT  7.68 13.475 7.8 14.773 ;
     RECT  38.712 13.573 40.2 14.963 ;
     RECT  53.76 13.619 54.576 14.485 ;
     RECT  97.632 13.619 97.656 14.437 ;
     RECT  114.552 13.619 115.68 15.301 ;
     RECT  19.032 13.621 20.496 15.443 ;
     RECT  33.432 13.621 34.56 14.963 ;
     RECT  44.472 13.621 45.6 14.291 ;
     RECT  113.304 13.621 114.528 14.197 ;
     RECT  71.04 13.667 71.28 14.629 ;
     RECT  29.04 13.715 29.4 14.917 ;
     RECT  78.312 13.715 79.44 14.771 ;
     RECT  24.312 13.859 25.344 14.339 ;
     RECT  32.28 13.859 33.408 14.051 ;
     RECT  65.28 13.859 65.304 14.725 ;
     RECT  117.432 14.003 118.464 15.349 ;
     RECT  22.968 14.149 24 14.339 ;
     RECT  113.448 14.197 114.528 14.533 ;
     RECT  24.312 14.339 25.728 14.483 ;
     RECT  79.8 14.389 80.976 15.299 ;
     RECT  97.464 14.437 97.656 14.485 ;
     RECT  24.312 14.483 24.6 15.973 ;
     RECT  37.368 14.485 38.688 14.963 ;
     RECT  97.464 14.485 98.544 14.867 ;
     RECT  113.448 14.533 114.432 15.733 ;
     RECT  62.112 14.723 62.76 15.109 ;
     RECT  56.712 14.725 58.128 14.917 ;
     RECT  78.312 14.771 79.632 17.315 ;
     RECT  118.536 14.867 119.52 16.021 ;
     RECT  124.584 14.867 125.616 15.443 ;
     RECT  56.712 14.917 57.792 16.787 ;
     RECT  39.888 14.963 40.2 15.973 ;
     RECT  29.04 15.059 29.4 16.501 ;
     RECT  74.088 15.061 75.168 15.443 ;
     RECT  62.112 15.109 63.168 16.307 ;
     RECT  107.928 15.205 109.104 15.541 ;
     RECT  89.208 15.251 89.928 15.733 ;
     RECT  46.008 15.299 46.248 16.405 ;
     RECT  79.656 15.299 80.976 16.499 ;
     RECT  101.88 15.301 102.912 16.835 ;
     RECT  114.696 15.301 115.68 16.309 ;
     RECT  4.536 15.395 4.728 16.501 ;
     RECT  103.08 15.443 104.544 17.029 ;
     RECT  124.44 15.443 125.616 15.829 ;
     RECT  89.208 15.733 90.528 17.171 ;
     RECT  124.44 15.829 125.568 16.165 ;
     RECT  111.24 15.877 112.656 15.925 ;
     RECT  2.712 16.019 2.808 16.405 ;
     RECT  111.816 16.019 112.8 17.029 ;
     RECT  124.44 16.165 125.424 16.933 ;
     RECT  2.712 16.405 3.888 16.883 ;
     RECT  79.656 16.499 80.712 16.501 ;
     RECT  11.784 16.501 13.2 17.029 ;
     RECT  27.72 16.501 28.896 17.651 ;
     RECT  79.656 16.501 80.688 17.315 ;
     RECT  55.44 16.595 55.968 17.603 ;
     RECT  35.592 16.739 37.008 17.507 ;
     RECT  56.712 16.787 57.048 16.981 ;
     RECT  118.824 16.787 119.904 17.603 ;
     RECT  24.312 16.835 24.6 16.981 ;
     RECT  102.576 16.835 102.912 17.605 ;
     RECT  105.312 16.837 106.56 17.125 ;
     RECT  4.536 16.883 5.112 18.037 ;
     RECT  114.456 16.883 115.8 17.699 ;
     RECT  24.312 16.981 25.728 19.091 ;
     RECT  11.784 17.029 12.768 17.123 ;
     RECT  103.08 17.029 104.256 18.179 ;
     RECT  68.376 17.077 69.744 17.651 ;
     RECT  83.712 17.077 84.768 17.219 ;
     RECT  84.792 17.077 86.064 17.219 ;
     RECT  124.248 17.123 125.424 18.179 ;
     RECT  105.432 17.125 106.56 17.699 ;
     RECT  89.208 17.171 90.072 17.653 ;
     RECT  92.904 17.171 94.08 20.579 ;
     RECT  83.712 17.219 83.832 18.181 ;
     RECT  78.312 17.315 80.688 17.363 ;
     RECT  78.312 17.363 80.712 18.181 ;
     RECT  107.256 17.363 108.624 17.603 ;
     RECT  109.032 17.459 110.4 18.421 ;
     RECT  31.536 17.507 31.584 18.709 ;
     RECT  55.44 17.603 56.4 17.653 ;
     RECT  118.728 17.603 119.904 18.661 ;
     RECT  75.288 17.605 76.752 17.891 ;
     RECT  76.776 17.605 78 19.525 ;
     RECT  68.376 17.651 69.888 18.371 ;
     RECT  54.936 17.653 56.4 18.419 ;
     RECT  89.688 17.653 90.072 18.181 ;
     RECT  105.432 17.699 106.704 19.189 ;
     RECT  98.088 17.845 99.36 18.179 ;
     RECT  75.192 17.891 76.752 18.947 ;
     RECT  4.536 18.037 5.664 18.661 ;
     RECT  51.312 18.037 52.464 18.851 ;
     RECT  98.088 18.179 99.6 18.181 ;
     RECT  103.08 18.179 104.88 18.709 ;
     RECT  124.248 18.179 125.904 18.181 ;
     RECT  49.992 18.181 51 18.755 ;
     RECT  78.312 18.181 80.832 18.709 ;
     RECT  98.616 18.181 99.6 19.523 ;
     RECT  124.824 18.181 125.904 18.851 ;
     RECT  4.632 18.661 5.664 18.851 ;
     RECT  118.728 18.661 119.856 18.995 ;
     RECT  78.312 18.709 79.584 19.763 ;
     RECT  79.608 18.709 80.832 19.763 ;
     RECT  103.848 18.709 104.88 19.237 ;
     RECT  49.968 18.755 51 19.813 ;
     RECT  4.632 18.851 5.112 19.765 ;
     RECT  124.824 18.851 126.48 19.333 ;
     RECT  75.144 18.947 76.752 19.285 ;
     RECT  112.008 18.949 113.424 19.091 ;
     RECT  23.04 18.995 24 19.621 ;
     RECT  111.912 19.091 113.424 19.331 ;
     RECT  60.744 19.093 61.8 19.333 ;
     RECT  80.856 19.141 82.272 19.811 ;
     RECT  100.872 19.187 100.968 20.389 ;
     RECT  105.48 19.189 106.704 19.811 ;
     RECT  96.696 19.237 98.064 20.005 ;
     RECT  117.576 19.283 117.72 20.485 ;
     RECT  75.144 19.285 76.608 20.339 ;
     RECT  125.448 19.333 126.48 20.483 ;
     RECT  98.088 19.523 99.6 20.581 ;
     RECT  23.016 19.621 24 20.915 ;
     RECT  78.312 19.763 79.224 20.293 ;
     RECT  80.856 19.811 83.232 20.243 ;
     RECT  105.432 19.811 106.704 20.483 ;
     RECT  48.792 19.813 51 20.149 ;
     RECT  107.784 19.909 108.912 21.443 ;
     RECT  102.6 20.003 103.824 20.435 ;
     RECT  96.696 20.005 97.728 20.629 ;
     RECT  48.792 20.149 49.776 21.155 ;
     RECT  49.8 20.149 51 21.155 ;
     RECT  80.856 20.243 83.28 20.725 ;
     RECT  119.856 20.243 120 20.339 ;
     RECT  75.072 20.291 75.12 20.579 ;
     RECT  119.856 20.339 120.048 21.541 ;
     RECT  102.6 20.435 104.064 20.675 ;
     RECT  105.432 20.483 105.672 21.637 ;
     RECT  75.072 20.579 75.096 21.781 ;
     RECT  92.904 20.579 94.2 22.021 ;
     RECT  100.296 20.579 101.664 21.155 ;
     RECT  109.032 20.579 110.112 20.915 ;
     RECT  98.616 20.581 99.6 22.453 ;
     RECT  101.688 20.675 102.312 22.165 ;
     RECT  80.856 20.725 82.08 21.061 ;
     RECT  82.104 20.725 83.28 21.155 ;
     RECT  108.936 20.915 110.112 21.443 ;
     RECT  80.952 21.061 82.08 21.347 ;
     RECT  62.76 21.109 64.176 21.299 ;
     RECT  48.792 21.155 51 21.493 ;
     RECT  82.104 21.155 83.4 21.683 ;
     RECT  89.112 21.155 89.448 22.165 ;
     RECT  100.248 21.155 101.664 23.363 ;
     RECT  111.912 21.155 112.896 22.979 ;
     RECT  76.776 21.395 78 22.259 ;
     RECT  107.784 21.443 108.072 21.493 ;
     RECT  49.656 21.493 51 23.555 ;
     RECT  97.032 21.539 98.064 23.125 ;
     RECT  118.488 21.541 120.048 21.637 ;
     RECT  118.536 21.637 120.048 22.739 ;
     RECT  122.52 21.683 123.552 22.259 ;
     RECT  48.768 21.971 49.488 23.125 ;
     RECT  38.856 22.117 40.2 22.741 ;
     RECT  8.856 22.259 10.368 22.499 ;
     RECT  122.52 22.259 123.696 22.595 ;
     RECT  18.912 22.453 19.968 24.851 ;
     RECT  110.112 22.547 110.4 23.797 ;
     RECT  75.072 22.739 75.984 23.075 ;
     RECT  108.048 22.739 108.072 23.797 ;
     RECT  118.488 22.739 120.048 22.741 ;
     RECT  13.512 22.741 14.496 23.795 ;
     RECT  38.856 22.741 40.08 23.699 ;
     RECT  86.088 22.741 87.168 23.411 ;
     RECT  118.488 22.741 119.664 23.893 ;
     RECT  24.312 22.787 25.08 24.181 ;
     RECT  78.408 22.787 78.648 23.845 ;
     RECT  92.904 22.883 94.2 23.941 ;
     RECT  116.28 22.883 117.696 23.171 ;
     RECT  75.072 23.075 76.368 23.317 ;
     RECT  48.168 23.125 49.488 24.037 ;
     RECT  116.28 23.171 117.936 23.555 ;
     RECT  97.464 23.315 98.64 23.555 ;
     RECT  29.712 23.317 30.816 27.877 ;
     RECT  74.808 23.317 76.368 23.845 ;
     RECT  100.248 23.363 100.296 23.411 ;
     RECT  61.536 23.411 61.8 24.709 ;
     RECT  86.088 23.411 86.952 23.557 ;
     RECT  99.912 23.411 100.296 24.517 ;
     RECT  49.512 23.555 51 24.083 ;
     RECT  116.232 23.555 117.936 24.469 ;
     RECT  38.856 23.699 40.2 25.811 ;
     RECT  13.512 23.795 14.52 24.469 ;
     RECT  108.048 23.797 108.96 24.181 ;
     RECT  108.984 23.797 110.4 25.091 ;
     RECT  75.288 23.845 76.368 24.517 ;
     RECT  79.272 23.845 80.592 24.083 ;
     RECT  118.536 23.893 119.664 25.139 ;
     RECT  119.688 23.987 120.912 24.563 ;
     RECT  48.168 24.037 49.344 24.085 ;
     RECT  79.272 24.083 81.552 24.899 ;
     RECT  48.144 24.131 48.912 24.757 ;
     RECT  24.312 24.181 25.68 24.949 ;
     RECT  107.448 24.181 108.96 25.091 ;
     RECT  13.512 24.469 14.976 25.763 ;
     RECT  116.232 24.469 117.408 24.995 ;
     RECT  124.776 24.469 125.904 24.563 ;
     RECT  121.512 24.515 121.608 25.717 ;
     RECT  92.904 24.563 94.032 25.861 ;
     RECT  117.432 24.563 118.512 24.995 ;
     RECT  119.688 24.563 121.2 25.573 ;
     RECT  124.2 24.563 125.904 24.611 ;
     RECT  8.112 24.611 8.232 26.101 ;
     RECT  124.104 24.611 125.904 25.139 ;
     RECT  47.496 24.757 48.912 25.621 ;
     RECT  18.912 24.851 20.112 25.763 ;
     RECT  83.712 24.853 84.912 25.043 ;
     RECT  43.008 24.899 43.032 25.621 ;
     RECT  78.744 24.899 81.552 25.187 ;
     RECT  24.408 24.949 25.68 25.093 ;
     RECT  116.112 24.995 116.904 26.197 ;
     RECT  83.712 25.043 84.936 25.957 ;
     RECT  55.272 25.045 56.4 25.621 ;
     RECT  70.008 25.045 71.472 25.667 ;
     RECT  24.696 25.093 25.68 25.811 ;
     RECT  124.8 25.139 125.904 25.429 ;
     RECT  78.744 25.187 81.696 25.573 ;
     RECT  76.536 25.333 78 26.675 ;
     RECT  98.616 25.429 99.6 28.501 ;
     RECT  124.8 25.429 125.856 25.573 ;
     RECT  82.152 25.475 83.4 27.301 ;
     RECT  75.288 25.571 76.368 26.725 ;
     RECT  78.744 25.573 80.304 25.621 ;
     RECT  80.328 25.573 81.696 26.245 ;
     RECT  114.744 25.573 115.8 25.813 ;
     RECT  119.976 25.573 121.2 26.053 ;
     RECT  124.8 25.573 125.376 25.621 ;
     RECT  42.792 25.621 43.032 26.149 ;
     RECT  55.32 25.621 56.4 26.869 ;
     RECT  78.744 25.621 80.064 26.627 ;
     RECT  124.8 25.621 125.28 26.197 ;
     RECT  30.84 25.763 30.936 27.061 ;
     RECT  24.504 25.811 25.68 26.387 ;
     RECT  49.368 25.813 50.88 26.053 ;
     RECT  53.592 25.861 54.864 26.053 ;
     RECT  84.504 25.957 84.936 26.053 ;
     RECT  49.656 26.053 50.88 26.821 ;
     RECT  53.64 26.053 54.864 26.149 ;
     RECT  100.008 26.147 100.2 27.637 ;
     RECT  102.696 26.197 103.68 26.579 ;
     RECT  94.632 26.243 94.728 27.349 ;
     RECT  80.664 26.245 81.696 26.819 ;
     RECT  114.744 26.291 115.8 27.347 ;
     RECT  17.112 26.341 18.48 26.531 ;
     RECT  24.312 26.387 25.68 27.397 ;
     RECT  72.912 26.437 73.968 28.403 ;
     RECT  85.128 26.437 86.16 29.029 ;
     RECT  18.384 26.531 18.48 27.253 ;
     RECT  102.696 26.579 103.92 27.347 ;
     RECT  63.24 26.581 64.224 27.395 ;
     RECT  78.408 26.627 80.064 26.629 ;
     RECT  78.408 26.629 79.776 27.877 ;
     RECT  76.392 26.675 78 26.819 ;
     RECT  52.968 26.819 53.952 29.555 ;
     RECT  77.232 26.819 78 27.781 ;
     RECT  80.664 26.819 82.128 28.453 ;
     RECT  116.76 26.867 116.904 27.637 ;
     RECT  107.448 26.869 108.864 27.059 ;
     RECT  108.888 26.869 110.4 27.059 ;
     RECT  55.32 27.011 56.4 28.405 ;
     RECT  107.448 27.059 110.4 27.589 ;
     RECT  30.84 27.061 32.16 28.405 ;
     RECT  72.432 27.251 72.48 28.405 ;
     RECT  68.04 27.301 69.264 29.027 ;
     RECT  82.248 27.301 83.4 28.547 ;
     RECT  105.672 27.301 107.088 28.453 ;
     RECT  102.696 27.347 104.064 28.549 ;
     RECT  24.456 27.397 25.68 29.747 ;
     RECT  107.448 27.589 109.248 28.501 ;
     RECT  109.272 27.589 110.4 27.877 ;
     RECT  116.76 27.637 118.08 28.165 ;
     RECT  34.272 27.683 34.608 27.733 ;
     RECT  33.048 27.733 34.608 28.019 ;
     RECT  59.88 27.733 61.008 28.451 ;
     RECT  57.576 27.877 59.04 28.979 ;
     RECT  78.696 27.877 79.776 28.357 ;
     RECT  93.096 27.923 94.2 29.029 ;
     RECT  33.048 28.019 34.8 28.453 ;
     RECT  116.904 28.165 118.08 28.451 ;
     RECT  99.912 28.259 100.008 29.317 ;
     RECT  72.912 28.403 74.064 29.509 ;
     RECT  30.84 28.405 32.064 31.427 ;
     RECT  51.312 28.405 52.464 29.221 ;
     RECT  116.904 28.451 117.336 29.605 ;
     RECT  33.576 28.453 34.8 34.259 ;
     RECT  80.808 28.453 82.128 29.221 ;
     RECT  105.672 28.453 106.896 31.813 ;
     RECT  121.992 28.453 123.264 29.077 ;
     RECT  62.112 28.499 62.328 29.557 ;
     RECT  107.448 28.501 108.816 28.643 ;
     RECT  82.152 28.547 83.4 29.699 ;
     RECT  98.592 28.643 99.6 28.933 ;
     RECT  107.448 28.643 107.64 28.837 ;
     RECT  90.984 28.787 92.064 32.531 ;
     RECT  35.112 28.931 36.024 30.133 ;
     RECT  40.776 28.933 41.904 29.699 ;
     RECT  41.928 28.933 43.056 29.509 ;
     RECT  96.36 28.933 97.728 29.075 ;
     RECT  97.752 28.933 99.6 29.075 ;
     RECT  57.576 28.979 59.064 29.509 ;
     RECT  68.04 29.027 69.408 29.459 ;
     RECT  75.528 29.029 76.704 29.843 ;
     RECT  61.008 29.075 61.2 30.229 ;
     RECT  96.36 29.075 99.6 29.221 ;
     RECT  121.992 29.077 123.168 29.747 ;
     RECT  32.088 29.123 33.552 30.565 ;
     RECT  79.08 29.123 80.64 30.133 ;
     RECT  29.712 29.219 30.816 36.611 ;
     RECT  103.56 29.219 105 31.189 ;
     RECT  80.904 29.221 82.128 29.509 ;
     RECT  96.36 29.221 97.68 29.315 ;
     RECT  97.704 29.221 99.6 30.085 ;
     RECT  97.584 29.315 97.68 29.653 ;
     RECT  125.4 29.315 126.6 31.379 ;
     RECT  76.728 29.507 78 30.709 ;
     RECT  58.776 29.509 59.064 30.229 ;
     RECT  80.904 29.509 81.888 30.659 ;
     RECT  52.488 29.555 53.952 30.323 ;
     RECT  63.096 29.557 64.224 31.669 ;
     RECT  64.248 29.605 65.376 30.803 ;
     RECT  40.728 29.699 41.904 34.405 ;
     RECT  81.912 29.699 83.4 30.659 ;
     RECT  24.456 29.747 24.744 30.613 ;
     RECT  57.048 29.795 58.464 30.083 ;
     RECT  74.136 29.795 75.504 29.843 ;
     RECT  56.904 30.083 58.464 31.237 ;
     RECT  109.272 30.083 110.304 31.909 ;
     RECT  97.704 30.085 99.168 30.419 ;
     RECT  35.112 30.133 36.624 31.765 ;
     RECT  58.776 30.229 59.808 30.275 ;
     RECT  59.832 30.229 61.2 30.805 ;
     RECT  58.488 30.275 59.808 32.435 ;
     RECT  92.904 30.275 94.2 32.773 ;
     RECT  52.488 30.323 52.728 30.949 ;
     RECT  43.656 30.469 44.64 30.757 ;
     RECT  32.52 30.565 33.552 30.707 ;
     RECT  123.168 30.611 123.36 31.187 ;
     RECT  24.504 30.613 24.744 30.901 ;
     RECT  83.184 30.659 83.4 31.141 ;
     RECT  117.24 30.659 117.336 31.957 ;
     RECT  13.512 30.707 13.608 30.997 ;
     RECT  32.088 30.707 33.552 31.427 ;
     RECT  2.712 30.709 3.936 30.851 ;
     RECT  76.728 30.709 77.856 30.947 ;
     RECT  97.584 30.755 97.608 31.477 ;
     RECT  64.248 30.803 66.336 31.813 ;
     RECT  59.832 30.805 60.864 31.381 ;
     RECT  67.512 30.851 67.608 32.245 ;
     RECT  107.736 30.853 109.248 31.717 ;
     RECT  76.752 30.947 77.856 31.285 ;
     RECT  13.512 30.997 14.832 33.781 ;
     RECT  113.88 31.045 115.152 31.139 ;
     RECT  36.648 31.093 38.064 31.955 ;
     RECT  54.456 31.139 55.776 33.013 ;
     RECT  123.48 31.139 124.752 31.379 ;
     RECT  123.168 31.187 123.456 31.525 ;
     RECT  103.56 31.189 104.832 31.621 ;
     RECT  94.68 31.235 95.016 31.909 ;
     RECT  76.776 31.285 77.856 31.523 ;
     RECT  125.112 31.379 126.6 31.475 ;
     RECT  59.832 31.381 60.816 32.053 ;
     RECT  30.84 31.427 33.552 31.477 ;
     RECT  126.336 31.475 126.6 32.437 ;
     RECT  31.656 31.477 33.552 31.715 ;
     RECT  97.368 31.477 97.608 31.909 ;
     RECT  69.528 31.523 70.152 31.859 ;
     RECT  76.776 31.523 78 33.059 ;
     RECT  116.112 31.523 117.216 32.725 ;
     RECT  121.992 31.525 123.456 32.243 ;
     RECT  103.752 31.621 104.832 31.909 ;
     RECT  31.512 31.715 33.552 32.437 ;
     RECT  35.208 31.765 36.624 32.341 ;
     RECT  64.968 31.813 66.336 32.291 ;
     RECT  70.128 31.859 70.152 33.013 ;
     RECT  94.68 31.909 96.192 31.957 ;
     RECT  96.216 31.909 97.344 32.099 ;
     RECT  97.512 31.909 97.608 32.245 ;
     RECT  36.648 31.955 36.888 32.437 ;
     RECT  72.912 31.955 74.112 33.059 ;
     RECT  80.544 31.955 80.568 33.013 ;
     RECT  94.68 31.957 95.76 32.003 ;
     RECT  94.632 32.003 95.76 32.531 ;
     RECT  99.912 32.051 100.872 32.341 ;
     RECT  95.88 32.099 97.344 32.243 ;
     RECT  53.016 32.149 54.432 32.341 ;
     RECT  67.512 32.245 68.496 34.355 ;
     RECT  35.208 32.341 36.336 33.395 ;
     RECT  53.016 32.341 54.144 32.821 ;
     RECT  99.912 32.341 100.896 32.531 ;
     RECT  31.512 32.437 32.592 32.821 ;
     RECT  90.984 32.531 92.256 33.059 ;
     RECT  94.512 32.531 95.76 33.683 ;
     RECT  116.232 32.725 117.216 37.573 ;
     RECT  39.192 32.821 40.2 34.453 ;
     RECT  53.016 32.821 54.048 33.013 ;
     RECT  22.8 32.963 23.04 33.493 ;
     RECT  54.648 33.013 55.776 33.635 ;
     RECT  62.856 33.059 64.224 33.971 ;
     RECT  91.536 33.059 92.256 33.733 ;
     RECT  59.832 33.299 60.864 33.491 ;
     RECT  60.432 33.491 60.864 34.549 ;
     RECT  21.624 33.493 23.04 34.355 ;
     RECT  54.648 33.635 55.824 33.827 ;
     RECT  93 33.779 94.2 36.085 ;
     RECT  13.512 33.781 14.496 38.627 ;
     RECT  54.648 33.827 54.84 34.981 ;
     RECT  96.264 34.117 97.344 35.507 ;
     RECT  67.512 34.355 69.312 35.845 ;
     RECT  75.72 34.355 75.864 34.403 ;
     RECT  75.696 34.403 75.864 35.317 ;
     RECT  5.544 34.501 6.864 35.363 ;
     RECT  60.456 34.595 61.44 34.787 ;
     RECT  2.712 34.931 2.808 36.421 ;
     RECT  54.792 34.981 54.84 35.269 ;
     RECT  107.544 35.123 107.784 36.421 ;
     RECT  75.696 35.317 76.032 35.749 ;
     RECT  55.176 35.365 56.4 36.037 ;
     RECT  76.056 35.413 77.52 35.843 ;
     RECT  39.096 35.459 40.2 36.515 ;
     RECT  96.264 35.507 97.488 36.421 ;
     RECT  52.344 35.747 53.616 36.515 ;
     RECT  10.824 35.749 12.192 36.515 ;
     RECT  12.216 35.749 13.2 36.515 ;
     RECT  74.712 35.749 76.032 35.843 ;
     RECT  102 35.795 102.096 36.565 ;
     RECT  74.712 35.843 75.576 36.661 ;
     RECT  67.8 35.845 69.312 36.277 ;
     RECT  18 35.939 18.6 37.093 ;
     RECT  78.312 36.035 78.792 37.045 ;
     RECT  22.008 36.037 23.04 36.659 ;
     RECT  67.8 36.277 69.216 36.565 ;
     RECT  2.712 36.421 3.696 37.475 ;
     RECT  96.36 36.421 97.488 38.485 ;
     RECT  38.76 36.515 40.2 36.997 ;
     RECT  52.344 36.515 53.664 37.573 ;
     RECT  64.248 36.565 65.424 36.949 ;
     RECT  73.272 36.565 74.688 36.613 ;
     RECT  100.776 36.565 102.096 36.709 ;
     RECT  105.312 36.565 106.56 36.661 ;
     RECT  29.712 36.611 29.88 38.101 ;
     RECT  105.432 36.661 106.56 36.899 ;
     RECT  100.92 36.709 102.096 36.995 ;
     RECT  97.512 36.853 98.592 37.091 ;
     RECT  98.616 36.853 99.6 37.091 ;
     RECT  73.272 36.899 74.688 37.379 ;
     RECT  99.912 36.899 100.896 36.995 ;
     RECT  105.432 36.899 106.896 37.139 ;
     RECT  6.792 36.901 7.8 39.251 ;
     RECT  64.344 36.949 65.328 38.051 ;
     RECT  38.76 36.997 40.08 37.957 ;
     RECT  65.448 37.189 66.768 37.571 ;
     RECT  104.304 37.235 105 38.485 ;
     RECT  3.72 37.429 5.088 37.475 ;
     RECT  65.352 37.571 66.768 38.051 ;
     RECT  52.44 37.573 53.664 40.355 ;
     RECT  116.52 37.619 117.648 37.859 ;
     RECT  38.76 37.957 40.032 38.725 ;
     RECT  79.032 38.005 80.16 38.149 ;
     RECT  24.312 38.149 25.68 39.779 ;
     RECT  62.808 38.149 63.792 38.435 ;
     RECT  79.032 38.149 80.016 39.875 ;
     RECT  55.272 38.243 56.4 39.301 ;
     RECT  62.808 38.435 64.224 40.835 ;
     RECT  68.136 38.483 69.312 38.819 ;
     RECT  13.512 38.627 13.704 39.589 ;
     RECT  92.904 38.675 94.08 40.691 ;
     RECT  61.44 38.723 61.8 39.301 ;
     RECT  38.76 38.725 39.936 39.301 ;
     RECT  97.896 38.773 99.216 39.347 ;
     RECT  68.136 38.819 69.336 39.733 ;
     RECT  89.112 38.819 89.208 39.829 ;
     RECT  57 39.205 58.176 39.587 ;
     RECT  7.584 39.251 7.8 39.589 ;
     RECT  38.904 39.301 39.936 40.019 ;
     RECT  55.368 39.301 56.4 40.595 ;
     RECT  60.456 39.301 61.8 39.923 ;
     RECT  97.896 39.347 99.264 40.115 ;
     RECT  22.92 39.587 24 40.595 ;
     RECT  56.712 39.587 58.176 40.451 ;
     RECT  110.712 39.637 111.84 40.595 ;
     RECT  68.136 39.733 69.552 40.259 ;
     RECT  40.512 39.923 41.52 39.971 ;
     RECT  38.904 40.019 40.032 40.067 ;
     RECT  38.904 40.067 40.2 40.307 ;
     RECT  54.168 40.307 55.152 40.499 ;
     RECT  52.392 40.355 53.664 40.453 ;
     RECT  52.392 40.453 53.472 40.499 ;
     RECT  52.248 40.499 53.472 43.068 ;
     RECT  54.168 40.499 55.248 40.547 ;
     RECT  54.168 40.547 55.344 40.595 ;
     RECT  92.904 40.691 94.2 41.063 ;
     RECT  52.296 43.068 53.424 43.152 ;
  END
END dsfd_gth_ctl
END LIBRARY
